VERSION 5.8 ;
BUSBITCHARS "[]" ;
DIVIDERCHAR "/" ;
UNITS
    DATABASE MICRONS 1000 ;
END UNITS

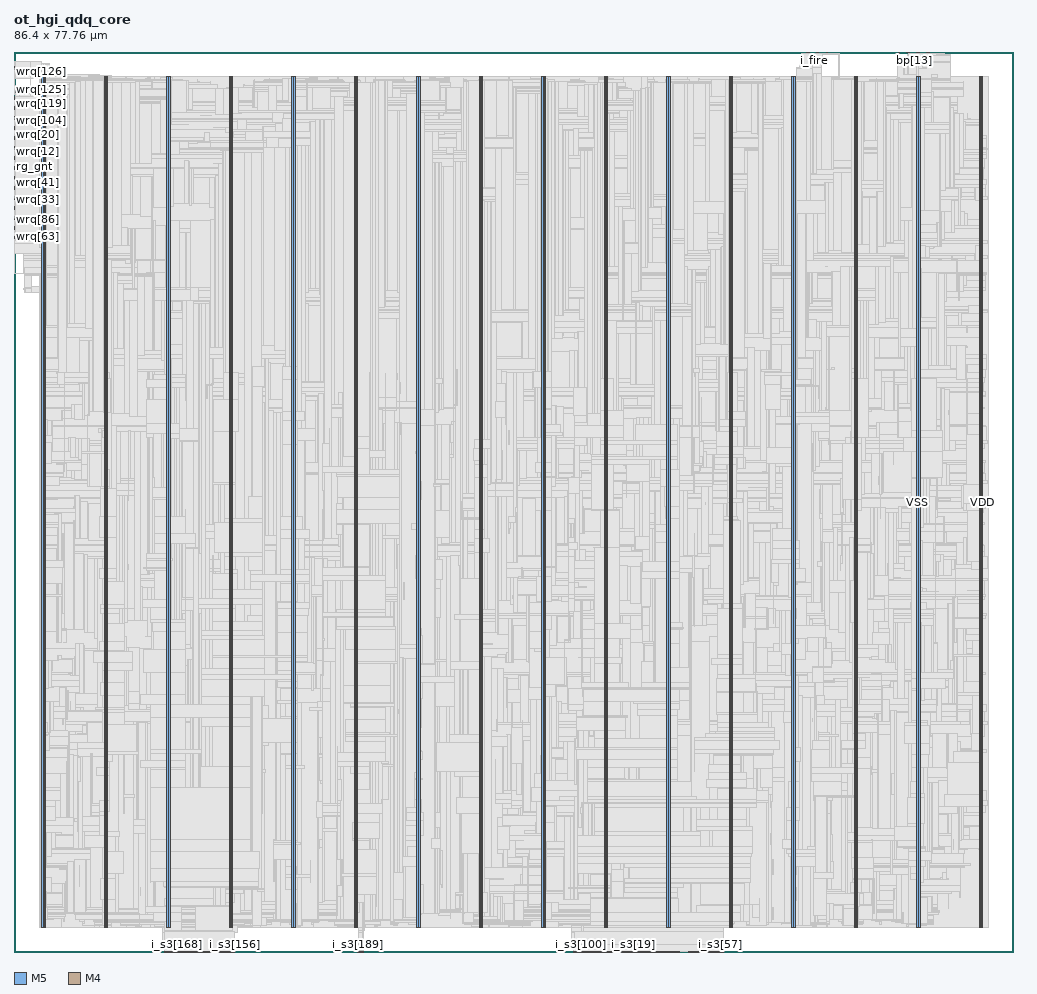
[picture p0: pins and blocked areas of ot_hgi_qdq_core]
MACRO ot_hgi_qdq_core
  FOREIGN ot_hgi_qdq_core 0 0 ;
  CLASS BLOCK ;
  SIZE 86.4 BY 77.76 ;
  PIN asm_rst_n
    DIRECTION OUTPUT ;
    USE SIGNAL ;
    PORT
      LAYER M5 ;
        RECT  76.464 77.676 76.488 77.76 ;
    END
  END asm_rst_n
  PIN bp[0]
    DIRECTION OUTPUT ;
    USE SIGNAL ;
    PORT
      LAYER M5 ;
        RECT  76.56 77.676 76.584 77.76 ;
    END
  END bp[0]
  PIN bp[10]
    DIRECTION OUTPUT ;
    USE SIGNAL ;
    PORT
      LAYER M5 ;
        RECT  77.52 77.676 77.544 77.76 ;
    END
  END bp[10]
  PIN bp[11]
    DIRECTION OUTPUT ;
    USE SIGNAL ;
    PORT
      LAYER M5 ;
        RECT  77.616 77.676 77.64 77.76 ;
    END
  END bp[11]
  PIN bp[12]
    DIRECTION OUTPUT ;
    USE SIGNAL ;
    PORT
      LAYER M5 ;
        RECT  77.712 77.676 77.736 77.76 ;
    END
  END bp[12]
  PIN bp[13]
    DIRECTION OUTPUT ;
    USE SIGNAL ;
    PORT
      LAYER M5 ;
        RECT  77.808 77.676 77.832 77.76 ;
    END
  END bp[13]
  PIN bp[14]
    DIRECTION OUTPUT ;
    USE SIGNAL ;
    PORT
      LAYER M5 ;
        RECT  77.904 77.676 77.928 77.76 ;
    END
  END bp[14]
  PIN bp[15]
    DIRECTION OUTPUT ;
    USE SIGNAL ;
    PORT
      LAYER M5 ;
        RECT  78 77.676 78.024 77.76 ;
    END
  END bp[15]
  PIN bp[16]
    DIRECTION OUTPUT ;
    USE SIGNAL ;
    PORT
      LAYER M5 ;
        RECT  78.096 77.676 78.12 77.76 ;
    END
  END bp[16]
  PIN bp[17]
    DIRECTION OUTPUT ;
    USE SIGNAL ;
    PORT
      LAYER M5 ;
        RECT  78.192 77.676 78.216 77.76 ;
    END
  END bp[17]
  PIN bp[18]
    DIRECTION OUTPUT ;
    USE SIGNAL ;
    PORT
      LAYER M5 ;
        RECT  78.288 77.676 78.312 77.76 ;
    END
  END bp[18]
  PIN bp[19]
    DIRECTION OUTPUT ;
    USE SIGNAL ;
    PORT
      LAYER M5 ;
        RECT  78.384 77.676 78.408 77.76 ;
    END
  END bp[19]
  PIN bp[1]
    DIRECTION OUTPUT ;
    USE SIGNAL ;
    PORT
      LAYER M5 ;
        RECT  76.656 77.676 76.68 77.76 ;
    END
  END bp[1]
  PIN bp[20]
    DIRECTION OUTPUT ;
    USE SIGNAL ;
    PORT
      LAYER M5 ;
        RECT  78.48 77.676 78.504 77.76 ;
    END
  END bp[20]
  PIN bp[21]
    DIRECTION OUTPUT ;
    USE SIGNAL ;
    PORT
      LAYER M5 ;
        RECT  78.576 77.676 78.6 77.76 ;
    END
  END bp[21]
  PIN bp[22]
    DIRECTION OUTPUT ;
    USE SIGNAL ;
    PORT
      LAYER M5 ;
        RECT  78.672 77.676 78.696 77.76 ;
    END
  END bp[22]
  PIN bp[23]
    DIRECTION OUTPUT ;
    USE SIGNAL ;
    PORT
      LAYER M5 ;
        RECT  78.768 77.676 78.792 77.76 ;
    END
  END bp[23]
  PIN bp[24]
    DIRECTION OUTPUT ;
    USE SIGNAL ;
    PORT
      LAYER M5 ;
        RECT  78.864 77.676 78.888 77.76 ;
    END
  END bp[24]
  PIN bp[25]
    DIRECTION OUTPUT ;
    USE SIGNAL ;
    PORT
      LAYER M5 ;
        RECT  78.96 77.676 78.984 77.76 ;
    END
  END bp[25]
  PIN bp[26]
    DIRECTION OUTPUT ;
    USE SIGNAL ;
    PORT
      LAYER M5 ;
        RECT  79.056 77.676 79.08 77.76 ;
    END
  END bp[26]
  PIN bp[27]
    DIRECTION OUTPUT ;
    USE SIGNAL ;
    PORT
      LAYER M5 ;
        RECT  79.152 77.676 79.176 77.76 ;
    END
  END bp[27]
  PIN bp[28]
    DIRECTION OUTPUT ;
    USE SIGNAL ;
    PORT
      LAYER M5 ;
        RECT  79.248 77.676 79.272 77.76 ;
    END
  END bp[28]
  PIN bp[29]
    DIRECTION OUTPUT ;
    USE SIGNAL ;
    PORT
      LAYER M5 ;
        RECT  79.344 77.676 79.368 77.76 ;
    END
  END bp[29]
  PIN bp[2]
    DIRECTION OUTPUT ;
    USE SIGNAL ;
    PORT
      LAYER M5 ;
        RECT  76.752 77.676 76.776 77.76 ;
    END
  END bp[2]
  PIN bp[30]
    DIRECTION OUTPUT ;
    USE SIGNAL ;
    PORT
      LAYER M5 ;
        RECT  79.44 77.676 79.464 77.76 ;
    END
  END bp[30]
  PIN bp[31]
    DIRECTION OUTPUT ;
    USE SIGNAL ;
    PORT
      LAYER M5 ;
        RECT  67.92 77.676 67.944 77.76 ;
    END
  END bp[31]
  PIN bp[32]
    DIRECTION OUTPUT ;
    USE SIGNAL ;
    PORT
      LAYER M5 ;
        RECT  68.016 77.676 68.04 77.76 ;
    END
  END bp[32]
  PIN bp[33]
    DIRECTION OUTPUT ;
    USE SIGNAL ;
    PORT
      LAYER M5 ;
        RECT  68.112 77.676 68.136 77.76 ;
    END
  END bp[33]
  PIN bp[34]
    DIRECTION OUTPUT ;
    USE SIGNAL ;
    PORT
      LAYER M5 ;
        RECT  68.208 77.676 68.232 77.76 ;
    END
  END bp[34]
  PIN bp[35]
    DIRECTION OUTPUT ;
    USE SIGNAL ;
    PORT
      LAYER M5 ;
        RECT  68.304 77.676 68.328 77.76 ;
    END
  END bp[35]
  PIN bp[36]
    DIRECTION OUTPUT ;
    USE SIGNAL ;
    PORT
      LAYER M5 ;
        RECT  68.4 77.676 68.424 77.76 ;
    END
  END bp[36]
  PIN bp[37]
    DIRECTION OUTPUT ;
    USE SIGNAL ;
    PORT
      LAYER M5 ;
        RECT  68.496 77.676 68.52 77.76 ;
    END
  END bp[37]
  PIN bp[38]
    DIRECTION OUTPUT ;
    USE SIGNAL ;
    PORT
      LAYER M5 ;
        RECT  68.592 77.676 68.616 77.76 ;
    END
  END bp[38]
  PIN bp[39]
    DIRECTION OUTPUT ;
    USE SIGNAL ;
    PORT
      LAYER M5 ;
        RECT  68.688 77.676 68.712 77.76 ;
    END
  END bp[39]
  PIN bp[3]
    DIRECTION OUTPUT ;
    USE SIGNAL ;
    PORT
      LAYER M5 ;
        RECT  76.848 77.676 76.872 77.76 ;
    END
  END bp[3]
  PIN bp[4]
    DIRECTION OUTPUT ;
    USE SIGNAL ;
    PORT
      LAYER M5 ;
        RECT  76.944 77.676 76.968 77.76 ;
    END
  END bp[4]
  PIN bp[5]
    DIRECTION OUTPUT ;
    USE SIGNAL ;
    PORT
      LAYER M5 ;
        RECT  77.04 77.676 77.064 77.76 ;
    END
  END bp[5]
  PIN bp[6]
    DIRECTION OUTPUT ;
    USE SIGNAL ;
    PORT
      LAYER M5 ;
        RECT  77.136 77.676 77.16 77.76 ;
    END
  END bp[6]
  PIN bp[7]
    DIRECTION OUTPUT ;
    USE SIGNAL ;
    PORT
      LAYER M5 ;
        RECT  77.232 77.676 77.256 77.76 ;
    END
  END bp[7]
  PIN bp[8]
    DIRECTION OUTPUT ;
    USE SIGNAL ;
    PORT
      LAYER M5 ;
        RECT  77.328 77.676 77.352 77.76 ;
    END
  END bp[8]
  PIN bp[9]
    DIRECTION OUTPUT ;
    USE SIGNAL ;
    PORT
      LAYER M5 ;
        RECT  77.424 77.676 77.448 77.76 ;
    END
  END bp[9]
  PIN bp_v
    DIRECTION OUTPUT ;
    USE SIGNAL ;
    PORT
      LAYER M5 ;
        RECT  68.784 77.676 68.808 77.76 ;
    END
  END bp_v
  PIN clk
    DIRECTION INPUT ;
    USE SIGNAL ;
    PORT
      LAYER M5 ;
        RECT  51.408 0 51.432 0.084 ;
    END
  END clk
  PIN i_abad
    DIRECTION INPUT ;
    USE SIGNAL ;
    PORT
      LAYER M5 ;
        RECT  68.88 77.676 68.904 77.76 ;
    END
  END i_abad
  PIN i_aidle
    DIRECTION INPUT ;
    USE SIGNAL ;
    PORT
      LAYER M5 ;
        RECT  68.976 77.676 69 77.76 ;
    END
  END i_aidle
  PIN i_fin
    DIRECTION INPUT ;
    USE SIGNAL ;
    PORT
      LAYER M5 ;
        RECT  69.072 77.676 69.096 77.76 ;
    END
  END i_fin
  PIN i_fire
    DIRECTION INPUT ;
    USE SIGNAL ;
    PORT
      LAYER M5 ;
        RECT  69.168 77.676 69.192 77.76 ;
    END
  END i_fire
  PIN i_nfault
    DIRECTION INPUT ;
    USE SIGNAL ;
    PORT
      LAYER M5 ;
        RECT  51.504 0 51.528 0.084 ;
    END
  END i_nfault
  PIN i_pop[0]
    DIRECTION INPUT ;
    USE SIGNAL ;
    PORT
      LAYER M5 ;
        RECT  69.264 77.676 69.288 77.76 ;
    END
  END i_pop[0]
  PIN i_pop[1]
    DIRECTION INPUT ;
    USE SIGNAL ;
    PORT
      LAYER M5 ;
        RECT  69.36 77.676 69.384 77.76 ;
    END
  END i_pop[1]
  PIN i_pop[2]
    DIRECTION INPUT ;
    USE SIGNAL ;
    PORT
      LAYER M5 ;
        RECT  69.456 77.676 69.48 77.76 ;
    END
  END i_pop[2]
  PIN i_pop[3]
    DIRECTION INPUT ;
    USE SIGNAL ;
    PORT
      LAYER M5 ;
        RECT  69.552 77.676 69.576 77.76 ;
    END
  END i_pop[3]
  PIN i_pop[4]
    DIRECTION INPUT ;
    USE SIGNAL ;
    PORT
      LAYER M5 ;
        RECT  69.648 77.676 69.672 77.76 ;
    END
  END i_pop[4]
  PIN i_pop[5]
    DIRECTION INPUT ;
    USE SIGNAL ;
    PORT
      LAYER M5 ;
        RECT  69.744 77.676 69.768 77.76 ;
    END
  END i_pop[5]
  PIN i_pop[6]
    DIRECTION INPUT ;
    USE SIGNAL ;
    PORT
      LAYER M5 ;
        RECT  69.84 77.676 69.864 77.76 ;
    END
  END i_pop[6]
  PIN i_pop[7]
    DIRECTION INPUT ;
    USE SIGNAL ;
    PORT
      LAYER M5 ;
        RECT  69.936 77.676 69.96 77.76 ;
    END
  END i_pop[7]
  PIN i_s1_v
    DIRECTION INPUT ;
    USE SIGNAL ;
    PORT
      LAYER M5 ;
        RECT  51.6 0 51.624 0.084 ;
    END
  END i_s1_v
  PIN i_s3[0]
    DIRECTION INPUT ;
    USE SIGNAL ;
    PORT
      LAYER M5 ;
        RECT  51.696 0 51.72 0.084 ;
    END
  END i_s3[0]
  PIN i_s3[100]
    DIRECTION INPUT ;
    USE SIGNAL ;
    PORT
      LAYER M5 ;
        RECT  49.008 0 49.032 0.084 ;
    END
  END i_s3[100]
  PIN i_s3[101]
    DIRECTION INPUT ;
    USE SIGNAL ;
    PORT
      LAYER M5 ;
        RECT  49.104 0 49.128 0.084 ;
    END
  END i_s3[101]
  PIN i_s3[102]
    DIRECTION INPUT ;
    USE SIGNAL ;
    PORT
      LAYER M5 ;
        RECT  49.2 0 49.224 0.084 ;
    END
  END i_s3[102]
  PIN i_s3[103]
    DIRECTION INPUT ;
    USE SIGNAL ;
    PORT
      LAYER M5 ;
        RECT  49.296 0 49.32 0.084 ;
    END
  END i_s3[103]
  PIN i_s3[104]
    DIRECTION INPUT ;
    USE SIGNAL ;
    PORT
      LAYER M5 ;
        RECT  49.392 0 49.416 0.084 ;
    END
  END i_s3[104]
  PIN i_s3[105]
    DIRECTION INPUT ;
    USE SIGNAL ;
    PORT
      LAYER M5 ;
        RECT  49.488 0 49.512 0.084 ;
    END
  END i_s3[105]
  PIN i_s3[106]
    DIRECTION INPUT ;
    USE SIGNAL ;
    PORT
      LAYER M5 ;
        RECT  49.584 0 49.608 0.084 ;
    END
  END i_s3[106]
  PIN i_s3[107]
    DIRECTION INPUT ;
    USE SIGNAL ;
    PORT
      LAYER M5 ;
        RECT  49.68 0 49.704 0.084 ;
    END
  END i_s3[107]
  PIN i_s3[108]
    DIRECTION INPUT ;
    USE SIGNAL ;
    PORT
      LAYER M5 ;
        RECT  49.776 0 49.8 0.084 ;
    END
  END i_s3[108]
  PIN i_s3[109]
    DIRECTION INPUT ;
    USE SIGNAL ;
    PORT
      LAYER M5 ;
        RECT  49.872 0 49.896 0.084 ;
    END
  END i_s3[109]
  PIN i_s3[10]
    DIRECTION INPUT ;
    USE SIGNAL ;
    PORT
      LAYER M5 ;
        RECT  52.656 0 52.68 0.084 ;
    END
  END i_s3[10]
  PIN i_s3[110]
    DIRECTION INPUT ;
    USE SIGNAL ;
    PORT
      LAYER M5 ;
        RECT  49.968 0 49.992 0.084 ;
    END
  END i_s3[110]
  PIN i_s3[111]
    DIRECTION INPUT ;
    USE SIGNAL ;
    PORT
      LAYER M5 ;
        RECT  50.064 0 50.088 0.084 ;
    END
  END i_s3[111]
  PIN i_s3[112]
    DIRECTION INPUT ;
    USE SIGNAL ;
    PORT
      LAYER M5 ;
        RECT  50.16 0 50.184 0.084 ;
    END
  END i_s3[112]
  PIN i_s3[113]
    DIRECTION INPUT ;
    USE SIGNAL ;
    PORT
      LAYER M5 ;
        RECT  50.256 0 50.28 0.084 ;
    END
  END i_s3[113]
  PIN i_s3[114]
    DIRECTION INPUT ;
    USE SIGNAL ;
    PORT
      LAYER M5 ;
        RECT  50.352 0 50.376 0.084 ;
    END
  END i_s3[114]
  PIN i_s3[115]
    DIRECTION INPUT ;
    USE SIGNAL ;
    PORT
      LAYER M5 ;
        RECT  50.448 0 50.472 0.084 ;
    END
  END i_s3[115]
  PIN i_s3[116]
    DIRECTION INPUT ;
    USE SIGNAL ;
    PORT
      LAYER M5 ;
        RECT  50.544 0 50.568 0.084 ;
    END
  END i_s3[116]
  PIN i_s3[117]
    DIRECTION INPUT ;
    USE SIGNAL ;
    PORT
      LAYER M5 ;
        RECT  50.64 0 50.664 0.084 ;
    END
  END i_s3[117]
  PIN i_s3[118]
    DIRECTION INPUT ;
    USE SIGNAL ;
    PORT
      LAYER M5 ;
        RECT  50.736 0 50.76 0.084 ;
    END
  END i_s3[118]
  PIN i_s3[119]
    DIRECTION INPUT ;
    USE SIGNAL ;
    PORT
      LAYER M5 ;
        RECT  50.832 0 50.856 0.084 ;
    END
  END i_s3[119]
  PIN i_s3[11]
    DIRECTION INPUT ;
    USE SIGNAL ;
    PORT
      LAYER M5 ;
        RECT  52.752 0 52.776 0.084 ;
    END
  END i_s3[11]
  PIN i_s3[120]
    DIRECTION INPUT ;
    USE SIGNAL ;
    PORT
      LAYER M5 ;
        RECT  50.928 0 50.952 0.084 ;
    END
  END i_s3[120]
  PIN i_s3[121]
    DIRECTION INPUT ;
    USE SIGNAL ;
    PORT
      LAYER M5 ;
        RECT  51.024 0 51.048 0.084 ;
    END
  END i_s3[121]
  PIN i_s3[122]
    DIRECTION INPUT ;
    USE SIGNAL ;
    PORT
      LAYER M5 ;
        RECT  51.12 0 51.144 0.084 ;
    END
  END i_s3[122]
  PIN i_s3[123]
    DIRECTION INPUT ;
    USE SIGNAL ;
    PORT
      LAYER M5 ;
        RECT  51.216 0 51.24 0.084 ;
    END
  END i_s3[123]
  PIN i_s3[124]
    DIRECTION INPUT ;
    USE SIGNAL ;
    PORT
      LAYER M5 ;
        RECT  51.312 0 51.336 0.084 ;
    END
  END i_s3[124]
  PIN i_s3[125]
    DIRECTION INPUT ;
    USE SIGNAL ;
    PORT
      LAYER M5 ;
        RECT  16.08 0 16.104 0.084 ;
    END
  END i_s3[125]
  PIN i_s3[126]
    DIRECTION INPUT ;
    USE SIGNAL ;
    PORT
      LAYER M5 ;
        RECT  16.176 0 16.2 0.084 ;
    END
  END i_s3[126]
  PIN i_s3[127]
    DIRECTION INPUT ;
    USE SIGNAL ;
    PORT
      LAYER M5 ;
        RECT  16.272 0 16.296 0.084 ;
    END
  END i_s3[127]
  PIN i_s3[128]
    DIRECTION INPUT ;
    USE SIGNAL ;
    PORT
      LAYER M5 ;
        RECT  16.368 0 16.392 0.084 ;
    END
  END i_s3[128]
  PIN i_s3[129]
    DIRECTION INPUT ;
    USE SIGNAL ;
    PORT
      LAYER M5 ;
        RECT  16.464 0 16.488 0.084 ;
    END
  END i_s3[129]
  PIN i_s3[12]
    DIRECTION INPUT ;
    USE SIGNAL ;
    PORT
      LAYER M5 ;
        RECT  52.848 0 52.872 0.084 ;
    END
  END i_s3[12]
  PIN i_s3[130]
    DIRECTION INPUT ;
    USE SIGNAL ;
    PORT
      LAYER M5 ;
        RECT  16.56 0 16.584 0.084 ;
    END
  END i_s3[130]
  PIN i_s3[131]
    DIRECTION INPUT ;
    USE SIGNAL ;
    PORT
      LAYER M5 ;
        RECT  16.656 0 16.68 0.084 ;
    END
  END i_s3[131]
  PIN i_s3[132]
    DIRECTION INPUT ;
    USE SIGNAL ;
    PORT
      LAYER M5 ;
        RECT  16.752 0 16.776 0.084 ;
    END
  END i_s3[132]
  PIN i_s3[133]
    DIRECTION INPUT ;
    USE SIGNAL ;
    PORT
      LAYER M5 ;
        RECT  16.848 0 16.872 0.084 ;
    END
  END i_s3[133]
  PIN i_s3[134]
    DIRECTION INPUT ;
    USE SIGNAL ;
    PORT
      LAYER M5 ;
        RECT  16.944 0 16.968 0.084 ;
    END
  END i_s3[134]
  PIN i_s3[135]
    DIRECTION INPUT ;
    USE SIGNAL ;
    PORT
      LAYER M5 ;
        RECT  17.04 0 17.064 0.084 ;
    END
  END i_s3[135]
  PIN i_s3[136]
    DIRECTION INPUT ;
    USE SIGNAL ;
    PORT
      LAYER M5 ;
        RECT  17.136 0 17.16 0.084 ;
    END
  END i_s3[136]
  PIN i_s3[137]
    DIRECTION INPUT ;
    USE SIGNAL ;
    PORT
      LAYER M5 ;
        RECT  17.232 0 17.256 0.084 ;
    END
  END i_s3[137]
  PIN i_s3[138]
    DIRECTION INPUT ;
    USE SIGNAL ;
    PORT
      LAYER M5 ;
        RECT  17.328 0 17.352 0.084 ;
    END
  END i_s3[138]
  PIN i_s3[139]
    DIRECTION INPUT ;
    USE SIGNAL ;
    PORT
      LAYER M5 ;
        RECT  17.424 0 17.448 0.084 ;
    END
  END i_s3[139]
  PIN i_s3[13]
    DIRECTION INPUT ;
    USE SIGNAL ;
    PORT
      LAYER M5 ;
        RECT  52.944 0 52.968 0.084 ;
    END
  END i_s3[13]
  PIN i_s3[140]
    DIRECTION INPUT ;
    USE SIGNAL ;
    PORT
      LAYER M5 ;
        RECT  17.52 0 17.544 0.084 ;
    END
  END i_s3[140]
  PIN i_s3[141]
    DIRECTION INPUT ;
    USE SIGNAL ;
    PORT
      LAYER M5 ;
        RECT  17.616 0 17.64 0.084 ;
    END
  END i_s3[141]
  PIN i_s3[142]
    DIRECTION INPUT ;
    USE SIGNAL ;
    PORT
      LAYER M5 ;
        RECT  17.712 0 17.736 0.084 ;
    END
  END i_s3[142]
  PIN i_s3[143]
    DIRECTION INPUT ;
    USE SIGNAL ;
    PORT
      LAYER M5 ;
        RECT  17.808 0 17.832 0.084 ;
    END
  END i_s3[143]
  PIN i_s3[144]
    DIRECTION INPUT ;
    USE SIGNAL ;
    PORT
      LAYER M5 ;
        RECT  17.904 0 17.928 0.084 ;
    END
  END i_s3[144]
  PIN i_s3[145]
    DIRECTION INPUT ;
    USE SIGNAL ;
    PORT
      LAYER M5 ;
        RECT  18 0 18.024 0.084 ;
    END
  END i_s3[145]
  PIN i_s3[146]
    DIRECTION INPUT ;
    USE SIGNAL ;
    PORT
      LAYER M5 ;
        RECT  18.096 0 18.12 0.084 ;
    END
  END i_s3[146]
  PIN i_s3[147]
    DIRECTION INPUT ;
    USE SIGNAL ;
    PORT
      LAYER M5 ;
        RECT  18.192 0 18.216 0.084 ;
    END
  END i_s3[147]
  PIN i_s3[148]
    DIRECTION INPUT ;
    USE SIGNAL ;
    PORT
      LAYER M5 ;
        RECT  18.288 0 18.312 0.084 ;
    END
  END i_s3[148]
  PIN i_s3[149]
    DIRECTION INPUT ;
    USE SIGNAL ;
    PORT
      LAYER M5 ;
        RECT  18.384 0 18.408 0.084 ;
    END
  END i_s3[149]
  PIN i_s3[14]
    DIRECTION INPUT ;
    USE SIGNAL ;
    PORT
      LAYER M5 ;
        RECT  53.04 0 53.064 0.084 ;
    END
  END i_s3[14]
  PIN i_s3[150]
    DIRECTION INPUT ;
    USE SIGNAL ;
    PORT
      LAYER M5 ;
        RECT  18.48 0 18.504 0.084 ;
    END
  END i_s3[150]
  PIN i_s3[151]
    DIRECTION INPUT ;
    USE SIGNAL ;
    PORT
      LAYER M5 ;
        RECT  18.576 0 18.6 0.084 ;
    END
  END i_s3[151]
  PIN i_s3[152]
    DIRECTION INPUT ;
    USE SIGNAL ;
    PORT
      LAYER M5 ;
        RECT  18.672 0 18.696 0.084 ;
    END
  END i_s3[152]
  PIN i_s3[153]
    DIRECTION INPUT ;
    USE SIGNAL ;
    PORT
      LAYER M5 ;
        RECT  18.768 0 18.792 0.084 ;
    END
  END i_s3[153]
  PIN i_s3[154]
    DIRECTION INPUT ;
    USE SIGNAL ;
    PORT
      LAYER M5 ;
        RECT  18.864 0 18.888 0.084 ;
    END
  END i_s3[154]
  PIN i_s3[155]
    DIRECTION INPUT ;
    USE SIGNAL ;
    PORT
      LAYER M5 ;
        RECT  18.96 0 18.984 0.084 ;
    END
  END i_s3[155]
  PIN i_s3[156]
    DIRECTION INPUT ;
    USE SIGNAL ;
    PORT
      LAYER M5 ;
        RECT  19.056 0 19.08 0.084 ;
    END
  END i_s3[156]
  PIN i_s3[157]
    DIRECTION INPUT ;
    USE SIGNAL ;
    PORT
      LAYER M5 ;
        RECT  13.008 0 13.032 0.084 ;
    END
  END i_s3[157]
  PIN i_s3[158]
    DIRECTION INPUT ;
    USE SIGNAL ;
    PORT
      LAYER M5 ;
        RECT  13.104 0 13.128 0.084 ;
    END
  END i_s3[158]
  PIN i_s3[159]
    DIRECTION INPUT ;
    USE SIGNAL ;
    PORT
      LAYER M5 ;
        RECT  13.2 0 13.224 0.084 ;
    END
  END i_s3[159]
  PIN i_s3[15]
    DIRECTION INPUT ;
    USE SIGNAL ;
    PORT
      LAYER M5 ;
        RECT  53.136 0 53.16 0.084 ;
    END
  END i_s3[15]
  PIN i_s3[160]
    DIRECTION INPUT ;
    USE SIGNAL ;
    PORT
      LAYER M5 ;
        RECT  13.296 0 13.32 0.084 ;
    END
  END i_s3[160]
  PIN i_s3[161]
    DIRECTION INPUT ;
    USE SIGNAL ;
    PORT
      LAYER M5 ;
        RECT  13.392 0 13.416 0.084 ;
    END
  END i_s3[161]
  PIN i_s3[162]
    DIRECTION INPUT ;
    USE SIGNAL ;
    PORT
      LAYER M5 ;
        RECT  13.488 0 13.512 0.084 ;
    END
  END i_s3[162]
  PIN i_s3[163]
    DIRECTION INPUT ;
    USE SIGNAL ;
    PORT
      LAYER M5 ;
        RECT  13.584 0 13.608 0.084 ;
    END
  END i_s3[163]
  PIN i_s3[164]
    DIRECTION INPUT ;
    USE SIGNAL ;
    PORT
      LAYER M5 ;
        RECT  13.68 0 13.704 0.084 ;
    END
  END i_s3[164]
  PIN i_s3[165]
    DIRECTION INPUT ;
    USE SIGNAL ;
    PORT
      LAYER M5 ;
        RECT  13.776 0 13.8 0.084 ;
    END
  END i_s3[165]
  PIN i_s3[166]
    DIRECTION INPUT ;
    USE SIGNAL ;
    PORT
      LAYER M5 ;
        RECT  13.872 0 13.896 0.084 ;
    END
  END i_s3[166]
  PIN i_s3[167]
    DIRECTION INPUT ;
    USE SIGNAL ;
    PORT
      LAYER M5 ;
        RECT  13.968 0 13.992 0.084 ;
    END
  END i_s3[167]
  PIN i_s3[168]
    DIRECTION INPUT ;
    USE SIGNAL ;
    PORT
      LAYER M5 ;
        RECT  14.064 0 14.088 0.084 ;
    END
  END i_s3[168]
  PIN i_s3[169]
    DIRECTION INPUT ;
    USE SIGNAL ;
    PORT
      LAYER M5 ;
        RECT  14.16 0 14.184 0.084 ;
    END
  END i_s3[169]
  PIN i_s3[16]
    DIRECTION INPUT ;
    USE SIGNAL ;
    PORT
      LAYER M5 ;
        RECT  53.232 0 53.256 0.084 ;
    END
  END i_s3[16]
  PIN i_s3[170]
    DIRECTION INPUT ;
    USE SIGNAL ;
    PORT
      LAYER M5 ;
        RECT  14.256 0 14.28 0.084 ;
    END
  END i_s3[170]
  PIN i_s3[171]
    DIRECTION INPUT ;
    USE SIGNAL ;
    PORT
      LAYER M5 ;
        RECT  14.352 0 14.376 0.084 ;
    END
  END i_s3[171]
  PIN i_s3[172]
    DIRECTION INPUT ;
    USE SIGNAL ;
    PORT
      LAYER M5 ;
        RECT  14.448 0 14.472 0.084 ;
    END
  END i_s3[172]
  PIN i_s3[173]
    DIRECTION INPUT ;
    USE SIGNAL ;
    PORT
      LAYER M5 ;
        RECT  14.544 0 14.568 0.084 ;
    END
  END i_s3[173]
  PIN i_s3[174]
    DIRECTION INPUT ;
    USE SIGNAL ;
    PORT
      LAYER M5 ;
        RECT  14.64 0 14.664 0.084 ;
    END
  END i_s3[174]
  PIN i_s3[175]
    DIRECTION INPUT ;
    USE SIGNAL ;
    PORT
      LAYER M5 ;
        RECT  14.736 0 14.76 0.084 ;
    END
  END i_s3[175]
  PIN i_s3[176]
    DIRECTION INPUT ;
    USE SIGNAL ;
    PORT
      LAYER M5 ;
        RECT  14.832 0 14.856 0.084 ;
    END
  END i_s3[176]
  PIN i_s3[177]
    DIRECTION INPUT ;
    USE SIGNAL ;
    PORT
      LAYER M5 ;
        RECT  14.928 0 14.952 0.084 ;
    END
  END i_s3[177]
  PIN i_s3[178]
    DIRECTION INPUT ;
    USE SIGNAL ;
    PORT
      LAYER M5 ;
        RECT  15.024 0 15.048 0.084 ;
    END
  END i_s3[178]
  PIN i_s3[179]
    DIRECTION INPUT ;
    USE SIGNAL ;
    PORT
      LAYER M5 ;
        RECT  15.12 0 15.144 0.084 ;
    END
  END i_s3[179]
  PIN i_s3[17]
    DIRECTION INPUT ;
    USE SIGNAL ;
    PORT
      LAYER M5 ;
        RECT  53.328 0 53.352 0.084 ;
    END
  END i_s3[17]
  PIN i_s3[180]
    DIRECTION INPUT ;
    USE SIGNAL ;
    PORT
      LAYER M5 ;
        RECT  15.216 0 15.24 0.084 ;
    END
  END i_s3[180]
  PIN i_s3[181]
    DIRECTION INPUT ;
    USE SIGNAL ;
    PORT
      LAYER M5 ;
        RECT  15.312 0 15.336 0.084 ;
    END
  END i_s3[181]
  PIN i_s3[182]
    DIRECTION INPUT ;
    USE SIGNAL ;
    PORT
      LAYER M5 ;
        RECT  15.408 0 15.432 0.084 ;
    END
  END i_s3[182]
  PIN i_s3[183]
    DIRECTION INPUT ;
    USE SIGNAL ;
    PORT
      LAYER M5 ;
        RECT  15.504 0 15.528 0.084 ;
    END
  END i_s3[183]
  PIN i_s3[184]
    DIRECTION INPUT ;
    USE SIGNAL ;
    PORT
      LAYER M5 ;
        RECT  15.6 0 15.624 0.084 ;
    END
  END i_s3[184]
  PIN i_s3[185]
    DIRECTION INPUT ;
    USE SIGNAL ;
    PORT
      LAYER M5 ;
        RECT  15.696 0 15.72 0.084 ;
    END
  END i_s3[185]
  PIN i_s3[186]
    DIRECTION INPUT ;
    USE SIGNAL ;
    PORT
      LAYER M5 ;
        RECT  15.792 0 15.816 0.084 ;
    END
  END i_s3[186]
  PIN i_s3[187]
    DIRECTION INPUT ;
    USE SIGNAL ;
    PORT
      LAYER M5 ;
        RECT  15.888 0 15.912 0.084 ;
    END
  END i_s3[187]
  PIN i_s3[188]
    DIRECTION INPUT ;
    USE SIGNAL ;
    PORT
      LAYER M5 ;
        RECT  15.984 0 16.008 0.084 ;
    END
  END i_s3[188]
  PIN i_s3[189]
    DIRECTION INPUT ;
    USE SIGNAL ;
    PORT
      LAYER M5 ;
        RECT  29.712 0 29.736 0.084 ;
    END
  END i_s3[189]
  PIN i_s3[18]
    DIRECTION INPUT ;
    USE SIGNAL ;
    PORT
      LAYER M5 ;
        RECT  53.424 0 53.448 0.084 ;
    END
  END i_s3[18]
  PIN i_s3[19]
    DIRECTION INPUT ;
    USE SIGNAL ;
    PORT
      LAYER M5 ;
        RECT  53.52 0 53.544 0.084 ;
    END
  END i_s3[19]
  PIN i_s3[1]
    DIRECTION INPUT ;
    USE SIGNAL ;
    PORT
      LAYER M5 ;
        RECT  51.792 0 51.816 0.084 ;
    END
  END i_s3[1]
  PIN i_s3[20]
    DIRECTION INPUT ;
    USE SIGNAL ;
    PORT
      LAYER M5 ;
        RECT  53.616 0 53.64 0.084 ;
    END
  END i_s3[20]
  PIN i_s3[21]
    DIRECTION INPUT ;
    USE SIGNAL ;
    PORT
      LAYER M5 ;
        RECT  53.712 0 53.736 0.084 ;
    END
  END i_s3[21]
  PIN i_s3[22]
    DIRECTION INPUT ;
    USE SIGNAL ;
    PORT
      LAYER M5 ;
        RECT  53.808 0 53.832 0.084 ;
    END
  END i_s3[22]
  PIN i_s3[23]
    DIRECTION INPUT ;
    USE SIGNAL ;
    PORT
      LAYER M5 ;
        RECT  53.904 0 53.928 0.084 ;
    END
  END i_s3[23]
  PIN i_s3[24]
    DIRECTION INPUT ;
    USE SIGNAL ;
    PORT
      LAYER M5 ;
        RECT  54 0 54.024 0.084 ;
    END
  END i_s3[24]
  PIN i_s3[25]
    DIRECTION INPUT ;
    USE SIGNAL ;
    PORT
      LAYER M5 ;
        RECT  54.096 0 54.12 0.084 ;
    END
  END i_s3[25]
  PIN i_s3[26]
    DIRECTION INPUT ;
    USE SIGNAL ;
    PORT
      LAYER M5 ;
        RECT  54.192 0 54.216 0.084 ;
    END
  END i_s3[26]
  PIN i_s3[27]
    DIRECTION INPUT ;
    USE SIGNAL ;
    PORT
      LAYER M5 ;
        RECT  54.288 0 54.312 0.084 ;
    END
  END i_s3[27]
  PIN i_s3[28]
    DIRECTION INPUT ;
    USE SIGNAL ;
    PORT
      LAYER M5 ;
        RECT  54.384 0 54.408 0.084 ;
    END
  END i_s3[28]
  PIN i_s3[29]
    DIRECTION INPUT ;
    USE SIGNAL ;
    PORT
      LAYER M5 ;
        RECT  58.32 0 58.344 0.084 ;
    END
  END i_s3[29]
  PIN i_s3[2]
    DIRECTION INPUT ;
    USE SIGNAL ;
    PORT
      LAYER M5 ;
        RECT  51.888 0 51.912 0.084 ;
    END
  END i_s3[2]
  PIN i_s3[30]
    DIRECTION INPUT ;
    USE SIGNAL ;
    PORT
      LAYER M5 ;
        RECT  58.416 0 58.44 0.084 ;
    END
  END i_s3[30]
  PIN i_s3[31]
    DIRECTION INPUT ;
    USE SIGNAL ;
    PORT
      LAYER M5 ;
        RECT  58.512 0 58.536 0.084 ;
    END
  END i_s3[31]
  PIN i_s3[32]
    DIRECTION INPUT ;
    USE SIGNAL ;
    PORT
      LAYER M5 ;
        RECT  58.608 0 58.632 0.084 ;
    END
  END i_s3[32]
  PIN i_s3[33]
    DIRECTION INPUT ;
    USE SIGNAL ;
    PORT
      LAYER M5 ;
        RECT  58.704 0 58.728 0.084 ;
    END
  END i_s3[33]
  PIN i_s3[34]
    DIRECTION INPUT ;
    USE SIGNAL ;
    PORT
      LAYER M5 ;
        RECT  58.8 0 58.824 0.084 ;
    END
  END i_s3[34]
  PIN i_s3[35]
    DIRECTION INPUT ;
    USE SIGNAL ;
    PORT
      LAYER M5 ;
        RECT  58.896 0 58.92 0.084 ;
    END
  END i_s3[35]
  PIN i_s3[36]
    DIRECTION INPUT ;
    USE SIGNAL ;
    PORT
      LAYER M5 ;
        RECT  58.992 0 59.016 0.084 ;
    END
  END i_s3[36]
  PIN i_s3[37]
    DIRECTION INPUT ;
    USE SIGNAL ;
    PORT
      LAYER M5 ;
        RECT  59.088 0 59.112 0.084 ;
    END
  END i_s3[37]
  PIN i_s3[38]
    DIRECTION INPUT ;
    USE SIGNAL ;
    PORT
      LAYER M5 ;
        RECT  59.184 0 59.208 0.084 ;
    END
  END i_s3[38]
  PIN i_s3[39]
    DIRECTION INPUT ;
    USE SIGNAL ;
    PORT
      LAYER M5 ;
        RECT  59.28 0 59.304 0.084 ;
    END
  END i_s3[39]
  PIN i_s3[3]
    DIRECTION INPUT ;
    USE SIGNAL ;
    PORT
      LAYER M5 ;
        RECT  51.984 0 52.008 0.084 ;
    END
  END i_s3[3]
  PIN i_s3[40]
    DIRECTION INPUT ;
    USE SIGNAL ;
    PORT
      LAYER M5 ;
        RECT  59.376 0 59.4 0.084 ;
    END
  END i_s3[40]
  PIN i_s3[41]
    DIRECTION INPUT ;
    USE SIGNAL ;
    PORT
      LAYER M5 ;
        RECT  59.472 0 59.496 0.084 ;
    END
  END i_s3[41]
  PIN i_s3[42]
    DIRECTION INPUT ;
    USE SIGNAL ;
    PORT
      LAYER M5 ;
        RECT  59.568 0 59.592 0.084 ;
    END
  END i_s3[42]
  PIN i_s3[43]
    DIRECTION INPUT ;
    USE SIGNAL ;
    PORT
      LAYER M5 ;
        RECT  59.664 0 59.688 0.084 ;
    END
  END i_s3[43]
  PIN i_s3[44]
    DIRECTION INPUT ;
    USE SIGNAL ;
    PORT
      LAYER M5 ;
        RECT  59.76 0 59.784 0.084 ;
    END
  END i_s3[44]
  PIN i_s3[45]
    DIRECTION INPUT ;
    USE SIGNAL ;
    PORT
      LAYER M5 ;
        RECT  59.856 0 59.88 0.084 ;
    END
  END i_s3[45]
  PIN i_s3[46]
    DIRECTION INPUT ;
    USE SIGNAL ;
    PORT
      LAYER M5 ;
        RECT  59.952 0 59.976 0.084 ;
    END
  END i_s3[46]
  PIN i_s3[47]
    DIRECTION INPUT ;
    USE SIGNAL ;
    PORT
      LAYER M5 ;
        RECT  60.048 0 60.072 0.084 ;
    END
  END i_s3[47]
  PIN i_s3[48]
    DIRECTION INPUT ;
    USE SIGNAL ;
    PORT
      LAYER M5 ;
        RECT  60.144 0 60.168 0.084 ;
    END
  END i_s3[48]
  PIN i_s3[49]
    DIRECTION INPUT ;
    USE SIGNAL ;
    PORT
      LAYER M5 ;
        RECT  60.24 0 60.264 0.084 ;
    END
  END i_s3[49]
  PIN i_s3[4]
    DIRECTION INPUT ;
    USE SIGNAL ;
    PORT
      LAYER M5 ;
        RECT  52.08 0 52.104 0.084 ;
    END
  END i_s3[4]
  PIN i_s3[50]
    DIRECTION INPUT ;
    USE SIGNAL ;
    PORT
      LAYER M5 ;
        RECT  60.336 0 60.36 0.084 ;
    END
  END i_s3[50]
  PIN i_s3[51]
    DIRECTION INPUT ;
    USE SIGNAL ;
    PORT
      LAYER M5 ;
        RECT  60.432 0 60.456 0.084 ;
    END
  END i_s3[51]
  PIN i_s3[52]
    DIRECTION INPUT ;
    USE SIGNAL ;
    PORT
      LAYER M5 ;
        RECT  60.528 0 60.552 0.084 ;
    END
  END i_s3[52]
  PIN i_s3[53]
    DIRECTION INPUT ;
    USE SIGNAL ;
    PORT
      LAYER M5 ;
        RECT  60.624 0 60.648 0.084 ;
    END
  END i_s3[53]
  PIN i_s3[54]
    DIRECTION INPUT ;
    USE SIGNAL ;
    PORT
      LAYER M5 ;
        RECT  60.72 0 60.744 0.084 ;
    END
  END i_s3[54]
  PIN i_s3[55]
    DIRECTION INPUT ;
    USE SIGNAL ;
    PORT
      LAYER M5 ;
        RECT  60.816 0 60.84 0.084 ;
    END
  END i_s3[55]
  PIN i_s3[56]
    DIRECTION INPUT ;
    USE SIGNAL ;
    PORT
      LAYER M5 ;
        RECT  60.912 0 60.936 0.084 ;
    END
  END i_s3[56]
  PIN i_s3[57]
    DIRECTION INPUT ;
    USE SIGNAL ;
    PORT
      LAYER M5 ;
        RECT  61.008 0 61.032 0.084 ;
    END
  END i_s3[57]
  PIN i_s3[58]
    DIRECTION INPUT ;
    USE SIGNAL ;
    PORT
      LAYER M5 ;
        RECT  61.104 0 61.128 0.084 ;
    END
  END i_s3[58]
  PIN i_s3[59]
    DIRECTION INPUT ;
    USE SIGNAL ;
    PORT
      LAYER M5 ;
        RECT  61.2 0 61.224 0.084 ;
    END
  END i_s3[59]
  PIN i_s3[5]
    DIRECTION INPUT ;
    USE SIGNAL ;
    PORT
      LAYER M5 ;
        RECT  52.176 0 52.2 0.084 ;
    END
  END i_s3[5]
  PIN i_s3[60]
    DIRECTION INPUT ;
    USE SIGNAL ;
    PORT
      LAYER M5 ;
        RECT  61.296 0 61.32 0.084 ;
    END
  END i_s3[60]
  PIN i_s3[61]
    DIRECTION INPUT ;
    USE SIGNAL ;
    PORT
      LAYER M5 ;
        RECT  54.48 0 54.504 0.084 ;
    END
  END i_s3[61]
  PIN i_s3[62]
    DIRECTION INPUT ;
    USE SIGNAL ;
    PORT
      LAYER M5 ;
        RECT  54.576 0 54.6 0.084 ;
    END
  END i_s3[62]
  PIN i_s3[63]
    DIRECTION INPUT ;
    USE SIGNAL ;
    PORT
      LAYER M5 ;
        RECT  54.672 0 54.696 0.084 ;
    END
  END i_s3[63]
  PIN i_s3[64]
    DIRECTION INPUT ;
    USE SIGNAL ;
    PORT
      LAYER M5 ;
        RECT  54.768 0 54.792 0.084 ;
    END
  END i_s3[64]
  PIN i_s3[65]
    DIRECTION INPUT ;
    USE SIGNAL ;
    PORT
      LAYER M5 ;
        RECT  54.864 0 54.888 0.084 ;
    END
  END i_s3[65]
  PIN i_s3[66]
    DIRECTION INPUT ;
    USE SIGNAL ;
    PORT
      LAYER M5 ;
        RECT  54.96 0 54.984 0.084 ;
    END
  END i_s3[66]
  PIN i_s3[67]
    DIRECTION INPUT ;
    USE SIGNAL ;
    PORT
      LAYER M5 ;
        RECT  55.056 0 55.08 0.084 ;
    END
  END i_s3[67]
  PIN i_s3[68]
    DIRECTION INPUT ;
    USE SIGNAL ;
    PORT
      LAYER M5 ;
        RECT  55.152 0 55.176 0.084 ;
    END
  END i_s3[68]
  PIN i_s3[69]
    DIRECTION INPUT ;
    USE SIGNAL ;
    PORT
      LAYER M5 ;
        RECT  55.248 0 55.272 0.084 ;
    END
  END i_s3[69]
  PIN i_s3[6]
    DIRECTION INPUT ;
    USE SIGNAL ;
    PORT
      LAYER M5 ;
        RECT  52.272 0 52.296 0.084 ;
    END
  END i_s3[6]
  PIN i_s3[70]
    DIRECTION INPUT ;
    USE SIGNAL ;
    PORT
      LAYER M5 ;
        RECT  55.344 0 55.368 0.084 ;
    END
  END i_s3[70]
  PIN i_s3[71]
    DIRECTION INPUT ;
    USE SIGNAL ;
    PORT
      LAYER M5 ;
        RECT  55.44 0 55.464 0.084 ;
    END
  END i_s3[71]
  PIN i_s3[72]
    DIRECTION INPUT ;
    USE SIGNAL ;
    PORT
      LAYER M5 ;
        RECT  55.536 0 55.56 0.084 ;
    END
  END i_s3[72]
  PIN i_s3[73]
    DIRECTION INPUT ;
    USE SIGNAL ;
    PORT
      LAYER M5 ;
        RECT  55.632 0 55.656 0.084 ;
    END
  END i_s3[73]
  PIN i_s3[74]
    DIRECTION INPUT ;
    USE SIGNAL ;
    PORT
      LAYER M5 ;
        RECT  55.728 0 55.752 0.084 ;
    END
  END i_s3[74]
  PIN i_s3[75]
    DIRECTION INPUT ;
    USE SIGNAL ;
    PORT
      LAYER M5 ;
        RECT  55.824 0 55.848 0.084 ;
    END
  END i_s3[75]
  PIN i_s3[76]
    DIRECTION INPUT ;
    USE SIGNAL ;
    PORT
      LAYER M5 ;
        RECT  55.92 0 55.944 0.084 ;
    END
  END i_s3[76]
  PIN i_s3[77]
    DIRECTION INPUT ;
    USE SIGNAL ;
    PORT
      LAYER M5 ;
        RECT  56.016 0 56.04 0.084 ;
    END
  END i_s3[77]
  PIN i_s3[78]
    DIRECTION INPUT ;
    USE SIGNAL ;
    PORT
      LAYER M5 ;
        RECT  56.112 0 56.136 0.084 ;
    END
  END i_s3[78]
  PIN i_s3[79]
    DIRECTION INPUT ;
    USE SIGNAL ;
    PORT
      LAYER M5 ;
        RECT  56.208 0 56.232 0.084 ;
    END
  END i_s3[79]
  PIN i_s3[7]
    DIRECTION INPUT ;
    USE SIGNAL ;
    PORT
      LAYER M5 ;
        RECT  52.368 0 52.392 0.084 ;
    END
  END i_s3[7]
  PIN i_s3[80]
    DIRECTION INPUT ;
    USE SIGNAL ;
    PORT
      LAYER M5 ;
        RECT  56.304 0 56.328 0.084 ;
    END
  END i_s3[80]
  PIN i_s3[81]
    DIRECTION INPUT ;
    USE SIGNAL ;
    PORT
      LAYER M5 ;
        RECT  56.4 0 56.424 0.084 ;
    END
  END i_s3[81]
  PIN i_s3[82]
    DIRECTION INPUT ;
    USE SIGNAL ;
    PORT
      LAYER M5 ;
        RECT  56.496 0 56.52 0.084 ;
    END
  END i_s3[82]
  PIN i_s3[83]
    DIRECTION INPUT ;
    USE SIGNAL ;
    PORT
      LAYER M5 ;
        RECT  56.592 0 56.616 0.084 ;
    END
  END i_s3[83]
  PIN i_s3[84]
    DIRECTION INPUT ;
    USE SIGNAL ;
    PORT
      LAYER M5 ;
        RECT  56.688 0 56.712 0.084 ;
    END
  END i_s3[84]
  PIN i_s3[85]
    DIRECTION INPUT ;
    USE SIGNAL ;
    PORT
      LAYER M5 ;
        RECT  56.784 0 56.808 0.084 ;
    END
  END i_s3[85]
  PIN i_s3[86]
    DIRECTION INPUT ;
    USE SIGNAL ;
    PORT
      LAYER M5 ;
        RECT  56.88 0 56.904 0.084 ;
    END
  END i_s3[86]
  PIN i_s3[87]
    DIRECTION INPUT ;
    USE SIGNAL ;
    PORT
      LAYER M5 ;
        RECT  56.976 0 57 0.084 ;
    END
  END i_s3[87]
  PIN i_s3[88]
    DIRECTION INPUT ;
    USE SIGNAL ;
    PORT
      LAYER M5 ;
        RECT  57.072 0 57.096 0.084 ;
    END
  END i_s3[88]
  PIN i_s3[89]
    DIRECTION INPUT ;
    USE SIGNAL ;
    PORT
      LAYER M5 ;
        RECT  57.168 0 57.192 0.084 ;
    END
  END i_s3[89]
  PIN i_s3[8]
    DIRECTION INPUT ;
    USE SIGNAL ;
    PORT
      LAYER M5 ;
        RECT  52.464 0 52.488 0.084 ;
    END
  END i_s3[8]
  PIN i_s3[90]
    DIRECTION INPUT ;
    USE SIGNAL ;
    PORT
      LAYER M5 ;
        RECT  57.264 0 57.288 0.084 ;
    END
  END i_s3[90]
  PIN i_s3[91]
    DIRECTION INPUT ;
    USE SIGNAL ;
    PORT
      LAYER M5 ;
        RECT  57.36 0 57.384 0.084 ;
    END
  END i_s3[91]
  PIN i_s3[92]
    DIRECTION INPUT ;
    USE SIGNAL ;
    PORT
      LAYER M5 ;
        RECT  57.456 0 57.48 0.084 ;
    END
  END i_s3[92]
  PIN i_s3[93]
    DIRECTION INPUT ;
    USE SIGNAL ;
    PORT
      LAYER M5 ;
        RECT  48.336 0 48.36 0.084 ;
    END
  END i_s3[93]
  PIN i_s3[94]
    DIRECTION INPUT ;
    USE SIGNAL ;
    PORT
      LAYER M5 ;
        RECT  48.432 0 48.456 0.084 ;
    END
  END i_s3[94]
  PIN i_s3[95]
    DIRECTION INPUT ;
    USE SIGNAL ;
    PORT
      LAYER M5 ;
        RECT  48.528 0 48.552 0.084 ;
    END
  END i_s3[95]
  PIN i_s3[96]
    DIRECTION INPUT ;
    USE SIGNAL ;
    PORT
      LAYER M5 ;
        RECT  48.624 0 48.648 0.084 ;
    END
  END i_s3[96]
  PIN i_s3[97]
    DIRECTION INPUT ;
    USE SIGNAL ;
    PORT
      LAYER M5 ;
        RECT  48.72 0 48.744 0.084 ;
    END
  END i_s3[97]
  PIN i_s3[98]
    DIRECTION INPUT ;
    USE SIGNAL ;
    PORT
      LAYER M5 ;
        RECT  48.816 0 48.84 0.084 ;
    END
  END i_s3[98]
  PIN i_s3[99]
    DIRECTION INPUT ;
    USE SIGNAL ;
    PORT
      LAYER M5 ;
        RECT  48.912 0 48.936 0.084 ;
    END
  END i_s3[99]
  PIN i_s3[9]
    DIRECTION INPUT ;
    USE SIGNAL ;
    PORT
      LAYER M5 ;
        RECT  52.56 0 52.584 0.084 ;
    END
  END i_s3[9]
  PIN i_s3_v
    DIRECTION INPUT ;
    USE SIGNAL ;
    PORT
      LAYER M5 ;
        RECT  29.808 0 29.832 0.084 ;
    END
  END i_s3_v
  PIN i_wbad
    DIRECTION INPUT ;
    USE SIGNAL ;
    PORT
      LAYER M5 ;
        RECT  70.032 77.676 70.056 77.76 ;
    END
  END i_wbad
  PIN i_widle
    DIRECTION INPUT ;
    USE SIGNAL ;
    PORT
      LAYER M5 ;
        RECT  70.128 77.676 70.152 77.76 ;
    END
  END i_widle
  PIN o_act
    DIRECTION OUTPUT ;
    USE SIGNAL ;
    PORT
      LAYER M5 ;
        RECT  70.224 77.676 70.248 77.76 ;
    END
  END o_act
  PIN ret[0]
    DIRECTION OUTPUT ;
    USE SIGNAL ;
    PORT
      LAYER M5 ;
        RECT  29.904 0 29.928 0.084 ;
    END
  END ret[0]
  PIN ret[1]
    DIRECTION OUTPUT ;
    USE SIGNAL ;
    PORT
      LAYER M5 ;
        RECT  30 0 30.024 0.084 ;
    END
  END ret[1]
  PIN ret[2]
    DIRECTION OUTPUT ;
    USE SIGNAL ;
    PORT
      LAYER M5 ;
        RECT  30.096 0 30.12 0.084 ;
    END
  END ret[2]
  PIN rg_gnt
    DIRECTION INPUT ;
    USE SIGNAL ;
    PORT
      LAYER M4 ;
        RECT  0 67.824 0.084 67.848 ;
    END
  END rg_gnt
  PIN rg_req
    DIRECTION OUTPUT ;
    USE SIGNAL ;
    PORT
      LAYER M4 ;
        RECT  0 67.92 0.084 67.944 ;
    END
  END rg_req
  PIN rst_n
    DIRECTION INPUT ;
    USE SIGNAL ;
    PORT
      LAYER M5 ;
        RECT  30.192 0 30.216 0.084 ;
    END
  END rst_n
  PIN wrq[0]
    DIRECTION OUTPUT ;
    USE SIGNAL ;
    PORT
      LAYER M4 ;
        RECT  0 68.016 0.084 68.04 ;
    END
  END wrq[0]
  PIN wrq[100]
    DIRECTION OUTPUT ;
    USE SIGNAL ;
    PORT
      LAYER M4 ;
        RECT  0 71.472 0.084 71.496 ;
    END
  END wrq[100]
  PIN wrq[101]
    DIRECTION OUTPUT ;
    USE SIGNAL ;
    PORT
      LAYER M4 ;
        RECT  0 71.568 0.084 71.592 ;
    END
  END wrq[101]
  PIN wrq[102]
    DIRECTION OUTPUT ;
    USE SIGNAL ;
    PORT
      LAYER M4 ;
        RECT  0 71.664 0.084 71.688 ;
    END
  END wrq[102]
  PIN wrq[103]
    DIRECTION OUTPUT ;
    USE SIGNAL ;
    PORT
      LAYER M4 ;
        RECT  0 71.76 0.084 71.784 ;
    END
  END wrq[103]
  PIN wrq[104]
    DIRECTION OUTPUT ;
    USE SIGNAL ;
    PORT
      LAYER M4 ;
        RECT  0 71.856 0.084 71.88 ;
    END
  END wrq[104]
  PIN wrq[105]
    DIRECTION OUTPUT ;
    USE SIGNAL ;
    PORT
      LAYER M4 ;
        RECT  0 71.952 0.084 71.976 ;
    END
  END wrq[105]
  PIN wrq[106]
    DIRECTION OUTPUT ;
    USE SIGNAL ;
    PORT
      LAYER M4 ;
        RECT  0 72.048 0.084 72.072 ;
    END
  END wrq[106]
  PIN wrq[107]
    DIRECTION OUTPUT ;
    USE SIGNAL ;
    PORT
      LAYER M4 ;
        RECT  0 72.144 0.084 72.168 ;
    END
  END wrq[107]
  PIN wrq[108]
    DIRECTION OUTPUT ;
    USE SIGNAL ;
    PORT
      LAYER M4 ;
        RECT  0 72.24 0.084 72.264 ;
    END
  END wrq[108]
  PIN wrq[109]
    DIRECTION OUTPUT ;
    USE SIGNAL ;
    PORT
      LAYER M4 ;
        RECT  0 72.336 0.084 72.36 ;
    END
  END wrq[109]
  PIN wrq[10]
    DIRECTION OUTPUT ;
    USE SIGNAL ;
    PORT
      LAYER M4 ;
        RECT  0 68.976 0.084 69 ;
    END
  END wrq[10]
  PIN wrq[110]
    DIRECTION OUTPUT ;
    USE SIGNAL ;
    PORT
      LAYER M4 ;
        RECT  0 72.432 0.084 72.456 ;
    END
  END wrq[110]
  PIN wrq[111]
    DIRECTION OUTPUT ;
    USE SIGNAL ;
    PORT
      LAYER M4 ;
        RECT  0 72.528 0.084 72.552 ;
    END
  END wrq[111]
  PIN wrq[112]
    DIRECTION OUTPUT ;
    USE SIGNAL ;
    PORT
      LAYER M4 ;
        RECT  0 72.624 0.084 72.648 ;
    END
  END wrq[112]
  PIN wrq[113]
    DIRECTION OUTPUT ;
    USE SIGNAL ;
    PORT
      LAYER M4 ;
        RECT  0 72.72 0.084 72.744 ;
    END
  END wrq[113]
  PIN wrq[114]
    DIRECTION OUTPUT ;
    USE SIGNAL ;
    PORT
      LAYER M4 ;
        RECT  0 72.816 0.084 72.84 ;
    END
  END wrq[114]
  PIN wrq[115]
    DIRECTION OUTPUT ;
    USE SIGNAL ;
    PORT
      LAYER M4 ;
        RECT  0 72.912 0.084 72.936 ;
    END
  END wrq[115]
  PIN wrq[116]
    DIRECTION OUTPUT ;
    USE SIGNAL ;
    PORT
      LAYER M4 ;
        RECT  0 73.008 0.084 73.032 ;
    END
  END wrq[116]
  PIN wrq[117]
    DIRECTION OUTPUT ;
    USE SIGNAL ;
    PORT
      LAYER M4 ;
        RECT  0 73.104 0.084 73.128 ;
    END
  END wrq[117]
  PIN wrq[118]
    DIRECTION OUTPUT ;
    USE SIGNAL ;
    PORT
      LAYER M4 ;
        RECT  0 73.2 0.084 73.224 ;
    END
  END wrq[118]
  PIN wrq[119]
    DIRECTION OUTPUT ;
    USE SIGNAL ;
    PORT
      LAYER M4 ;
        RECT  0 73.296 0.084 73.32 ;
    END
  END wrq[119]
  PIN wrq[11]
    DIRECTION OUTPUT ;
    USE SIGNAL ;
    PORT
      LAYER M4 ;
        RECT  0 69.072 0.084 69.096 ;
    END
  END wrq[11]
  PIN wrq[120]
    DIRECTION OUTPUT ;
    USE SIGNAL ;
    PORT
      LAYER M4 ;
        RECT  0 73.392 0.084 73.416 ;
    END
  END wrq[120]
  PIN wrq[121]
    DIRECTION OUTPUT ;
    USE SIGNAL ;
    PORT
      LAYER M4 ;
        RECT  0 73.488 0.084 73.512 ;
    END
  END wrq[121]
  PIN wrq[122]
    DIRECTION OUTPUT ;
    USE SIGNAL ;
    PORT
      LAYER M4 ;
        RECT  0 73.584 0.084 73.608 ;
    END
  END wrq[122]
  PIN wrq[123]
    DIRECTION OUTPUT ;
    USE SIGNAL ;
    PORT
      LAYER M4 ;
        RECT  0 73.68 0.084 73.704 ;
    END
  END wrq[123]
  PIN wrq[124]
    DIRECTION OUTPUT ;
    USE SIGNAL ;
    PORT
      LAYER M4 ;
        RECT  0 73.776 0.084 73.8 ;
    END
  END wrq[124]
  PIN wrq[125]
    DIRECTION OUTPUT ;
    USE SIGNAL ;
    PORT
      LAYER M4 ;
        RECT  0 73.872 0.084 73.896 ;
    END
  END wrq[125]
  PIN wrq[126]
    DIRECTION OUTPUT ;
    USE SIGNAL ;
    PORT
      LAYER M4 ;
        RECT  0 76.08 0.084 76.104 ;
    END
  END wrq[126]
  PIN wrq[127]
    DIRECTION OUTPUT ;
    USE SIGNAL ;
    PORT
      LAYER M4 ;
        RECT  0 76.176 0.084 76.2 ;
    END
  END wrq[127]
  PIN wrq[12]
    DIRECTION OUTPUT ;
    USE SIGNAL ;
    PORT
      LAYER M4 ;
        RECT  0 69.168 0.084 69.192 ;
    END
  END wrq[12]
  PIN wrq[13]
    DIRECTION OUTPUT ;
    USE SIGNAL ;
    PORT
      LAYER M4 ;
        RECT  0 69.264 0.084 69.288 ;
    END
  END wrq[13]
  PIN wrq[14]
    DIRECTION OUTPUT ;
    USE SIGNAL ;
    PORT
      LAYER M4 ;
        RECT  0 69.36 0.084 69.384 ;
    END
  END wrq[14]
  PIN wrq[15]
    DIRECTION OUTPUT ;
    USE SIGNAL ;
    PORT
      LAYER M4 ;
        RECT  0 69.456 0.084 69.48 ;
    END
  END wrq[15]
  PIN wrq[16]
    DIRECTION OUTPUT ;
    USE SIGNAL ;
    PORT
      LAYER M4 ;
        RECT  0 69.552 0.084 69.576 ;
    END
  END wrq[16]
  PIN wrq[17]
    DIRECTION OUTPUT ;
    USE SIGNAL ;
    PORT
      LAYER M4 ;
        RECT  0 69.648 0.084 69.672 ;
    END
  END wrq[17]
  PIN wrq[18]
    DIRECTION OUTPUT ;
    USE SIGNAL ;
    PORT
      LAYER M4 ;
        RECT  0 69.744 0.084 69.768 ;
    END
  END wrq[18]
  PIN wrq[19]
    DIRECTION OUTPUT ;
    USE SIGNAL ;
    PORT
      LAYER M4 ;
        RECT  0 69.84 0.084 69.864 ;
    END
  END wrq[19]
  PIN wrq[1]
    DIRECTION OUTPUT ;
    USE SIGNAL ;
    PORT
      LAYER M4 ;
        RECT  0 68.112 0.084 68.136 ;
    END
  END wrq[1]
  PIN wrq[20]
    DIRECTION OUTPUT ;
    USE SIGNAL ;
    PORT
      LAYER M4 ;
        RECT  0 69.936 0.084 69.96 ;
    END
  END wrq[20]
  PIN wrq[21]
    DIRECTION OUTPUT ;
    USE SIGNAL ;
    PORT
      LAYER M4 ;
        RECT  0 70.032 0.084 70.056 ;
    END
  END wrq[21]
  PIN wrq[22]
    DIRECTION OUTPUT ;
    USE SIGNAL ;
    PORT
      LAYER M4 ;
        RECT  0 70.128 0.084 70.152 ;
    END
  END wrq[22]
  PIN wrq[23]
    DIRECTION OUTPUT ;
    USE SIGNAL ;
    PORT
      LAYER M4 ;
        RECT  0 70.224 0.084 70.248 ;
    END
  END wrq[23]
  PIN wrq[24]
    DIRECTION OUTPUT ;
    USE SIGNAL ;
    PORT
      LAYER M4 ;
        RECT  0 70.32 0.084 70.344 ;
    END
  END wrq[24]
  PIN wrq[25]
    DIRECTION OUTPUT ;
    USE SIGNAL ;
    PORT
      LAYER M4 ;
        RECT  0 70.416 0.084 70.44 ;
    END
  END wrq[25]
  PIN wrq[26]
    DIRECTION OUTPUT ;
    USE SIGNAL ;
    PORT
      LAYER M4 ;
        RECT  0 70.512 0.084 70.536 ;
    END
  END wrq[26]
  PIN wrq[27]
    DIRECTION OUTPUT ;
    USE SIGNAL ;
    PORT
      LAYER M4 ;
        RECT  0 70.608 0.084 70.632 ;
    END
  END wrq[27]
  PIN wrq[28]
    DIRECTION OUTPUT ;
    USE SIGNAL ;
    PORT
      LAYER M4 ;
        RECT  0 70.704 0.084 70.728 ;
    END
  END wrq[28]
  PIN wrq[29]
    DIRECTION OUTPUT ;
    USE SIGNAL ;
    PORT
      LAYER M4 ;
        RECT  0 70.8 0.084 70.824 ;
    END
  END wrq[29]
  PIN wrq[2]
    DIRECTION OUTPUT ;
    USE SIGNAL ;
    PORT
      LAYER M4 ;
        RECT  0 68.208 0.084 68.232 ;
    END
  END wrq[2]
  PIN wrq[30]
    DIRECTION OUTPUT ;
    USE SIGNAL ;
    PORT
      LAYER M4 ;
        RECT  0 64.752 0.084 64.776 ;
    END
  END wrq[30]
  PIN wrq[31]
    DIRECTION OUTPUT ;
    USE SIGNAL ;
    PORT
      LAYER M4 ;
        RECT  0 64.848 0.084 64.872 ;
    END
  END wrq[31]
  PIN wrq[32]
    DIRECTION OUTPUT ;
    USE SIGNAL ;
    PORT
      LAYER M4 ;
        RECT  0 64.944 0.084 64.968 ;
    END
  END wrq[32]
  PIN wrq[33]
    DIRECTION OUTPUT ;
    USE SIGNAL ;
    PORT
      LAYER M4 ;
        RECT  0 65.04 0.084 65.064 ;
    END
  END wrq[33]
  PIN wrq[34]
    DIRECTION OUTPUT ;
    USE SIGNAL ;
    PORT
      LAYER M4 ;
        RECT  0 65.136 0.084 65.16 ;
    END
  END wrq[34]
  PIN wrq[35]
    DIRECTION OUTPUT ;
    USE SIGNAL ;
    PORT
      LAYER M4 ;
        RECT  0 65.232 0.084 65.256 ;
    END
  END wrq[35]
  PIN wrq[36]
    DIRECTION OUTPUT ;
    USE SIGNAL ;
    PORT
      LAYER M4 ;
        RECT  0 65.328 0.084 65.352 ;
    END
  END wrq[36]
  PIN wrq[37]
    DIRECTION OUTPUT ;
    USE SIGNAL ;
    PORT
      LAYER M4 ;
        RECT  0 65.424 0.084 65.448 ;
    END
  END wrq[37]
  PIN wrq[38]
    DIRECTION OUTPUT ;
    USE SIGNAL ;
    PORT
      LAYER M4 ;
        RECT  0 65.52 0.084 65.544 ;
    END
  END wrq[38]
  PIN wrq[39]
    DIRECTION OUTPUT ;
    USE SIGNAL ;
    PORT
      LAYER M4 ;
        RECT  0 65.616 0.084 65.64 ;
    END
  END wrq[39]
  PIN wrq[3]
    DIRECTION OUTPUT ;
    USE SIGNAL ;
    PORT
      LAYER M4 ;
        RECT  0 68.304 0.084 68.328 ;
    END
  END wrq[3]
  PIN wrq[40]
    DIRECTION OUTPUT ;
    USE SIGNAL ;
    PORT
      LAYER M4 ;
        RECT  0 65.712 0.084 65.736 ;
    END
  END wrq[40]
  PIN wrq[41]
    DIRECTION OUTPUT ;
    USE SIGNAL ;
    PORT
      LAYER M4 ;
        RECT  0 65.808 0.084 65.832 ;
    END
  END wrq[41]
  PIN wrq[42]
    DIRECTION OUTPUT ;
    USE SIGNAL ;
    PORT
      LAYER M4 ;
        RECT  0 65.904 0.084 65.928 ;
    END
  END wrq[42]
  PIN wrq[43]
    DIRECTION OUTPUT ;
    USE SIGNAL ;
    PORT
      LAYER M4 ;
        RECT  0 66 0.084 66.024 ;
    END
  END wrq[43]
  PIN wrq[44]
    DIRECTION OUTPUT ;
    USE SIGNAL ;
    PORT
      LAYER M4 ;
        RECT  0 66.096 0.084 66.12 ;
    END
  END wrq[44]
  PIN wrq[45]
    DIRECTION OUTPUT ;
    USE SIGNAL ;
    PORT
      LAYER M4 ;
        RECT  0 66.192 0.084 66.216 ;
    END
  END wrq[45]
  PIN wrq[46]
    DIRECTION OUTPUT ;
    USE SIGNAL ;
    PORT
      LAYER M4 ;
        RECT  0 66.288 0.084 66.312 ;
    END
  END wrq[46]
  PIN wrq[47]
    DIRECTION OUTPUT ;
    USE SIGNAL ;
    PORT
      LAYER M4 ;
        RECT  0 66.384 0.084 66.408 ;
    END
  END wrq[47]
  PIN wrq[48]
    DIRECTION OUTPUT ;
    USE SIGNAL ;
    PORT
      LAYER M4 ;
        RECT  0 66.48 0.084 66.504 ;
    END
  END wrq[48]
  PIN wrq[49]
    DIRECTION OUTPUT ;
    USE SIGNAL ;
    PORT
      LAYER M4 ;
        RECT  0 66.576 0.084 66.6 ;
    END
  END wrq[49]
  PIN wrq[4]
    DIRECTION OUTPUT ;
    USE SIGNAL ;
    PORT
      LAYER M4 ;
        RECT  0 68.4 0.084 68.424 ;
    END
  END wrq[4]
  PIN wrq[50]
    DIRECTION OUTPUT ;
    USE SIGNAL ;
    PORT
      LAYER M4 ;
        RECT  0 66.672 0.084 66.696 ;
    END
  END wrq[50]
  PIN wrq[51]
    DIRECTION OUTPUT ;
    USE SIGNAL ;
    PORT
      LAYER M4 ;
        RECT  0 66.768 0.084 66.792 ;
    END
  END wrq[51]
  PIN wrq[52]
    DIRECTION OUTPUT ;
    USE SIGNAL ;
    PORT
      LAYER M4 ;
        RECT  0 66.864 0.084 66.888 ;
    END
  END wrq[52]
  PIN wrq[53]
    DIRECTION OUTPUT ;
    USE SIGNAL ;
    PORT
      LAYER M4 ;
        RECT  0 66.96 0.084 66.984 ;
    END
  END wrq[53]
  PIN wrq[54]
    DIRECTION OUTPUT ;
    USE SIGNAL ;
    PORT
      LAYER M4 ;
        RECT  0 67.056 0.084 67.08 ;
    END
  END wrq[54]
  PIN wrq[55]
    DIRECTION OUTPUT ;
    USE SIGNAL ;
    PORT
      LAYER M4 ;
        RECT  0 67.152 0.084 67.176 ;
    END
  END wrq[55]
  PIN wrq[56]
    DIRECTION OUTPUT ;
    USE SIGNAL ;
    PORT
      LAYER M4 ;
        RECT  0 67.248 0.084 67.272 ;
    END
  END wrq[56]
  PIN wrq[57]
    DIRECTION OUTPUT ;
    USE SIGNAL ;
    PORT
      LAYER M4 ;
        RECT  0 67.344 0.084 67.368 ;
    END
  END wrq[57]
  PIN wrq[58]
    DIRECTION OUTPUT ;
    USE SIGNAL ;
    PORT
      LAYER M4 ;
        RECT  0 67.44 0.084 67.464 ;
    END
  END wrq[58]
  PIN wrq[59]
    DIRECTION OUTPUT ;
    USE SIGNAL ;
    PORT
      LAYER M4 ;
        RECT  0 67.536 0.084 67.56 ;
    END
  END wrq[59]
  PIN wrq[5]
    DIRECTION OUTPUT ;
    USE SIGNAL ;
    PORT
      LAYER M4 ;
        RECT  0 68.496 0.084 68.52 ;
    END
  END wrq[5]
  PIN wrq[60]
    DIRECTION OUTPUT ;
    USE SIGNAL ;
    PORT
      LAYER M4 ;
        RECT  0 67.632 0.084 67.656 ;
    END
  END wrq[60]
  PIN wrq[61]
    DIRECTION OUTPUT ;
    USE SIGNAL ;
    PORT
      LAYER M4 ;
        RECT  0 67.728 0.084 67.752 ;
    END
  END wrq[61]
  PIN wrq[62]
    DIRECTION OUTPUT ;
    USE SIGNAL ;
    PORT
      LAYER M4 ;
        RECT  0 61.68 0.084 61.704 ;
    END
  END wrq[62]
  PIN wrq[63]
    DIRECTION OUTPUT ;
    USE SIGNAL ;
    PORT
      LAYER M4 ;
        RECT  0 61.776 0.084 61.8 ;
    END
  END wrq[63]
  PIN wrq[64]
    DIRECTION OUTPUT ;
    USE SIGNAL ;
    PORT
      LAYER M4 ;
        RECT  0 61.872 0.084 61.896 ;
    END
  END wrq[64]
  PIN wrq[65]
    DIRECTION OUTPUT ;
    USE SIGNAL ;
    PORT
      LAYER M4 ;
        RECT  0 61.968 0.084 61.992 ;
    END
  END wrq[65]
  PIN wrq[66]
    DIRECTION OUTPUT ;
    USE SIGNAL ;
    PORT
      LAYER M4 ;
        RECT  0 62.064 0.084 62.088 ;
    END
  END wrq[66]
  PIN wrq[67]
    DIRECTION OUTPUT ;
    USE SIGNAL ;
    PORT
      LAYER M4 ;
        RECT  0 62.16 0.084 62.184 ;
    END
  END wrq[67]
  PIN wrq[68]
    DIRECTION OUTPUT ;
    USE SIGNAL ;
    PORT
      LAYER M4 ;
        RECT  0 62.256 0.084 62.28 ;
    END
  END wrq[68]
  PIN wrq[69]
    DIRECTION OUTPUT ;
    USE SIGNAL ;
    PORT
      LAYER M4 ;
        RECT  0 62.352 0.084 62.376 ;
    END
  END wrq[69]
  PIN wrq[6]
    DIRECTION OUTPUT ;
    USE SIGNAL ;
    PORT
      LAYER M4 ;
        RECT  0 68.592 0.084 68.616 ;
    END
  END wrq[6]
  PIN wrq[70]
    DIRECTION OUTPUT ;
    USE SIGNAL ;
    PORT
      LAYER M4 ;
        RECT  0 62.448 0.084 62.472 ;
    END
  END wrq[70]
  PIN wrq[71]
    DIRECTION OUTPUT ;
    USE SIGNAL ;
    PORT
      LAYER M4 ;
        RECT  0 62.544 0.084 62.568 ;
    END
  END wrq[71]
  PIN wrq[72]
    DIRECTION OUTPUT ;
    USE SIGNAL ;
    PORT
      LAYER M4 ;
        RECT  0 62.64 0.084 62.664 ;
    END
  END wrq[72]
  PIN wrq[73]
    DIRECTION OUTPUT ;
    USE SIGNAL ;
    PORT
      LAYER M4 ;
        RECT  0 62.736 0.084 62.76 ;
    END
  END wrq[73]
  PIN wrq[74]
    DIRECTION OUTPUT ;
    USE SIGNAL ;
    PORT
      LAYER M4 ;
        RECT  0 62.832 0.084 62.856 ;
    END
  END wrq[74]
  PIN wrq[75]
    DIRECTION OUTPUT ;
    USE SIGNAL ;
    PORT
      LAYER M4 ;
        RECT  0 62.928 0.084 62.952 ;
    END
  END wrq[75]
  PIN wrq[76]
    DIRECTION OUTPUT ;
    USE SIGNAL ;
    PORT
      LAYER M4 ;
        RECT  0 63.024 0.084 63.048 ;
    END
  END wrq[76]
  PIN wrq[77]
    DIRECTION OUTPUT ;
    USE SIGNAL ;
    PORT
      LAYER M4 ;
        RECT  0 63.12 0.084 63.144 ;
    END
  END wrq[77]
  PIN wrq[78]
    DIRECTION OUTPUT ;
    USE SIGNAL ;
    PORT
      LAYER M4 ;
        RECT  0 63.216 0.084 63.24 ;
    END
  END wrq[78]
  PIN wrq[79]
    DIRECTION OUTPUT ;
    USE SIGNAL ;
    PORT
      LAYER M4 ;
        RECT  0 63.312 0.084 63.336 ;
    END
  END wrq[79]
  PIN wrq[7]
    DIRECTION OUTPUT ;
    USE SIGNAL ;
    PORT
      LAYER M4 ;
        RECT  0 68.688 0.084 68.712 ;
    END
  END wrq[7]
  PIN wrq[80]
    DIRECTION OUTPUT ;
    USE SIGNAL ;
    PORT
      LAYER M4 ;
        RECT  0 63.408 0.084 63.432 ;
    END
  END wrq[80]
  PIN wrq[81]
    DIRECTION OUTPUT ;
    USE SIGNAL ;
    PORT
      LAYER M4 ;
        RECT  0 63.504 0.084 63.528 ;
    END
  END wrq[81]
  PIN wrq[82]
    DIRECTION OUTPUT ;
    USE SIGNAL ;
    PORT
      LAYER M4 ;
        RECT  0 63.6 0.084 63.624 ;
    END
  END wrq[82]
  PIN wrq[83]
    DIRECTION OUTPUT ;
    USE SIGNAL ;
    PORT
      LAYER M4 ;
        RECT  0 63.696 0.084 63.72 ;
    END
  END wrq[83]
  PIN wrq[84]
    DIRECTION OUTPUT ;
    USE SIGNAL ;
    PORT
      LAYER M4 ;
        RECT  0 63.792 0.084 63.816 ;
    END
  END wrq[84]
  PIN wrq[85]
    DIRECTION OUTPUT ;
    USE SIGNAL ;
    PORT
      LAYER M4 ;
        RECT  0 63.888 0.084 63.912 ;
    END
  END wrq[85]
  PIN wrq[86]
    DIRECTION OUTPUT ;
    USE SIGNAL ;
    PORT
      LAYER M4 ;
        RECT  0 63.984 0.084 64.008 ;
    END
  END wrq[86]
  PIN wrq[87]
    DIRECTION OUTPUT ;
    USE SIGNAL ;
    PORT
      LAYER M4 ;
        RECT  0 64.08 0.084 64.104 ;
    END
  END wrq[87]
  PIN wrq[88]
    DIRECTION OUTPUT ;
    USE SIGNAL ;
    PORT
      LAYER M4 ;
        RECT  0 64.176 0.084 64.2 ;
    END
  END wrq[88]
  PIN wrq[89]
    DIRECTION OUTPUT ;
    USE SIGNAL ;
    PORT
      LAYER M4 ;
        RECT  0 64.272 0.084 64.296 ;
    END
  END wrq[89]
  PIN wrq[8]
    DIRECTION OUTPUT ;
    USE SIGNAL ;
    PORT
      LAYER M4 ;
        RECT  0 68.784 0.084 68.808 ;
    END
  END wrq[8]
  PIN wrq[90]
    DIRECTION OUTPUT ;
    USE SIGNAL ;
    PORT
      LAYER M4 ;
        RECT  0 64.368 0.084 64.392 ;
    END
  END wrq[90]
  PIN wrq[91]
    DIRECTION OUTPUT ;
    USE SIGNAL ;
    PORT
      LAYER M4 ;
        RECT  0 64.464 0.084 64.488 ;
    END
  END wrq[91]
  PIN wrq[92]
    DIRECTION OUTPUT ;
    USE SIGNAL ;
    PORT
      LAYER M4 ;
        RECT  0 64.56 0.084 64.584 ;
    END
  END wrq[92]
  PIN wrq[93]
    DIRECTION OUTPUT ;
    USE SIGNAL ;
    PORT
      LAYER M4 ;
        RECT  0 64.656 0.084 64.68 ;
    END
  END wrq[93]
  PIN wrq[94]
    DIRECTION OUTPUT ;
    USE SIGNAL ;
    PORT
      LAYER M4 ;
        RECT  0 70.896 0.084 70.92 ;
    END
  END wrq[94]
  PIN wrq[95]
    DIRECTION OUTPUT ;
    USE SIGNAL ;
    PORT
      LAYER M4 ;
        RECT  0 70.992 0.084 71.016 ;
    END
  END wrq[95]
  PIN wrq[96]
    DIRECTION OUTPUT ;
    USE SIGNAL ;
    PORT
      LAYER M4 ;
        RECT  0 71.088 0.084 71.112 ;
    END
  END wrq[96]
  PIN wrq[97]
    DIRECTION OUTPUT ;
    USE SIGNAL ;
    PORT
      LAYER M4 ;
        RECT  0 71.184 0.084 71.208 ;
    END
  END wrq[97]
  PIN wrq[98]
    DIRECTION OUTPUT ;
    USE SIGNAL ;
    PORT
      LAYER M4 ;
        RECT  0 71.28 0.084 71.304 ;
    END
  END wrq[98]
  PIN wrq[99]
    DIRECTION OUTPUT ;
    USE SIGNAL ;
    PORT
      LAYER M4 ;
        RECT  0 71.376 0.084 71.4 ;
    END
  END wrq[99]
  PIN wrq[9]
    DIRECTION OUTPUT ;
    USE SIGNAL ;
    PORT
      LAYER M4 ;
        RECT  0 68.88 0.084 68.904 ;
    END
  END wrq[9]
  PIN wrq_cr[0]
    DIRECTION INPUT ;
    USE SIGNAL ;
    PORT
      LAYER M4 ;
        RECT  0 76.272 0.084 76.296 ;
    END
  END wrq_cr[0]
  PIN wrq_cr[1]
    DIRECTION INPUT ;
    USE SIGNAL ;
    PORT
      LAYER M4 ;
        RECT  0 76.368 0.084 76.392 ;
    END
  END wrq_cr[1]
  PIN wrq_cr[2]
    DIRECTION INPUT ;
    USE SIGNAL ;
    PORT
      LAYER M4 ;
        RECT  0 76.464 0.084 76.488 ;
    END
  END wrq_cr[2]
  PIN wrq_cr[3]
    DIRECTION INPUT ;
    USE SIGNAL ;
    PORT
      LAYER M4 ;
        RECT  0 76.56 0.084 76.584 ;
    END
  END wrq_cr[3]
  PIN wrq_cr[4]
    DIRECTION INPUT ;
    USE SIGNAL ;
    PORT
      LAYER M4 ;
        RECT  0 76.656 0.084 76.68 ;
    END
  END wrq_cr[4]
  PIN wrq_cr[5]
    DIRECTION INPUT ;
    USE SIGNAL ;
    PORT
      LAYER M4 ;
        RECT  0 76.752 0.084 76.776 ;
    END
  END wrq_cr[5]
  PIN wrq_cr[6]
    DIRECTION INPUT ;
    USE SIGNAL ;
    PORT
      LAYER M4 ;
        RECT  0 76.848 0.084 76.872 ;
    END
  END wrq_cr[6]
  PIN wrq_cr[7]
    DIRECTION INPUT ;
    USE SIGNAL ;
    PORT
      LAYER M4 ;
        RECT  0 76.944 0.084 76.968 ;
    END
  END wrq_cr[7]
  PIN VDD
    DIRECTION INOUT ;
    USE POWER ;
    PORT
      LAYER M5 ;
        RECT  83.592 2.151 83.712 75.609 ;
        RECT  78.192 2.151 78.312 75.609 ;
        RECT  72.792 2.151 72.912 75.609 ;
        RECT  67.392 2.151 67.512 75.609 ;
        RECT  61.992 2.151 62.112 75.609 ;
        RECT  56.592 2.151 56.712 75.609 ;
        RECT  51.192 2.151 51.312 75.609 ;
        RECT  45.792 2.151 45.912 75.609 ;
        RECT  40.392 2.151 40.512 75.609 ;
        RECT  34.992 2.151 35.112 75.609 ;
        RECT  29.592 2.151 29.712 75.609 ;
        RECT  24.192 2.151 24.312 75.609 ;
        RECT  18.792 2.151 18.912 75.609 ;
        RECT  13.392 2.151 13.512 75.609 ;
        RECT  7.992 2.151 8.112 75.609 ;
        RECT  2.592 2.151 2.712 75.609 ;
    END
  END VDD
  PIN VSS
    DIRECTION INOUT ;
    USE GROUND ;
    PORT
      LAYER M5 ;
        RECT  83.4 2.137 83.52 75.623 ;
        RECT  78 2.137 78.12 75.623 ;
        RECT  72.6 2.137 72.72 75.623 ;
        RECT  67.2 2.137 67.32 75.623 ;
        RECT  61.8 2.137 61.92 75.623 ;
        RECT  56.4 2.137 56.52 75.623 ;
        RECT  51 2.137 51.12 75.623 ;
        RECT  45.6 2.137 45.72 75.623 ;
        RECT  40.2 2.137 40.32 75.623 ;
        RECT  34.8 2.137 34.92 75.623 ;
        RECT  29.4 2.137 29.52 75.623 ;
        RECT  24 2.137 24.12 75.623 ;
        RECT  18.6 2.137 18.72 75.623 ;
        RECT  13.2 2.137 13.32 75.623 ;
        RECT  7.8 2.137 7.92 75.623 ;
        RECT  2.4 2.137 2.52 75.623 ;
    END
  END VSS
  # OT_OBS_CLOSED layer=M5 d_um=1.536 added=823
  OBS
    LAYER RVTN ;
     RECT  2.16 2.16 84.24 2.295 ;
     RECT  2.16 2.565 84.24 2.835 ;
     RECT  2.16 3.105 84.24 3.375 ;
     RECT  2.16 3.645 84.24 3.915 ;
     RECT  2.16 4.185 84.24 4.455 ;
     RECT  2.16 4.725 84.24 4.995 ;
     RECT  2.16 5.265 84.24 5.535 ;
     RECT  2.16 5.805 84.24 6.075 ;
     RECT  2.16 6.345 84.24 6.615 ;
     RECT  2.16 6.885 84.24 7.155 ;
     RECT  2.16 7.425 84.24 7.695 ;
     RECT  2.16 7.965 84.24 8.235 ;
     RECT  2.16 8.505 84.24 8.775 ;
     RECT  2.16 9.045 84.24 9.315 ;
     RECT  2.16 9.585 84.24 9.855 ;
     RECT  2.16 10.125 84.24 10.395 ;
     RECT  2.16 10.665 84.24 10.935 ;
     RECT  2.16 11.205 84.24 11.475 ;
     RECT  2.16 11.745 84.24 12.015 ;
     RECT  2.16 12.285 84.24 12.555 ;
     RECT  2.16 12.825 84.24 13.095 ;
     RECT  2.16 13.365 84.24 13.635 ;
     RECT  2.16 13.905 84.24 14.175 ;
     RECT  2.16 14.445 84.24 14.715 ;
     RECT  2.16 14.985 84.24 15.255 ;
     RECT  2.16 15.525 84.24 15.795 ;
     RECT  2.16 16.065 84.24 16.335 ;
     RECT  2.16 16.605 84.24 16.875 ;
     RECT  2.16 17.145 84.24 17.415 ;
     RECT  2.16 17.685 84.24 17.955 ;
     RECT  2.16 18.225 84.24 18.495 ;
     RECT  2.16 18.765 84.24 19.035 ;
     RECT  2.16 19.305 84.24 19.575 ;
     RECT  2.16 19.845 84.24 20.115 ;
     RECT  2.16 20.385 84.24 20.655 ;
     RECT  2.16 20.925 84.24 21.195 ;
     RECT  2.16 21.465 84.24 21.735 ;
     RECT  2.16 22.005 84.24 22.275 ;
     RECT  2.16 22.545 84.24 22.815 ;
     RECT  2.16 23.085 84.24 23.355 ;
     RECT  2.16 23.625 84.24 23.895 ;
     RECT  2.16 24.165 84.24 24.435 ;
     RECT  2.16 24.705 84.24 24.975 ;
     RECT  2.16 25.245 84.24 25.515 ;
     RECT  2.16 25.785 84.24 26.055 ;
     RECT  2.16 26.325 84.24 26.595 ;
     RECT  2.16 26.865 84.24 27.135 ;
     RECT  2.16 27.405 84.24 27.675 ;
     RECT  2.16 27.945 84.24 28.215 ;
     RECT  2.16 28.485 84.24 28.755 ;
     RECT  2.16 29.025 84.24 29.295 ;
     RECT  2.16 29.565 84.24 29.835 ;
     RECT  2.16 30.105 84.24 30.375 ;
     RECT  2.16 30.645 84.24 30.915 ;
     RECT  2.16 31.185 84.24 31.455 ;
     RECT  2.16 31.725 84.24 31.995 ;
     RECT  2.16 32.265 84.24 32.535 ;
     RECT  2.16 32.805 84.24 33.075 ;
     RECT  2.16 33.345 84.24 33.615 ;
     RECT  2.16 33.885 84.24 34.155 ;
     RECT  2.16 34.425 84.24 34.695 ;
     RECT  2.16 34.965 84.24 35.235 ;
     RECT  2.16 35.505 84.24 35.775 ;
     RECT  2.16 36.045 84.24 36.315 ;
     RECT  2.16 36.585 84.24 36.855 ;
     RECT  2.16 37.125 84.24 37.395 ;
     RECT  2.16 37.665 84.24 37.935 ;
     RECT  2.16 38.205 84.24 38.475 ;
     RECT  2.16 38.745 84.24 39.015 ;
     RECT  2.16 39.285 84.24 39.555 ;
     RECT  2.16 39.825 84.24 40.095 ;
     RECT  2.16 40.365 84.24 40.635 ;
     RECT  2.16 40.905 84.24 41.175 ;
     RECT  2.16 41.445 84.24 41.715 ;
     RECT  2.16 41.985 84.24 42.255 ;
     RECT  2.16 42.525 84.24 42.795 ;
     RECT  2.16 43.065 84.24 43.335 ;
     RECT  2.16 43.605 84.24 43.875 ;
     RECT  2.16 44.145 84.24 44.415 ;
     RECT  2.16 44.685 84.24 44.955 ;
     RECT  2.16 45.225 84.24 45.495 ;
     RECT  2.16 45.765 84.24 46.035 ;
     RECT  2.16 46.305 84.24 46.575 ;
     RECT  2.16 46.845 84.24 47.115 ;
     RECT  2.16 47.385 84.24 47.655 ;
     RECT  2.16 47.925 84.24 48.195 ;
     RECT  2.16 48.465 84.24 48.735 ;
     RECT  2.16 49.005 84.24 49.275 ;
     RECT  2.16 49.545 84.24 49.815 ;
     RECT  2.16 50.085 84.24 50.355 ;
     RECT  2.16 50.625 84.24 50.895 ;
     RECT  2.16 51.165 84.24 51.435 ;
     RECT  2.16 51.705 84.24 51.975 ;
     RECT  2.16 52.245 84.24 52.515 ;
     RECT  2.16 52.785 84.24 53.055 ;
     RECT  2.16 53.325 84.24 53.595 ;
     RECT  2.16 53.865 84.24 54.135 ;
     RECT  2.16 54.405 84.24 54.675 ;
     RECT  2.16 54.945 84.24 55.215 ;
     RECT  2.16 55.485 84.24 55.755 ;
     RECT  2.16 56.025 84.24 56.295 ;
     RECT  2.16 56.565 84.24 56.835 ;
     RECT  2.16 57.105 84.24 57.375 ;
     RECT  2.16 57.645 84.24 57.915 ;
     RECT  2.16 58.185 84.24 58.455 ;
     RECT  2.16 58.725 84.24 58.995 ;
     RECT  2.16 59.265 84.24 59.535 ;
     RECT  2.16 59.805 84.24 60.075 ;
     RECT  2.16 60.345 84.24 60.615 ;
     RECT  2.16 60.885 84.24 61.155 ;
     RECT  2.16 61.425 84.24 61.695 ;
     RECT  2.16 61.965 84.24 62.235 ;
     RECT  2.16 62.505 84.24 62.775 ;
     RECT  2.16 63.045 84.24 63.315 ;
     RECT  2.16 63.585 84.24 63.855 ;
     RECT  2.16 64.125 84.24 64.395 ;
     RECT  2.16 64.665 84.24 64.935 ;
     RECT  2.16 65.205 84.24 65.475 ;
     RECT  2.16 65.745 84.24 66.015 ;
     RECT  2.16 66.285 84.24 66.555 ;
     RECT  2.16 66.825 84.24 67.095 ;
     RECT  2.16 67.365 84.24 67.635 ;
     RECT  2.16 67.905 84.24 68.175 ;
     RECT  2.16 68.445 84.24 68.715 ;
     RECT  2.16 68.985 84.24 69.255 ;
     RECT  2.16 69.525 84.24 69.795 ;
     RECT  2.16 70.065 84.24 70.335 ;
     RECT  2.16 70.605 84.24 70.875 ;
     RECT  2.16 71.145 84.24 71.415 ;
     RECT  2.16 71.685 84.24 71.955 ;
     RECT  2.16 72.225 84.24 72.495 ;
     RECT  2.16 72.765 84.24 73.035 ;
     RECT  2.16 73.305 84.24 73.575 ;
     RECT  2.16 73.845 84.24 74.115 ;
     RECT  2.16 74.385 84.24 74.655 ;
     RECT  2.16 74.925 84.24 75.195 ;
     RECT  2.16 75.465 84.24 75.6 ;
    LAYER RVTP ;
     RECT  2.16 2.295 84.24 2.565 ;
     RECT  2.16 2.835 84.24 3.105 ;
     RECT  2.16 3.375 84.24 3.645 ;
     RECT  2.16 3.915 84.24 4.185 ;
     RECT  2.16 4.455 84.24 4.725 ;
     RECT  2.16 4.995 84.24 5.265 ;
     RECT  2.16 5.535 84.24 5.805 ;
     RECT  2.16 6.075 84.24 6.345 ;
     RECT  2.16 6.615 84.24 6.885 ;
     RECT  2.16 7.155 84.24 7.425 ;
     RECT  2.16 7.695 84.24 7.965 ;
     RECT  2.16 8.235 84.24 8.505 ;
     RECT  2.16 8.775 84.24 9.045 ;
     RECT  2.16 9.315 84.24 9.585 ;
     RECT  2.16 9.855 84.24 10.125 ;
     RECT  2.16 10.395 84.24 10.665 ;
     RECT  2.16 10.935 84.24 11.205 ;
     RECT  2.16 11.475 84.24 11.745 ;
     RECT  2.16 12.015 84.24 12.285 ;
     RECT  2.16 12.555 84.24 12.825 ;
     RECT  2.16 13.095 84.24 13.365 ;
     RECT  2.16 13.635 84.24 13.905 ;
     RECT  2.16 14.175 84.24 14.445 ;
     RECT  2.16 14.715 84.24 14.985 ;
     RECT  2.16 15.255 84.24 15.525 ;
     RECT  2.16 15.795 84.24 16.065 ;
     RECT  2.16 16.335 84.24 16.605 ;
     RECT  2.16 16.875 84.24 17.145 ;
     RECT  2.16 17.415 84.24 17.685 ;
     RECT  2.16 17.955 84.24 18.225 ;
     RECT  2.16 18.495 84.24 18.765 ;
     RECT  2.16 19.035 84.24 19.305 ;
     RECT  2.16 19.575 84.24 19.845 ;
     RECT  2.16 20.115 84.24 20.385 ;
     RECT  2.16 20.655 84.24 20.925 ;
     RECT  2.16 21.195 84.24 21.465 ;
     RECT  2.16 21.735 84.24 22.005 ;
     RECT  2.16 22.275 84.24 22.545 ;
     RECT  2.16 22.815 84.24 23.085 ;
     RECT  2.16 23.355 84.24 23.625 ;
     RECT  2.16 23.895 84.24 24.165 ;
     RECT  2.16 24.435 84.24 24.705 ;
     RECT  2.16 24.975 84.24 25.245 ;
     RECT  2.16 25.515 84.24 25.785 ;
     RECT  2.16 26.055 84.24 26.325 ;
     RECT  2.16 26.595 84.24 26.865 ;
     RECT  2.16 27.135 84.24 27.405 ;
     RECT  2.16 27.675 84.24 27.945 ;
     RECT  2.16 28.215 84.24 28.485 ;
     RECT  2.16 28.755 84.24 29.025 ;
     RECT  2.16 29.295 84.24 29.565 ;
     RECT  2.16 29.835 84.24 30.105 ;
     RECT  2.16 30.375 84.24 30.645 ;
     RECT  2.16 30.915 84.24 31.185 ;
     RECT  2.16 31.455 84.24 31.725 ;
     RECT  2.16 31.995 84.24 32.265 ;
     RECT  2.16 32.535 84.24 32.805 ;
     RECT  2.16 33.075 84.24 33.345 ;
     RECT  2.16 33.615 84.24 33.885 ;
     RECT  2.16 34.155 84.24 34.425 ;
     RECT  2.16 34.695 84.24 34.965 ;
     RECT  2.16 35.235 84.24 35.505 ;
     RECT  2.16 35.775 84.24 36.045 ;
     RECT  2.16 36.315 84.24 36.585 ;
     RECT  2.16 36.855 84.24 37.125 ;
     RECT  2.16 37.395 84.24 37.665 ;
     RECT  2.16 37.935 84.24 38.205 ;
     RECT  2.16 38.475 84.24 38.745 ;
     RECT  2.16 39.015 84.24 39.285 ;
     RECT  2.16 39.555 84.24 39.825 ;
     RECT  2.16 40.095 84.24 40.365 ;
     RECT  2.16 40.635 84.24 40.905 ;
     RECT  2.16 41.175 84.24 41.445 ;
     RECT  2.16 41.715 84.24 41.985 ;
     RECT  2.16 42.255 84.24 42.525 ;
     RECT  2.16 42.795 84.24 43.065 ;
     RECT  2.16 43.335 84.24 43.605 ;
     RECT  2.16 43.875 84.24 44.145 ;
     RECT  2.16 44.415 84.24 44.685 ;
     RECT  2.16 44.955 84.24 45.225 ;
     RECT  2.16 45.495 84.24 45.765 ;
     RECT  2.16 46.035 84.24 46.305 ;
     RECT  2.16 46.575 84.24 46.845 ;
     RECT  2.16 47.115 84.24 47.385 ;
     RECT  2.16 47.655 84.24 47.925 ;
     RECT  2.16 48.195 84.24 48.465 ;
     RECT  2.16 48.735 84.24 49.005 ;
     RECT  2.16 49.275 84.24 49.545 ;
     RECT  2.16 49.815 84.24 50.085 ;
     RECT  2.16 50.355 84.24 50.625 ;
     RECT  2.16 50.895 84.24 51.165 ;
     RECT  2.16 51.435 84.24 51.705 ;
     RECT  2.16 51.975 84.24 52.245 ;
     RECT  2.16 52.515 84.24 52.785 ;
     RECT  2.16 53.055 84.24 53.325 ;
     RECT  2.16 53.595 84.24 53.865 ;
     RECT  2.16 54.135 84.24 54.405 ;
     RECT  2.16 54.675 84.24 54.945 ;
     RECT  2.16 55.215 84.24 55.485 ;
     RECT  2.16 55.755 84.24 56.025 ;
     RECT  2.16 56.295 84.24 56.565 ;
     RECT  2.16 56.835 84.24 57.105 ;
     RECT  2.16 57.375 84.24 57.645 ;
     RECT  2.16 57.915 84.24 58.185 ;
     RECT  2.16 58.455 84.24 58.725 ;
     RECT  2.16 58.995 84.24 59.265 ;
     RECT  2.16 59.535 84.24 59.805 ;
     RECT  2.16 60.075 84.24 60.345 ;
     RECT  2.16 60.615 84.24 60.885 ;
     RECT  2.16 61.155 84.24 61.425 ;
     RECT  2.16 61.695 84.24 61.965 ;
     RECT  2.16 62.235 84.24 62.505 ;
     RECT  2.16 62.775 84.24 63.045 ;
     RECT  2.16 63.315 84.24 63.585 ;
     RECT  2.16 63.855 84.24 64.125 ;
     RECT  2.16 64.395 84.24 64.665 ;
     RECT  2.16 64.935 84.24 65.205 ;
     RECT  2.16 65.475 84.24 65.745 ;
     RECT  2.16 66.015 84.24 66.285 ;
     RECT  2.16 66.555 84.24 66.825 ;
     RECT  2.16 67.095 84.24 67.365 ;
     RECT  2.16 67.635 84.24 67.905 ;
     RECT  2.16 68.175 84.24 68.445 ;
     RECT  2.16 68.715 84.24 68.985 ;
     RECT  2.16 69.255 84.24 69.525 ;
     RECT  2.16 69.795 84.24 70.065 ;
     RECT  2.16 70.335 84.24 70.605 ;
     RECT  2.16 70.875 84.24 71.145 ;
     RECT  2.16 71.415 84.24 71.685 ;
     RECT  2.16 71.955 84.24 72.225 ;
     RECT  2.16 72.495 84.24 72.765 ;
     RECT  2.16 73.035 84.24 73.305 ;
     RECT  2.16 73.575 84.24 73.845 ;
     RECT  2.16 74.115 84.24 74.385 ;
     RECT  2.16 74.655 84.24 74.925 ;
     RECT  2.16 75.195 84.24 75.465 ;
    LAYER M1 ;
     RECT  2.16 2.151 84.24 75.609 ;
    LAYER M2 ;
     RECT  0.031 65.988 0.067 66.006 ;
     RECT  0.067 62.514 0.103 62.532 ;
     RECT  0.067 65.682 0.103 66.006 ;
     RECT  0.031 74.124 0.103 74.142 ;
     RECT  0.031 76.176 0.103 76.194 ;
     RECT  0.031 68.994 0.131 69.012 ;
     RECT  0.103 75.78 0.131 76.194 ;
     RECT  0.103 62.514 0.139 63.144 ;
     RECT  0.131 75.78 0.139 75.798 ;
     RECT  0.103 65.682 0.167 66.474 ;
     RECT  0.139 64.674 0.175 64.692 ;
     RECT  0.139 62.136 0.211 63.144 ;
     RECT  0.175 64.251 0.211 64.854 ;
     RECT  0.175 61.236 0.283 61.254 ;
     RECT  0.211 62.136 0.283 65.034 ;
     RECT  0.283 61.236 0.311 65.034 ;
     RECT  0.167 65.916 0.499 66.474 ;
     RECT  0.103 67.221 0.499 67.239 ;
     RECT  0.463 68.076 0.499 68.094 ;
     RECT  0.463 71.856 0.499 71.874 ;
     RECT  0.103 73.512 0.499 74.142 ;
     RECT  0.499 69.156 0.535 69.174 ;
     RECT  0.499 71.586 0.535 71.874 ;
     RECT  0.031 58.626 0.823 58.644 ;
     RECT  0.823 58.626 0.895 59.184 ;
     RECT  0.859 57.276 0.931 57.294 ;
     RECT  0.211 60.354 1.039 60.372 ;
     RECT  0.311 61.236 1.039 64.854 ;
     RECT  1.039 60.354 1.111 64.854 ;
     RECT  0.499 65.916 1.111 68.094 ;
     RECT  0.895 58.536 1.399 59.184 ;
     RECT  1.111 60.354 1.399 68.094 ;
     RECT  0.499 72.774 1.399 74.142 ;
     RECT  1.399 58.536 1.435 68.094 ;
     RECT  0.535 69.156 1.435 69.984 ;
     RECT  0.931 57.006 1.471 57.294 ;
     RECT  1.435 58.536 1.975 69.984 ;
     RECT  1.471 57.006 2.16 57.474 ;
     RECT  1.975 58.464 2.16 69.984 ;
     RECT  0.535 71.046 2.16 71.874 ;
     RECT  1.399 72.774 2.16 74.574 ;
     RECT  0.139 75.51 2.16 75.798 ;
     RECT  2.16 2.151 2.291 75.798 ;
     RECT  2.291 2.151 4.135 75.609 ;
     RECT  4.135 2.151 7.367 75.798 ;
     RECT  7.367 2.151 8.447 75.726 ;
     RECT  8.447 2.151 11.767 75.609 ;
     RECT  11.767 2.151 12.127 75.654 ;
     RECT  12.127 2.106 12.695 75.654 ;
     RECT  12.695 2.106 13.127 75.609 ;
     RECT  13.127 2.151 27.931 75.609 ;
     RECT  27.931 2.106 30.335 75.609 ;
     RECT  30.335 2.151 54.211 75.609 ;
     RECT  54.211 2.106 55.283 75.609 ;
     RECT  55.283 2.151 72.499 75.609 ;
     RECT  72.499 2.106 72.779 75.609 ;
     RECT  72.779 2.151 78.007 75.609 ;
     RECT  78.007 2.151 78.359 75.69 ;
     RECT  78.359 2.151 84.24 75.609 ;
    LAYER M3 ;
     RECT  13.716 0.091 13.734 0.139 ;
     RECT  48.564 0.091 48.582 0.139 ;
     RECT  49.86 0.091 50.202 0.139 ;
     RECT  52.056 0.091 52.074 0.139 ;
     RECT  54.936 0.091 54.954 0.139 ;
     RECT  55.836 0.091 55.854 0.139 ;
     RECT  58.644 0.091 58.662 0.139 ;
     RECT  59.436 0.091 59.454 0.139 ;
     RECT  15.768 0.091 15.966 0.187 ;
     RECT  48.564 0.139 48.834 0.187 ;
     RECT  58.644 0.139 59.454 0.187 ;
     RECT  51.372 0.139 52.074 0.365 ;
     RECT  13.572 0.139 13.734 0.427 ;
     RECT  49.644 0.139 50.346 0.475 ;
     RECT  12.852 0.427 13.734 0.523 ;
     RECT  15.732 0.187 15.966 0.523 ;
     RECT  48.348 0.187 48.834 0.523 ;
     RECT  54.936 0.139 56.214 0.523 ;
     RECT  58.608 0.187 59.454 0.523 ;
     RECT  60.408 0.091 60.426 0.523 ;
     RECT  12.816 0.523 13.734 0.571 ;
     RECT  15.732 0.523 16.038 0.571 ;
     RECT  17.892 0.091 17.91 0.571 ;
     RECT  29.808 0.091 30.078 0.571 ;
     RECT  48.348 0.523 48.87 0.571 ;
     RECT  53.028 0.091 53.334 0.571 ;
     RECT  54.468 0.523 56.214 0.571 ;
     RECT  14.976 0.139 14.994 1.147 ;
     RECT  15.732 0.571 18.306 1.147 ;
     RECT  51.876 0.365 52.074 1.147 ;
     RECT  53.028 0.571 56.214 1.147 ;
     RECT  12.816 0.571 13.77 1.723 ;
     RECT  14.976 1.147 18.306 1.723 ;
     RECT  29.772 0.571 30.078 1.723 ;
     RECT  48.132 0.571 48.87 1.723 ;
     RECT  49.644 0.475 50.598 1.723 ;
     RECT  51.876 1.147 56.214 1.723 ;
     RECT  57.132 0.523 57.15 1.723 ;
     RECT  58.428 0.523 60.426 1.723 ;
     RECT  51.696 1.723 56.25 1.771 ;
     RECT  57.06 1.723 57.438 1.771 ;
     RECT  29.772 1.723 30.15 1.819 ;
     RECT  12.816 1.723 19.278 2.101 ;
     RECT  29.772 1.819 30.186 2.101 ;
     RECT  48.132 1.723 50.85 2.143 ;
     RECT  51.696 1.771 57.438 2.143 ;
     RECT  58.392 1.723 61.218 2.143 ;
     RECT  12.132 2.101 19.278 2.191 ;
     RECT  10.98 2.191 10.998 2.227 ;
     RECT  12.132 2.191 19.53 2.227 ;
     RECT  24.015 2.143 24.105 2.227 ;
     RECT  27.936 2.101 27.954 2.227 ;
     RECT  29.124 2.101 30.33 2.227 ;
     RECT  40.215 2.143 40.305 2.227 ;
     RECT  67.215 2.143 67.305 2.227 ;
     RECT  69.012 2.191 69.03 2.227 ;
     RECT  77.256 2.191 77.274 2.227 ;
     RECT  9.72 2.191 9.738 2.251 ;
     RECT  21.312 2.191 21.33 2.251 ;
     RECT  69.012 2.227 69.318 2.251 ;
     RECT  24.015 2.227 24.786 2.263 ;
     RECT  27.936 2.227 30.33 2.263 ;
     RECT  31.14 2.191 31.374 2.263 ;
     RECT  43.92 2.191 43.938 2.263 ;
     RECT  47.052 2.227 47.07 2.263 ;
     RECT  48.132 2.143 57.438 2.263 ;
     RECT  58.392 2.143 61.905 2.263 ;
     RECT  63.576 2.251 63.594 2.263 ;
     RECT  78.015 2.143 78.105 2.263 ;
     RECT  7.815 2.143 7.905 2.299 ;
     RECT  21.312 2.251 21.366 2.299 ;
     RECT  42.768 2.227 42.786 2.299 ;
     RECT  43.92 2.263 44.586 2.299 ;
     RECT  63.252 2.263 63.594 2.299 ;
     RECT  70.236 2.191 70.254 2.299 ;
     RECT  72.504 2.101 72.774 2.299 ;
     RECT  10.512 2.227 10.998 2.335 ;
     RECT  21.312 2.299 21.762 2.335 ;
     RECT  25.848 2.191 25.866 2.335 ;
     RECT  32.832 2.263 33.138 2.335 ;
     RECT  34.815 2.143 34.905 2.335 ;
     RECT  39.492 2.227 40.305 2.335 ;
     RECT  41.04 2.191 41.058 2.335 ;
     RECT  42.696 2.299 44.586 2.335 ;
     RECT  48.132 2.263 61.974 2.335 ;
     RECT  64.98 2.251 64.998 2.335 ;
     RECT  68.76 2.251 69.318 2.335 ;
     RECT  70.2 2.299 70.29 2.335 ;
     RECT  72.468 2.299 72.774 2.335 ;
     RECT  6.948 2.227 6.966 2.371 ;
     RECT  7.815 2.299 8.406 2.371 ;
     RECT  9.252 2.251 9.738 2.371 ;
     RECT  10.512 2.335 11.322 2.371 ;
     RECT  12.132 2.227 20.574 2.371 ;
     RECT  21.312 2.335 22.266 2.371 ;
     RECT  24.015 2.263 24.93 2.371 ;
     RECT  27.72 2.263 30.33 2.371 ;
     RECT  31.14 2.263 31.626 2.371 ;
     RECT  47.052 2.263 47.394 2.371 ;
     RECT  48.132 2.335 62.19 2.371 ;
     RECT  63.252 2.299 63.702 2.371 ;
     RECT  67.212 2.227 67.305 2.371 ;
     RECT  68.76 2.335 70.434 2.371 ;
     RECT  72.432 2.335 72.774 2.371 ;
     RECT  74.88 2.335 74.898 2.371 ;
     RECT  77.148 2.227 77.274 2.371 ;
     RECT  78.015 2.263 78.822 2.371 ;
     RECT  2.415 2.143 2.505 2.413 ;
     RECT  34.128 2.335 34.905 2.413 ;
     RECT  45.615 2.143 45.705 2.413 ;
     RECT  83.415 2.143 83.505 2.413 ;
     RECT  5.94 2.299 5.958 2.461 ;
     RECT  32.508 2.335 33.138 2.461 ;
     RECT  38.916 2.335 44.586 2.461 ;
     RECT  47.052 2.371 62.19 2.461 ;
     RECT  66.276 2.335 66.294 2.461 ;
     RECT  67.212 2.371 70.434 2.461 ;
     RECT  71.604 2.251 71.622 2.461 ;
     RECT  72.432 2.371 73.314 2.461 ;
     RECT  77.148 2.371 79.434 2.461 ;
     RECT  38.772 2.461 44.586 2.525 ;
     RECT  25.74 2.335 25.866 2.533 ;
     RECT  71.532 2.461 71.622 2.533 ;
     RECT  72.432 2.461 73.386 2.533 ;
     RECT  76.68 2.461 79.434 2.533 ;
     RECT  6.948 2.371 8.406 2.569 ;
     RECT  9.216 2.371 22.266 2.569 ;
     RECT  23.04 2.299 23.058 2.569 ;
     RECT  23.832 2.371 24.93 2.569 ;
     RECT  25.74 2.533 25.974 2.569 ;
     RECT  32.508 2.461 33.21 2.569 ;
     RECT  34.128 2.413 35.097 2.569 ;
     RECT  76.32 2.533 79.434 2.569 ;
     RECT  5.94 2.461 6.102 2.605 ;
     RECT  6.948 2.569 22.266 2.605 ;
     RECT  25.74 2.569 26.334 2.605 ;
     RECT  47.052 2.461 62.262 2.605 ;
     RECT  63.252 2.371 63.774 2.605 ;
     RECT  64.98 2.335 65.214 2.605 ;
     RECT  66.276 2.461 70.434 2.605 ;
     RECT  71.532 2.533 73.386 2.605 ;
     RECT  74.772 2.371 74.97 2.605 ;
     RECT  4.32 2.605 4.338 2.641 ;
     RECT  6.84 2.605 22.266 2.641 ;
     RECT  23.04 2.569 24.93 2.641 ;
     RECT  25.74 2.605 26.37 2.641 ;
     RECT  27.72 2.371 31.626 2.641 ;
     RECT  39.708 2.525 44.586 2.641 ;
     RECT  45.615 2.413 45.897 2.641 ;
     RECT  47.052 2.605 65.214 2.641 ;
     RECT  66.024 2.605 70.434 2.641 ;
     RECT  71.388 2.605 73.386 2.641 ;
     RECT  76.176 2.569 79.434 2.641 ;
     RECT  6.84 2.641 26.37 2.731 ;
     RECT  27.18 2.641 31.626 2.731 ;
     RECT  32.508 2.569 35.097 2.731 ;
     RECT  39.708 2.641 44.766 2.731 ;
     RECT  74.412 2.605 74.97 2.731 ;
     RECT  75.78 2.641 79.434 2.731 ;
     RECT  2.415 2.413 2.697 2.767 ;
     RECT  5.688 2.605 6.102 2.803 ;
     RECT  6.84 2.731 35.097 2.803 ;
     RECT  39.708 2.731 44.874 2.803 ;
     RECT  45.615 2.641 70.47 2.803 ;
     RECT  71.28 2.641 73.386 2.827 ;
     RECT  74.124 2.731 79.434 2.827 ;
     RECT  5.4 2.803 35.097 2.839 ;
     RECT  2.415 2.767 3.402 2.911 ;
     RECT  4.248 2.641 4.338 2.911 ;
     RECT  39.708 2.803 70.47 3.073 ;
     RECT  2.415 2.911 4.338 3.109 ;
     RECT  39.708 3.073 70.542 3.145 ;
     RECT  71.28 2.827 79.434 3.145 ;
     RECT  37.692 2.911 37.71 3.181 ;
     RECT  2.415 3.109 4.41 3.271 ;
     RECT  5.328 2.839 35.097 3.271 ;
     RECT  39.708 3.145 79.434 3.271 ;
     RECT  2.415 3.271 4.446 3.343 ;
     RECT  5.256 3.271 35.226 3.343 ;
     RECT  36.72 3.181 37.71 3.379 ;
     RECT  38.736 3.307 38.898 3.379 ;
     RECT  2.415 3.343 35.226 3.415 ;
     RECT  36.72 3.379 38.97 3.415 ;
     RECT  36.684 3.415 38.97 3.451 ;
     RECT  39.708 3.271 79.866 3.451 ;
     RECT  36.504 3.451 38.97 3.541 ;
     RECT  39.708 3.451 79.974 3.541 ;
     RECT  36.504 3.541 79.974 3.569 ;
     RECT  2.415 3.415 35.55 3.643 ;
     RECT  36.504 3.569 79.83 3.643 ;
     RECT  2.415 3.643 79.83 4.145 ;
     RECT  80.748 3.721 80.766 5.035 ;
     RECT  2.415 4.145 73.386 5.071 ;
     RECT  74.124 4.145 79.83 5.071 ;
     RECT  80.748 5.035 80.982 5.071 ;
     RECT  2.376 5.071 73.386 5.227 ;
     RECT  74.124 5.071 80.982 5.227 ;
     RECT  2.376 5.227 80.982 5.233 ;
     RECT  81.72 4.729 81.738 5.233 ;
     RECT  2.376 5.233 81.774 5.729 ;
     RECT  2.376 5.729 81.738 7.321 ;
     RECT  2.376 7.321 82.098 7.421 ;
     RECT  2.415 7.421 82.098 7.501 ;
     RECT  2.415 7.501 82.674 7.655 ;
     RECT  2.415 7.655 82.026 8.545 ;
     RECT  2.415 8.545 82.134 8.815 ;
     RECT  83.415 2.413 83.697 8.851 ;
     RECT  2.415 8.815 82.386 8.941 ;
     RECT  83.34 8.851 83.697 8.941 ;
     RECT  2.415 8.941 83.697 10.085 ;
     RECT  2.415 10.085 82.674 10.939 ;
     RECT  83.415 10.085 83.697 10.939 ;
     RECT  2.415 10.939 83.697 11.821 ;
     RECT  2.376 11.821 83.697 12.055 ;
     RECT  2.376 12.055 83.934 12.091 ;
     RECT  2.34 12.091 83.934 12.631 ;
     RECT  2.34 12.631 84.114 13.091 ;
     RECT  2.34 13.091 84.006 13.973 ;
     RECT  2.34 13.973 83.697 15.061 ;
     RECT  2.304 15.061 83.697 16.835 ;
     RECT  81.468 16.835 83.697 17.221 ;
     RECT  81.468 17.221 84.006 17.483 ;
     RECT  2.304 16.835 80.694 17.563 ;
     RECT  2.304 17.563 80.73 17.581 ;
     RECT  81.468 17.483 83.697 17.581 ;
     RECT  2.304 17.581 83.697 18.661 ;
     RECT  2.304 18.661 83.826 19.651 ;
     RECT  2.304 19.651 84.114 19.913 ;
     RECT  2.304 19.913 83.826 20.821 ;
     RECT  2.304 20.821 84.042 21.389 ;
     RECT  2.304 21.389 83.898 21.425 ;
     RECT  2.304 21.425 83.697 22.981 ;
     RECT  2.268 22.981 83.697 23.423 ;
     RECT  2.304 23.423 83.697 23.971 ;
     RECT  2.304 23.971 83.934 24.161 ;
     RECT  2.304 24.161 83.697 26.249 ;
     RECT  2.34 26.249 83.697 28.831 ;
     RECT  2.34 28.831 83.898 29.065 ;
     RECT  2.34 29.065 84.006 29.219 ;
     RECT  2.34 29.219 83.898 29.255 ;
     RECT  2.34 29.255 83.697 30.451 ;
     RECT  2.34 30.451 83.826 30.721 ;
     RECT  2.34 30.721 83.934 30.875 ;
     RECT  2.34 30.875 83.826 32.071 ;
     RECT  2.34 32.071 84.114 32.261 ;
     RECT  2.34 32.261 83.697 33.151 ;
     RECT  2.34 33.151 84.114 34.151 ;
     RECT  2.34 34.151 83.862 34.619 ;
     RECT  2.376 34.619 83.862 35.159 ;
     RECT  2.376 35.159 83.754 35.195 ;
     RECT  2.376 35.195 83.697 36.319 ;
     RECT  2.34 36.319 83.697 36.931 ;
     RECT  2.34 36.931 83.862 37.085 ;
     RECT  2.34 37.085 83.697 37.121 ;
     RECT  2.376 37.121 83.697 37.997 ;
     RECT  2.415 37.997 83.697 38.011 ;
     RECT  2.415 38.011 83.754 38.281 ;
     RECT  2.415 38.281 83.97 39.209 ;
     RECT  2.415 39.209 83.862 39.245 ;
     RECT  2.415 39.245 83.697 39.865 ;
     RECT  2.34 39.865 83.697 40.441 ;
     RECT  2.34 40.441 84.114 40.703 ;
     RECT  2.34 40.703 83.97 41.369 ;
     RECT  2.34 41.369 83.862 41.405 ;
     RECT  2.34 41.405 83.826 42.331 ;
     RECT  2.34 42.331 83.934 42.485 ;
     RECT  2.34 42.485 83.697 43.501 ;
     RECT  2.34 43.501 83.862 43.951 ;
     RECT  2.34 43.951 84.114 44.213 ;
     RECT  2.34 44.213 84.042 45.419 ;
     RECT  2.34 45.419 83.898 45.455 ;
     RECT  2.34 45.455 83.697 46.921 ;
     RECT  2.34 46.921 83.862 47.075 ;
     RECT  2.34 47.075 83.697 48.001 ;
     RECT  2.34 48.001 83.898 48.091 ;
     RECT  2.34 48.091 83.97 48.389 ;
     RECT  2.34 48.389 83.898 48.425 ;
     RECT  2.34 48.425 83.754 48.811 ;
     RECT  2.304 48.811 83.754 49.171 ;
     RECT  2.304 49.171 83.826 49.621 ;
     RECT  2.304 49.621 83.934 50.287 ;
     RECT  2.304 50.287 84.006 51.241 ;
     RECT  2.304 51.241 84.042 51.629 ;
     RECT  2.304 51.629 83.898 51.665 ;
     RECT  2.304 51.665 83.697 53.069 ;
     RECT  2.376 53.069 83.697 53.941 ;
     RECT  2.34 53.941 83.697 54.445 ;
     RECT  2.304 54.445 83.697 55.255 ;
     RECT  2.304 55.255 84.15 55.409 ;
     RECT  14.508 55.409 84.15 55.553 ;
     RECT  14.508 55.553 83.697 55.751 ;
     RECT  2.304 55.409 13.662 56.191 ;
     RECT  14.508 55.751 79.506 56.191 ;
     RECT  2.304 56.191 79.506 56.291 ;
     RECT  15.984 56.291 79.506 56.533 ;
     RECT  80.316 55.751 83.697 56.533 ;
     RECT  15.984 56.533 83.697 57.181 ;
     RECT  0.936 57.001 0.954 57.271 ;
     RECT  2.304 56.291 15.21 57.271 ;
     RECT  2.304 57.271 15.246 57.403 ;
     RECT  15.984 57.181 83.97 57.403 ;
     RECT  0.864 57.271 0.954 57.451 ;
     RECT  2.304 57.403 83.97 57.991 ;
     RECT  0.864 57.451 1.494 58.459 ;
     RECT  2.268 57.991 83.97 58.459 ;
     RECT  0.864 58.459 83.97 58.531 ;
     RECT  0.864 58.531 84.042 58.649 ;
     RECT  11.484 58.649 84.042 58.685 ;
     RECT  11.988 58.685 84.042 58.721 ;
     RECT  0.864 58.649 10.674 59.161 ;
     RECT  0.828 59.161 10.674 59.773 ;
     RECT  11.988 58.721 83.697 59.773 ;
     RECT  0.828 59.773 83.697 59.881 ;
     RECT  0.828 59.881 84.114 60.143 ;
     RECT  0.036 58.621 0.054 60.349 ;
     RECT  0.828 60.143 83.697 60.349 ;
     RECT  0.036 60.349 83.697 61.231 ;
     RECT  0.036 61.231 84.114 61.493 ;
     RECT  0.036 61.493 83.697 61.613 ;
     RECT  0.108 61.613 83.697 62.509 ;
     RECT  0.072 62.509 83.697 65.011 ;
     RECT  0.072 65.011 84.114 65.273 ;
     RECT  0.072 65.273 83.97 65.983 ;
     RECT  0.036 65.983 83.97 66.325 ;
     RECT  0.036 66.325 84.042 66.749 ;
     RECT  0.036 66.749 83.898 66.785 ;
     RECT  0.036 66.785 83.754 67.181 ;
     RECT  0.036 67.181 1.458 67.517 ;
     RECT  2.268 67.181 83.754 67.711 ;
     RECT  2.268 67.711 83.826 67.739 ;
     RECT  2.304 67.739 83.826 68.521 ;
     RECT  0.036 67.517 1.422 68.683 ;
     RECT  0.036 68.683 1.458 68.717 ;
     RECT  2.304 68.521 84.042 68.881 ;
     RECT  1.44 68.717 1.458 68.923 ;
     RECT  2.268 68.881 84.042 68.923 ;
     RECT  0.036 68.717 0.558 69.017 ;
     RECT  1.44 68.923 84.042 69.101 ;
     RECT  2.268 69.101 84.042 69.331 ;
     RECT  2.268 69.331 84.114 69.449 ;
     RECT  2.268 69.449 84.042 69.521 ;
     RECT  2.268 69.521 22.086 69.533 ;
     RECT  1.44 69.101 1.458 69.931 ;
     RECT  2.268 69.533 21.798 69.931 ;
     RECT  1.44 69.931 21.798 70.109 ;
     RECT  22.86 69.521 84.042 70.259 ;
     RECT  2.232 70.109 21.798 70.339 ;
     RECT  2.232 70.339 22.05 70.375 ;
     RECT  22.86 70.259 82.638 70.375 ;
     RECT  0.108 69.017 0.558 70.507 ;
     RECT  1.44 70.109 1.458 70.507 ;
     RECT  83.415 70.259 84.042 70.529 ;
     RECT  83.415 70.529 83.898 70.565 ;
     RECT  0.108 70.507 1.458 70.637 ;
     RECT  2.232 70.375 82.638 71.069 ;
     RECT  0.108 70.637 0.558 71.405 ;
     RECT  20.124 71.069 82.638 71.491 ;
     RECT  83.415 70.565 83.697 71.491 ;
     RECT  20.124 71.491 83.697 71.645 ;
     RECT  2.232 71.069 19.35 71.789 ;
     RECT  1.44 70.637 1.458 71.885 ;
     RECT  2.304 71.789 19.35 71.887 ;
     RECT  20.124 71.645 22.374 71.887 ;
     RECT  23.256 71.645 83.697 71.915 ;
     RECT  2.304 71.887 22.374 71.987 ;
     RECT  82.404 71.915 82.638 71.987 ;
     RECT  0.468 71.405 0.558 72.173 ;
     RECT  0.468 72.173 0.522 72.187 ;
     RECT  0.144 72.187 0.522 72.365 ;
     RECT  23.256 71.915 81.63 72.419 ;
     RECT  82.404 71.987 82.422 72.419 ;
     RECT  2.34 71.987 22.374 72.535 ;
     RECT  23.256 72.419 81.558 72.535 ;
     RECT  2.34 72.535 81.558 72.715 ;
     RECT  0.468 72.365 0.522 73.133 ;
     RECT  2.304 72.715 81.558 73.139 ;
     RECT  27.216 73.139 81.558 73.229 ;
     RECT  2.304 73.139 26.442 73.387 ;
     RECT  27.36 73.229 81.558 73.409 ;
     RECT  0.144 73.339 0.234 73.507 ;
     RECT  2.268 73.387 26.442 73.507 ;
     RECT  27.36 73.409 53.442 73.535 ;
     RECT  2.232 73.507 26.442 73.679 ;
     RECT  0.108 73.507 0.234 73.709 ;
     RECT  2.268 73.679 26.442 73.769 ;
     RECT  0.108 73.709 0.126 73.805 ;
     RECT  2.268 73.769 26.262 73.841 ;
     RECT  54.252 73.409 81.558 73.885 ;
     RECT  54.252 73.885 81.738 73.921 ;
     RECT  2.268 73.841 26.226 73.949 ;
     RECT  27.36 73.535 53.298 74.389 ;
     RECT  27.36 74.389 53.37 74.461 ;
     RECT  2.268 73.949 26.19 74.489 ;
     RECT  54.252 73.921 82.062 74.539 ;
     RECT  2.268 74.489 18.897 74.573 ;
     RECT  27.072 74.461 53.37 74.579 ;
     RECT  54.144 74.539 82.062 74.579 ;
     RECT  27.072 74.579 53.19 74.615 ;
     RECT  54.252 74.579 82.062 74.615 ;
     RECT  18.396 74.573 18.897 74.651 ;
     RECT  27.072 74.615 53.01 74.669 ;
     RECT  54.54 74.615 82.062 74.669 ;
     RECT  38.808 74.669 53.01 74.687 ;
     RECT  19.836 74.489 26.19 74.731 ;
     RECT  27.072 74.669 37.71 74.731 ;
     RECT  38.808 74.687 52.866 74.759 ;
     RECT  19.836 74.731 37.71 74.849 ;
     RECT  2.268 74.573 17.586 74.921 ;
     RECT  19.836 74.849 19.926 74.921 ;
     RECT  2.268 74.921 17.154 74.957 ;
     RECT  19.908 74.921 19.926 74.957 ;
     RECT  2.268 74.957 16.974 75.119 ;
     RECT  20.772 74.849 37.71 75.119 ;
     RECT  38.844 74.759 52.866 75.119 ;
     RECT  54.72 74.669 82.062 75.119 ;
     RECT  30.816 75.119 37.602 75.149 ;
     RECT  16.812 75.119 16.974 75.155 ;
     RECT  20.772 75.119 30.078 75.155 ;
     RECT  40.104 75.119 46.818 75.155 ;
     RECT  47.772 75.119 52.866 75.155 ;
     RECT  54.72 75.119 80.874 75.155 ;
     RECT  31.068 75.149 37.602 75.191 ;
     RECT  56.304 75.155 72.897 75.191 ;
     RECT  82.044 75.119 82.062 75.191 ;
     RECT  15.84 75.119 16.002 75.227 ;
     RECT  16.956 75.155 16.974 75.227 ;
     RECT  20.772 75.155 28.566 75.227 ;
     RECT  47.772 75.155 49.41 75.227 ;
     RECT  54.72 75.155 55.566 75.227 ;
     RECT  59.184 75.191 72.897 75.227 ;
     RECT  59.184 75.227 64.962 75.245 ;
     RECT  21.528 75.227 28.494 75.263 ;
     RECT  48.096 75.227 49.302 75.263 ;
     RECT  73.908 75.155 80.874 75.263 ;
     RECT  2.268 75.119 15.066 75.293 ;
     RECT  38.844 75.119 39.258 75.293 ;
     RECT  21.672 75.263 28.35 75.299 ;
     RECT  29.415 75.155 29.97 75.299 ;
     RECT  31.068 75.191 33.822 75.299 ;
     RECT  34.632 75.191 37.602 75.299 ;
     RECT  18.615 74.651 18.897 75.347 ;
     RECT  65.772 75.227 72.897 75.347 ;
     RECT  83.415 71.915 83.697 75.347 ;
     RECT  2.268 75.293 14.562 75.389 ;
     RECT  15.84 75.227 15.858 75.389 ;
     RECT  21.672 75.299 26.262 75.389 ;
     RECT  29.415 75.299 29.826 75.389 ;
     RECT  31.068 75.299 33.75 75.389 ;
     RECT  34.815 75.299 37.602 75.389 ;
     RECT  40.104 75.155 46.71 75.389 ;
     RECT  54.72 75.227 55.35 75.389 ;
     RECT  56.304 75.191 58.338 75.389 ;
     RECT  59.184 75.245 64.926 75.389 ;
     RECT  65.772 75.347 72.774 75.389 ;
     RECT  73.944 75.263 80.874 75.389 ;
     RECT  2.268 75.389 11.79 75.425 ;
     RECT  12.672 75.389 13.914 75.425 ;
     RECT  20.772 75.227 20.79 75.425 ;
     RECT  22.032 75.389 22.23 75.425 ;
     RECT  23.22 75.389 26.262 75.425 ;
     RECT  27.288 75.299 28.35 75.425 ;
     RECT  29.415 75.389 29.754 75.425 ;
     RECT  31.248 75.389 32.706 75.425 ;
     RECT  34.815 75.389 34.974 75.425 ;
     RECT  38.844 75.293 39.078 75.425 ;
     RECT  40.104 75.389 40.305 75.425 ;
     RECT  41.4 75.389 41.418 75.425 ;
     RECT  42.768 75.389 43.038 75.425 ;
     RECT  44.388 75.389 44.838 75.425 ;
     RECT  48.096 75.263 48.834 75.425 ;
     RECT  50.508 75.155 52.686 75.425 ;
     RECT  57.42 75.389 58.23 75.425 ;
     RECT  59.184 75.389 60.318 75.425 ;
     RECT  61.38 75.389 64.926 75.425 ;
     RECT  65.772 75.389 66.366 75.425 ;
     RECT  74.16 75.389 74.538 75.425 ;
     RECT  75.96 75.389 80.874 75.425 ;
     RECT  23.22 75.425 23.238 75.437 ;
     RECT  24.015 75.425 26.262 75.437 ;
     RECT  44.64 75.425 44.838 75.437 ;
     RECT  45.615 75.389 46.062 75.437 ;
     RECT  2.268 75.425 10.278 75.461 ;
     RECT  11.34 75.425 11.79 75.461 ;
     RECT  22.032 75.425 22.05 75.461 ;
     RECT  35.928 75.389 37.602 75.461 ;
     RECT  50.508 75.425 51.786 75.461 ;
     RECT  59.184 75.425 59.202 75.461 ;
     RECT  65.772 75.425 66.15 75.461 ;
     RECT  67.215 75.389 72.705 75.461 ;
     RECT  76.284 75.425 80.874 75.461 ;
     RECT  24.015 75.437 24.174 75.485 ;
     RECT  25.164 75.437 26.262 75.485 ;
     RECT  9.252 75.461 10.278 75.497 ;
     RECT  38.844 75.425 38.862 75.497 ;
     RECT  48.816 75.425 48.834 75.497 ;
     RECT  63.9 75.425 63.918 75.497 ;
     RECT  64.764 75.425 64.926 75.497 ;
     RECT  74.52 75.425 74.538 75.497 ;
     RECT  0.036 74.119 0.054 75.505 ;
     RECT  25.56 75.485 26.262 75.533 ;
     RECT  31.248 75.425 31.266 75.533 ;
     RECT  33.66 75.389 33.678 75.533 ;
     RECT  35.928 75.461 36.378 75.533 ;
     RECT  37.188 75.461 37.602 75.533 ;
     RECT  42.768 75.425 42.786 75.533 ;
     RECT  50.508 75.461 51.39 75.533 ;
     RECT  52.668 75.425 52.686 75.533 ;
     RECT  54.72 75.389 54.738 75.533 ;
     RECT  61.815 75.425 62.73 75.533 ;
     RECT  4.068 75.461 8.442 75.569 ;
     RECT  9.612 75.497 9.738 75.569 ;
     RECT  11.556 75.461 11.79 75.569 ;
     RECT  12.672 75.425 13.698 75.569 ;
     RECT  25.56 75.533 25.578 75.569 ;
     RECT  28.008 75.425 28.026 75.569 ;
     RECT  35.928 75.533 35.946 75.569 ;
     RECT  37.224 75.533 37.242 75.569 ;
     RECT  44.64 75.437 44.658 75.569 ;
     RECT  50.58 75.533 51.105 75.569 ;
     RECT  58.212 75.425 58.23 75.569 ;
     RECT  66.132 75.461 66.15 75.569 ;
     RECT  67.215 75.461 71.334 75.581 ;
     RECT  6.444 75.569 8.442 75.617 ;
     RECT  12.672 75.569 13.305 75.617 ;
     RECT  18.615 75.347 18.705 75.617 ;
     RECT  24.015 75.485 24.105 75.617 ;
     RECT  29.415 75.425 29.505 75.617 ;
     RECT  34.815 75.425 34.905 75.617 ;
     RECT  40.215 75.425 40.305 75.617 ;
     RECT  45.615 75.437 45.705 75.617 ;
     RECT  51.015 75.569 51.105 75.617 ;
     RECT  56.415 75.389 56.505 75.617 ;
     RECT  61.815 75.533 61.905 75.617 ;
     RECT  67.215 75.581 69.75 75.617 ;
     RECT  72.615 75.461 72.705 75.617 ;
     RECT  83.415 75.347 83.505 75.617 ;
     RECT  70.56 75.581 71.334 75.629 ;
     RECT  4.14 75.569 5.706 75.659 ;
     RECT  8.1 75.617 8.442 75.659 ;
     RECT  11.772 75.569 11.79 75.659 ;
     RECT  12.672 75.617 12.69 75.659 ;
     RECT  6.444 75.617 7.362 75.695 ;
     RECT  8.424 75.659 8.442 75.731 ;
     RECT  4.14 75.659 4.554 75.767 ;
     RECT  6.84 75.695 7.362 75.767 ;
     RECT  2.268 75.461 3.078 75.803 ;
     RECT  4.14 75.767 4.158 75.803 ;
     RECT  7.344 75.767 7.362 75.803 ;
     RECT  0.036 75.505 0.162 76.199 ;
     RECT  1.404 74.551 1.422 76.205 ;
     RECT  0.108 76.199 0.162 76.301 ;
     RECT  67.608 75.617 69.75 76.397 ;
     RECT  0.108 76.301 0.126 76.493 ;
     RECT  2.304 75.803 3.078 76.781 ;
     RECT  2.304 76.781 2.394 76.877 ;
     RECT  76.32 75.461 80.874 76.877 ;
     RECT  67.896 76.397 69.75 76.925 ;
     RECT  76.536 76.877 80.874 76.925 ;
     RECT  2.376 76.877 2.394 76.973 ;
     RECT  68.544 76.925 69.75 76.973 ;
     RECT  76.716 76.925 80.874 76.973 ;
     RECT  77.4 76.973 80.874 77.453 ;
     RECT  68.544 76.973 69.246 77.549 ;
     RECT  71.28 75.629 71.334 77.549 ;
     RECT  80.388 77.453 80.874 77.549 ;
     RECT  68.544 77.549 69.21 77.597 ;
     RECT  80.388 77.549 80.406 77.597 ;
     RECT  68.94 77.597 69.21 77.645 ;
     RECT  71.316 77.549 71.334 77.645 ;
     RECT  77.4 77.453 79.326 77.645 ;
    LAYER M4 ;
     RECT  0.025 61.584 0.06 61.608 ;
     RECT  0.06 61.584 0.137 73.896 ;
     RECT  0.06 76.08 0.137 76.968 ;
     RECT  0.137 76.176 1.433 76.968 ;
     RECT  0.137 61.68 2.185 73.896 ;
     RECT  2.365 31.104 2.401 31.128 ;
     RECT  1.433 76.368 2.405 76.968 ;
     RECT  2.365 5.184 2.408 5.208 ;
     RECT  2.365 6.384 2.408 6.408 ;
     RECT  2.365 7.392 2.408 7.416 ;
     RECT  2.293 12.768 2.408 12.792 ;
     RECT  2.293 14.304 2.408 14.328 ;
     RECT  2.365 15.312 2.408 15.336 ;
     RECT  2.365 17.376 2.408 17.4 ;
     RECT  2.365 18.72 2.408 18.744 ;
     RECT  2.285 23.328 2.408 23.352 ;
     RECT  2.293 25.104 2.408 25.128 ;
     RECT  2.401 30.336 2.408 31.128 ;
     RECT  2.365 37.968 2.408 37.992 ;
     RECT  2.365 42.192 2.408 42.744 ;
     RECT  2.401 44.064 2.408 44.088 ;
     RECT  2.365 49.008 2.408 49.032 ;
     RECT  2.293 53.04 2.408 53.064 ;
     RECT  2.365 54.096 2.408 54.36 ;
     RECT  2.365 56.064 2.408 56.088 ;
     RECT  2.185 60.864 2.408 73.896 ;
     RECT  2.405 76.368 2.408 76.776 ;
     RECT  2.408 2.148 2.512 76.776 ;
     RECT  2.512 76.368 2.693 76.776 ;
     RECT  2.512 2.418 2.704 75.342 ;
     RECT  2.704 54.096 2.765 74.088 ;
     RECT  2.704 3.84 2.819 3.96 ;
     RECT  2.704 7.392 2.819 10.296 ;
     RECT  2.704 22.8 2.945 25.224 ;
     RECT  2.693 76.656 2.981 76.776 ;
     RECT  2.704 17.376 3.053 21.672 ;
     RECT  2.981 76.752 3.089 76.776 ;
     RECT  3.053 18.96 3.161 21.672 ;
     RECT  2.704 5.184 3.197 6.408 ;
     RECT  2.819 8.256 3.197 10.296 ;
     RECT  2.704 42.192 3.197 45.96 ;
     RECT  2.945 22.848 3.269 25.224 ;
     RECT  3.197 42.192 3.269 42.216 ;
     RECT  3.269 24.336 3.341 25.224 ;
     RECT  3.197 43.248 3.341 45.96 ;
     RECT  2.704 2.832 3.413 2.856 ;
     RECT  3.161 19.104 3.413 21.672 ;
     RECT  3.269 22.848 3.413 22.872 ;
     RECT  2.704 37.824 3.521 37.992 ;
     RECT  3.197 8.976 3.593 10.296 ;
     RECT  2.704 11.376 3.628 13.08 ;
     RECT  2.704 50.16 3.692 50.184 ;
     RECT  2.704 27.696 3.697 34.872 ;
     RECT  3.697 26.784 3.733 34.872 ;
     RECT  2.704 35.952 3.733 36.648 ;
     RECT  3.341 25.2 3.769 25.224 ;
     RECT  2.704 51.36 3.769 53.064 ;
     RECT  2.765 54.096 3.769 58.296 ;
     RECT  2.765 59.328 3.769 74.088 ;
     RECT  2.704 39.072 3.773 39.096 ;
     RECT  3.692 50.016 3.779 50.184 ;
     RECT  3.779 50.112 3.805 50.184 ;
     RECT  3.769 51.36 3.805 74.088 ;
     RECT  3.769 25.2 3.809 25.656 ;
     RECT  3.733 26.784 3.877 36.648 ;
     RECT  3.521 37.824 3.877 37.848 ;
     RECT  3.413 21.216 3.913 21.672 ;
     RECT  2.704 49.008 3.913 49.032 ;
     RECT  2.704 40.272 3.953 41.064 ;
     RECT  3.628 11.616 4.057 13.08 ;
     RECT  2.704 14.208 4.057 15.432 ;
     RECT  3.593 10.128 4.061 10.296 ;
     RECT  3.809 25.296 4.061 25.656 ;
     RECT  3.877 26.784 4.061 37.848 ;
     RECT  3.341 45.936 4.093 45.96 ;
     RECT  2.819 3.84 4.201 3.912 ;
     RECT  3.197 5.184 4.201 5.88 ;
     RECT  4.093 45.936 4.205 46.776 ;
     RECT  3.953 41.04 4.309 41.064 ;
     RECT  3.697 42.144 4.309 42.168 ;
     RECT  4.201 3.84 4.345 5.88 ;
     RECT  4.061 27.792 4.403 36.984 ;
     RECT  4.345 3.408 4.417 5.88 ;
     RECT  3.413 19.104 4.417 20.184 ;
     RECT  3.913 21.216 4.417 22.824 ;
     RECT  4.417 19.104 4.421 22.824 ;
     RECT  3.805 50.112 4.493 74.088 ;
     RECT  4.417 3.408 4.525 6.12 ;
     RECT  3.949 7.152 4.525 7.176 ;
     RECT  4.057 11.616 4.525 15.432 ;
     RECT  4.237 26.736 4.547 26.76 ;
     RECT  4.525 11.616 4.561 15.912 ;
     RECT  4.421 20.112 4.565 22.824 ;
     RECT  4.309 41.04 4.565 42.168 ;
     RECT  4.493 54.048 4.595 74.088 ;
     RECT  4.561 11.616 4.597 16.44 ;
     RECT  3.053 17.664 4.597 17.88 ;
     RECT  4.565 20.112 4.601 22.584 ;
     RECT  4.525 3.408 4.633 7.176 ;
     RECT  4.421 19.104 4.637 19.128 ;
     RECT  4.601 20.832 4.709 22.584 ;
     RECT  4.597 11.616 4.741 17.88 ;
     RECT  3.341 43.248 4.741 44.376 ;
     RECT  4.741 11.616 4.787 19.08 ;
     RECT  4.595 54.336 4.813 74.088 ;
     RECT  4.417 75.12 4.813 75.144 ;
     RECT  4.669 24 4.885 24.024 ;
     RECT  4.741 43.248 4.921 44.424 ;
     RECT  4.565 41.04 4.993 41.592 ;
     RECT  4.205 46.128 4.993 46.776 ;
     RECT  4.885 23.904 5.029 24.024 ;
     RECT  4.061 25.296 5.029 25.32 ;
     RECT  3.913 48.816 5.125 49.032 ;
     RECT  4.787 11.616 5.132 17.064 ;
     RECT  3.593 8.976 5.137 9 ;
     RECT  4.061 10.128 5.137 10.152 ;
     RECT  4.403 27.888 5.137 36.984 ;
     RECT  5.132 11.472 5.165 17.064 ;
     RECT  5.137 8.976 5.173 10.152 ;
     RECT  5.165 11.328 5.173 17.064 ;
     RECT  4.633 3.408 5.177 7.8 ;
     RECT  5.173 8.976 5.177 17.064 ;
     RECT  5.177 3.456 5.209 7.8 ;
     RECT  5.029 23.904 5.209 25.32 ;
     RECT  5.137 27.888 5.213 37.272 ;
     RECT  4.813 54.336 5.213 75.144 ;
     RECT  5.101 38.448 5.245 38.472 ;
     RECT  4.993 40.944 5.245 41.592 ;
     RECT  4.993 46.128 5.245 47.304 ;
     RECT  5.209 23.904 5.281 25.512 ;
     RECT  5.213 35.76 5.281 37.272 ;
     RECT  5.245 38.448 5.281 39.48 ;
     RECT  4.787 18.768 5.285 19.08 ;
     RECT  4.709 20.832 5.285 22.392 ;
     RECT  4.921 42.72 5.321 44.424 ;
     RECT  5.213 60.144 5.353 75.144 ;
     RECT  5.177 8.976 5.573 17.016 ;
     RECT  5.125 48.432 5.597 49.032 ;
     RECT  5.321 42.72 5.605 44.376 ;
     RECT  5.281 35.76 5.645 39.48 ;
     RECT  4.493 50.112 5.645 53.064 ;
     RECT  5.285 22.368 5.677 22.392 ;
     RECT  5.281 23.904 5.677 26.616 ;
     RECT  5.285 20.832 5.753 21.144 ;
     RECT  5.645 35.76 5.753 39.192 ;
     RECT  5.353 60.144 5.785 75.192 ;
     RECT  5.245 40.848 5.797 41.592 ;
     RECT  5.605 42.576 5.797 44.376 ;
     RECT  5.285 18.816 5.893 19.08 ;
     RECT  5.245 45.984 5.893 47.304 ;
     RECT  5.597 48.432 5.893 49.08 ;
     RECT  5.573 8.976 5.897 16.872 ;
     RECT  5.677 22.368 5.969 26.616 ;
     RECT  5.213 27.888 5.969 34.44 ;
     RECT  5.753 20.832 6.005 21.096 ;
     RECT  5.969 27.888 6.073 34.344 ;
     RECT  5.969 22.368 6.077 26.472 ;
     RECT  5.893 45.984 6.077 49.08 ;
     RECT  5.897 8.976 6.113 10.44 ;
     RECT  6.077 46.08 6.113 49.08 ;
     RECT  5.209 3.456 6.149 7.992 ;
     RECT  5.213 54.336 6.181 59.112 ;
     RECT  5.785 60.144 6.181 75.288 ;
     RECT  6.149 3.6 6.221 7.992 ;
     RECT  5.893 18.816 6.277 19.608 ;
     RECT  5.797 40.848 6.325 44.376 ;
     RECT  6.073 27.648 6.329 34.344 ;
     RECT  5.753 35.76 6.329 38.904 ;
     RECT  6.329 35.76 6.469 38.712 ;
     RECT  6.113 46.368 6.469 49.08 ;
     RECT  5.645 50.112 6.469 52.824 ;
     RECT  6.325 40.224 6.545 44.376 ;
     RECT  6.469 46.368 6.563 52.824 ;
     RECT  6.221 3.84 6.577 7.992 ;
     RECT  6.113 8.976 6.577 9 ;
     RECT  5.897 11.712 6.649 16.872 ;
     RECT  6.649 11.712 6.689 17.112 ;
     RECT  6.689 12.864 6.761 17.112 ;
     RECT  6.563 46.704 6.793 52.824 ;
     RECT  6.181 53.904 6.793 75.288 ;
     RECT  6.793 46.704 6.829 75.288 ;
     RECT  6.329 27.648 6.937 34.008 ;
     RECT  6.005 20.832 7.004 20.856 ;
     RECT  6.077 22.368 7.189 26.04 ;
     RECT  6.937 27.072 7.189 34.008 ;
     RECT  7.004 20.832 7.225 21.096 ;
     RECT  7.189 22.368 7.225 34.008 ;
     RECT  6.113 10.08 7.369 10.44 ;
     RECT  6.689 11.712 7.369 11.832 ;
     RECT  6.545 40.224 7.585 43.752 ;
     RECT  7.297 44.928 7.585 45.192 ;
     RECT  6.577 3.84 7.621 9 ;
     RECT  6.277 18.144 7.669 19.8 ;
     RECT  7.225 20.832 7.669 34.008 ;
     RECT  6.829 46.704 7.765 75.336 ;
     RECT  5.929 2.304 7.808 2.328 ;
     RECT  7.621 3.648 7.808 9 ;
     RECT  7.369 10.08 7.808 11.832 ;
     RECT  6.761 12.864 7.808 16.872 ;
     RECT  7.669 18.144 7.808 34.008 ;
     RECT  6.469 35.568 7.808 38.712 ;
     RECT  7.585 40.224 7.808 45.192 ;
     RECT  7.765 46.608 7.808 75.336 ;
     RECT  7.808 2.148 7.912 75.612 ;
     RECT  7.912 2.304 8.104 75.342 ;
     RECT  8.104 21.168 8.345 27.24 ;
     RECT  8.104 28.704 8.381 59.832 ;
     RECT  8.104 2.304 8.417 2.328 ;
     RECT  8.381 28.704 8.453 58.728 ;
     RECT  8.104 60.912 8.489 75.096 ;
     RECT  8.453 46.512 8.561 58.728 ;
     RECT  8.453 28.704 8.867 45.48 ;
     RECT  8.867 40.464 8.885 45.48 ;
     RECT  8.561 52.176 8.921 58.728 ;
     RECT  8.104 3.408 9.029 20.136 ;
     RECT  8.345 21.264 9.109 27.24 ;
     RECT  8.867 28.704 9.109 39.432 ;
     RECT  8.921 58.704 9.137 58.728 ;
     RECT  8.885 40.464 9.209 45 ;
     RECT  8.489 61.056 9.317 75.096 ;
     RECT  9.109 21.264 9.353 39.432 ;
     RECT  8.921 52.176 9.461 57.72 ;
     RECT  8.561 46.512 9.529 50.664 ;
     RECT  9.461 52.176 9.529 56.328 ;
     RECT  9.353 28.368 9.539 39.432 ;
     RECT  8.381 59.808 9.637 59.832 ;
     RECT  9.353 21.264 9.677 27.24 ;
     RECT  9.539 28.464 9.785 39.432 ;
     RECT  9.317 61.056 9.821 62.616 ;
     RECT  9.677 21.264 9.853 26.28 ;
     RECT  9.209 40.896 9.877 45 ;
     RECT  9.853 20.928 9.893 26.28 ;
     RECT  9.821 61.056 9.925 62.472 ;
     RECT  9.529 46.512 9.997 56.328 ;
     RECT  9.877 40.896 10.037 45.048 ;
     RECT  9.637 59.52 10.069 59.832 ;
     RECT  9.925 61.008 10.069 62.472 ;
     RECT  9.317 63.744 10.073 75.096 ;
     RECT  10.069 59.52 10.141 62.472 ;
     RECT  9.461 57.312 10.213 57.72 ;
     RECT  10.141 58.752 10.213 62.472 ;
     RECT  10.073 63.744 10.217 67.128 ;
     RECT  9.029 3.744 10.325 19.896 ;
     RECT  9.785 28.608 10.429 39.432 ;
     RECT  10.037 40.896 10.429 45 ;
     RECT  10.213 57.312 10.433 62.472 ;
     RECT  10.433 59.568 10.505 62.472 ;
     RECT  10.073 68.16 10.537 75.096 ;
     RECT  10.325 11.424 10.549 19.896 ;
     RECT  10.549 11.424 10.636 19.944 ;
     RECT  9.997 46.272 10.649 56.328 ;
     RECT  10.649 51.552 10.681 56.328 ;
     RECT  10.433 57.312 10.681 58.392 ;
     RECT  10.636 11.424 10.721 19.896 ;
     RECT  10.325 3.744 10.789 10.2 ;
     RECT  9.893 22.512 10.829 26.28 ;
     RECT  9.241 2.256 10.835 2.28 ;
     RECT  9.893 20.928 10.861 21.432 ;
     RECT  10.829 22.512 10.861 26.232 ;
     RECT  10.537 68.16 10.865 75.24 ;
     RECT  10.429 28.608 10.901 45 ;
     RECT  10.217 63.744 10.933 67.032 ;
     RECT  10.901 28.608 11.125 31.56 ;
     RECT  10.681 51.552 11.315 58.392 ;
     RECT  10.789 3.264 11.401 10.2 ;
     RECT  10.721 11.424 11.401 19.8 ;
     RECT  10.861 20.928 11.441 26.232 ;
     RECT  10.901 32.64 11.509 45 ;
     RECT  10.649 46.272 11.509 50.184 ;
     RECT  11.401 27.264 11.545 27.288 ;
     RECT  11.125 28.608 11.545 31.512 ;
     RECT  11.401 3.264 11.549 19.8 ;
     RECT  11.509 32.64 11.657 50.184 ;
     RECT  11.657 32.64 11.729 50.136 ;
     RECT  10.865 68.16 11.837 73.272 ;
     RECT  10.865 74.832 11.869 75.24 ;
     RECT  10.505 59.808 11.893 62.472 ;
     RECT  10.933 63.552 11.893 67.032 ;
     RECT  11.441 22.224 11.905 26.232 ;
     RECT  11.545 27.264 11.905 31.512 ;
     RECT  11.893 59.808 11.939 67.032 ;
     RECT  11.869 74.688 11.941 75.24 ;
     RECT  11.441 20.928 11.945 21.096 ;
     RECT  11.315 51.984 11.969 58.392 ;
     RECT  11.969 51.984 11.977 58.68 ;
     RECT  11.939 59.808 11.977 63.24 ;
     RECT  11.729 32.736 11.981 50.136 ;
     RECT  11.941 74.64 11.981 75.24 ;
     RECT  11.549 3.264 12.037 19.704 ;
     RECT  11.939 64.368 12.037 67.032 ;
     RECT  11.977 51.984 12.061 63.24 ;
     RECT  12.037 2.688 12.125 19.704 ;
     RECT  11.981 49.2 12.161 50.136 ;
     RECT  12.061 51.984 12.161 58.68 ;
     RECT  12.125 3.216 12.197 19.704 ;
     RECT  11.905 22.224 12.197 31.512 ;
     RECT  12.061 59.808 12.22 63.24 ;
     RECT  11.837 68.976 12.661 73.272 ;
     RECT  12.161 51.984 12.764 56.28 ;
     RECT  11.981 32.736 12.769 48.168 ;
     RECT  12.805 0.528 12.841 0.552 ;
     RECT  12.197 18.24 12.841 19.704 ;
     RECT  12.197 22.272 12.949 31.512 ;
     RECT  12.769 32.592 12.949 48.168 ;
     RECT  11.945 20.928 12.997 21 ;
     RECT  12.161 49.248 13.021 50.136 ;
     RECT  12.764 51.12 13.021 56.28 ;
     RECT  12.841 18.24 13.045 19.8 ;
     RECT  12.997 20.928 13.045 21.288 ;
     RECT  12.841 0.432 13.093 0.552 ;
     RECT  12.161 57.408 13.129 58.68 ;
     RECT  12.22 59.808 13.129 62.76 ;
     RECT  13.093 0.432 13.165 0.6 ;
     RECT  12.197 3.216 13.208 17.112 ;
     RECT  13.045 18.24 13.208 21.288 ;
     RECT  12.949 22.272 13.208 48.168 ;
     RECT  13.021 49.248 13.208 56.28 ;
     RECT  13.129 57.408 13.208 62.76 ;
     RECT  12.037 64.368 13.208 67.704 ;
     RECT  12.661 68.976 13.208 73.656 ;
     RECT  11.981 74.64 13.208 75.096 ;
     RECT  13.208 2.148 13.312 75.612 ;
     RECT  13.312 2.148 13.345 75.342 ;
     RECT  13.345 1.728 13.504 75.342 ;
     RECT  13.165 0.432 13.561 0.648 ;
     RECT  13.504 20.976 13.601 51.24 ;
     RECT  13.504 71.472 13.619 75.288 ;
     RECT  13.561 0.144 13.661 0.648 ;
     RECT  13.661 0.096 13.669 0.648 ;
     RECT  13.504 1.728 13.669 1.896 ;
     RECT  13.669 0.096 13.745 1.896 ;
     RECT  13.504 64.416 13.753 67.656 ;
     RECT  13.745 0.144 13.907 1.896 ;
     RECT  13.601 20.976 13.907 48.792 ;
     RECT  13.907 21.024 13.997 48.792 ;
     RECT  13.907 1.104 14.195 1.896 ;
     RECT  13.504 3.168 14.249 19.8 ;
     RECT  14.249 3.408 14.285 19.8 ;
     RECT  13.504 68.928 14.285 70.056 ;
     RECT  14.195 1.104 14.291 1.848 ;
     RECT  13.997 26.016 14.291 48.792 ;
     RECT  13.504 57.408 14.291 63.24 ;
     RECT  14.291 26.592 14.465 44.136 ;
     RECT  14.465 30.672 14.537 44.136 ;
     RECT  13.601 49.872 14.569 51.24 ;
     RECT  13.504 52.464 14.569 54.696 ;
     RECT  13.504 56.256 14.569 56.28 ;
     RECT  13.753 64.656 14.749 67.656 ;
     RECT  14.291 57.408 14.821 62.184 ;
     RECT  13.619 72.528 14.861 75.288 ;
     RECT  14.291 45.264 14.893 48.792 ;
     RECT  14.569 49.872 14.893 56.28 ;
     RECT  14.821 57.36 14.905 62.184 ;
     RECT  13.997 21.024 14.965 24.744 ;
     RECT  14.965 21.024 15.037 25.272 ;
     RECT  14.749 64.656 15.041 68.376 ;
     RECT  14.861 72.816 15.077 75.288 ;
     RECT  14.291 1.152 15.085 1.848 ;
     RECT  14.285 69.456 15.113 70.056 ;
     RECT  13.619 71.472 15.113 71.496 ;
     RECT  15.041 64.656 15.145 68.28 ;
     RECT  15.145 64.464 15.149 68.28 ;
     RECT  15.085 1.152 15.193 1.8 ;
     RECT  14.965 0.144 15.205 0.168 ;
     RECT  14.285 3.888 15.253 19.8 ;
     RECT  15.037 20.928 15.253 25.272 ;
     RECT  14.465 26.592 15.253 29.544 ;
     RECT  14.905 57.408 15.289 62.184 ;
     RECT  14.291 63.216 15.289 63.24 ;
     RECT  15.149 64.464 15.293 67.656 ;
     RECT  15.253 3.888 15.433 25.272 ;
     RECT  15.253 26.352 15.433 29.544 ;
     RECT  15.077 72.816 15.437 74.616 ;
     RECT  15.433 3.888 15.469 29.544 ;
     RECT  14.537 30.672 15.469 44.088 ;
     RECT  14.893 45.264 15.473 56.28 ;
     RECT  15.205 0.096 15.493 0.168 ;
     RECT  15.293 64.656 15.532 67.656 ;
     RECT  15.113 69.84 15.833 70.056 ;
     RECT  15.469 3.888 15.901 44.088 ;
     RECT  15.473 45.264 15.901 56.04 ;
     RECT  15.193 1.728 15.923 1.8 ;
     RECT  15.901 3.888 16.069 56.04 ;
     RECT  16.069 3.408 16.157 56.04 ;
     RECT  15.493 0.096 16.211 0.552 ;
     RECT  15.833 70.032 16.405 70.056 ;
     RECT  16.405 70.032 16.441 70.392 ;
     RECT  16.157 3.84 16.553 56.04 ;
     RECT  15.532 64.656 16.873 66.888 ;
     RECT  16.553 3.84 16.877 35.736 ;
     RECT  16.553 36.912 16.877 56.04 ;
     RECT  16.877 52.224 16.909 56.04 ;
     RECT  16.441 70.032 16.913 70.824 ;
     RECT  16.909 52.224 16.945 56.088 ;
     RECT  15.289 57.408 16.945 63.24 ;
     RECT  16.913 70.032 16.945 70.056 ;
     RECT  16.945 69.504 16.985 70.056 ;
     RECT  15.923 1.728 17.009 1.752 ;
     RECT  16.945 52.224 17.017 63.24 ;
     RECT  16.117 72.24 17.021 72.264 ;
     RECT  16.877 36.912 17.165 51.24 ;
     RECT  17.165 36.912 17.267 47.688 ;
     RECT  17.165 49.056 17.273 51.24 ;
     RECT  16.549 0.576 17.281 0.6 ;
     RECT  16.225 2.832 17.308 2.856 ;
     RECT  17.017 52.224 17.341 63.288 ;
     RECT  16.873 64.368 17.341 66.888 ;
     RECT  16.985 69.504 17.363 69.528 ;
     RECT  16.877 3.84 17.377 32.856 ;
     RECT  17.341 52.224 17.377 66.888 ;
     RECT  15.437 73.488 17.413 74.616 ;
     RECT  17.377 52.224 17.629 67.128 ;
     RECT  17.233 68.112 17.629 68.136 ;
     RECT  16.877 33.936 17.701 35.736 ;
     RECT  17.267 36.912 17.701 47.16 ;
     RECT  17.377 3.312 17.881 32.856 ;
     RECT  17.701 33.936 17.881 47.16 ;
     RECT  17.509 0.096 17.921 0.168 ;
     RECT  17.629 52.224 17.989 68.136 ;
     RECT  17.809 69.264 17.989 69.288 ;
     RECT  17.413 72.384 18.061 74.616 ;
     RECT  17.273 49.536 18.133 51.24 ;
     RECT  17.989 52.224 18.133 69.288 ;
     RECT  18.133 49.536 18.241 69.288 ;
     RECT  17.921 0.144 18.277 0.168 ;
     RECT  18.241 48.144 18.277 48.168 ;
     RECT  18.241 49.44 18.277 69.288 ;
     RECT  17.277 71.232 18.277 71.256 ;
     RECT  18.277 0.144 18.361 0.6 ;
     RECT  17.009 1.728 18.608 1.848 ;
     RECT  17.881 3.312 18.608 47.16 ;
     RECT  18.277 48.144 18.608 69.288 ;
     RECT  18.277 70.848 18.608 71.256 ;
     RECT  18.061 72.336 18.608 74.616 ;
     RECT  18.361 0.144 18.611 0.216 ;
     RECT  18.608 1.728 18.712 75.612 ;
     RECT  18.611 0.192 18.803 0.216 ;
     RECT  18.712 1.728 18.904 75.342 ;
     RECT  18.904 70.368 18.965 70.92 ;
     RECT  18.904 1.728 19.289 2.328 ;
     RECT  18.904 72.48 19.397 74.664 ;
     RECT  18.904 3.312 19.577 24.984 ;
     RECT  19.397 72.48 19.613 72.504 ;
     RECT  19.289 2.304 19.897 2.328 ;
     RECT  19.577 3.552 19.897 24.984 ;
     RECT  18.904 26.016 19.897 49.032 ;
     RECT  18.904 50.016 19.897 69.048 ;
     RECT  18.965 70.656 20.005 70.92 ;
     RECT  19.897 2.304 20.473 2.424 ;
     RECT  19.897 3.552 20.545 69.048 ;
     RECT  20.545 3.504 20.549 69.048 ;
     RECT  20.473 2.256 20.617 2.424 ;
     RECT  20.549 3.504 20.617 47.496 ;
     RECT  19.397 73.536 20.617 74.664 ;
     RECT  20.617 72.96 20.732 74.664 ;
     RECT  20.732 72.96 20.819 75.288 ;
     RECT  20.221 71.904 20.837 71.928 ;
     RECT  20.819 72.96 21.049 74.328 ;
     RECT  20.617 2.256 21.341 47.496 ;
     RECT  21.341 2.256 21.377 2.952 ;
     RECT  20.549 49.152 21.377 69.048 ;
     RECT  20.005 70.128 21.493 70.92 ;
     RECT  21.377 52.416 21.517 69.048 ;
     RECT  21.493 70.128 21.517 71.304 ;
     RECT  21.517 52.416 21.549 71.304 ;
     RECT  21.377 49.152 21.637 51.24 ;
     RECT  21.341 4.368 21.665 47.496 ;
     RECT  21.665 35.952 21.733 47.496 ;
     RECT  21.637 48.912 21.733 51.24 ;
     RECT  21.377 2.304 21.773 2.952 ;
     RECT  21.733 35.952 21.989 51.24 ;
     RECT  21.049 72.672 22.021 74.328 ;
     RECT  21.989 47.76 22.025 51.24 ;
     RECT  22.025 47.76 22.133 50.904 ;
     RECT  21.773 2.784 22.381 2.952 ;
     RECT  21.989 35.952 22.421 46.776 ;
     RECT  21.549 52.416 22.489 69.528 ;
     RECT  22.381 2.784 22.561 3.288 ;
     RECT  21.665 4.368 22.561 34.728 ;
     RECT  21.549 70.896 22.633 71.304 ;
     RECT  22.021 72.672 22.673 74.856 ;
     RECT  22.561 2.784 22.705 34.728 ;
     RECT  22.421 35.952 22.705 46.632 ;
     RECT  22.705 2.784 22.997 46.632 ;
     RECT  22.673 73.536 23.183 74.856 ;
     RECT  22.633 70.896 23.228 71.544 ;
     RECT  22.133 47.76 23.245 50.856 ;
     RECT  23.245 47.664 23.425 50.856 ;
     RECT  22.489 51.936 23.425 69.528 ;
     RECT  23.183 73.536 23.713 75.432 ;
     RECT  22.997 27.072 23.821 46.632 ;
     RECT  23.425 47.664 23.821 69.528 ;
     RECT  22.997 2.784 24.008 25.944 ;
     RECT  23.821 27.072 24.008 69.528 ;
     RECT  23.228 70.896 24.008 72.024 ;
     RECT  23.713 73.392 24.008 75.432 ;
     RECT  24.008 2.148 24.112 75.612 ;
     RECT  24.112 2.256 24.304 75.48 ;
     RECT  24.304 25.008 24.467 69.72 ;
     RECT  24.304 2.256 24.509 23.976 ;
     RECT  24.509 2.256 24.797 21.576 ;
     RECT  24.467 45.216 24.869 69.72 ;
     RECT  24.467 25.008 25.121 44.184 ;
     RECT  25.121 35.52 25.157 44.184 ;
     RECT  24.869 49.296 25.157 69.72 ;
     RECT  24.869 45.216 25.193 48.216 ;
     RECT  24.304 75.264 25.193 75.48 ;
     RECT  24.304 72.72 25.297 73.944 ;
     RECT  25.193 75.264 25.297 75.288 ;
     RECT  25.297 72.72 25.337 75.288 ;
     RECT  25.157 49.296 25.445 55.992 ;
     RECT  25.157 57.024 25.445 69.72 ;
     RECT  24.304 70.896 25.549 71.688 ;
     RECT  25.445 57.36 25.621 69.72 ;
     RECT  25.549 70.896 25.621 71.736 ;
     RECT  25.121 25.008 25.661 34.056 ;
     RECT  24.509 22.752 25.729 23.976 ;
     RECT  25.337 72.72 25.811 74.664 ;
     RECT  25.729 22.56 25.877 23.976 ;
     RECT  25.661 25.008 25.909 30.696 ;
     RECT  25.661 31.68 25.949 34.056 ;
     RECT  25.877 22.8 26.017 23.976 ;
     RECT  25.909 24.96 26.017 30.696 ;
     RECT  25.157 42.288 26.053 44.184 ;
     RECT  25.193 45.216 26.053 47.688 ;
     RECT  25.621 57.36 26.053 71.736 ;
     RECT  26.017 22.8 26.093 30.696 ;
     RECT  24.797 2.832 26.197 21.576 ;
     RECT  26.053 42.288 26.233 47.688 ;
     RECT  26.233 42.288 26.269 47.88 ;
     RECT  25.157 35.52 26.341 41.256 ;
     RECT  26.269 42.288 26.341 48.216 ;
     RECT  26.197 2.832 26.345 21.672 ;
     RECT  26.053 57.36 26.413 71.928 ;
     RECT  25.445 49.296 26.485 55.848 ;
     RECT  26.413 56.832 26.485 71.928 ;
     RECT  26.345 4.272 26.669 11.736 ;
     RECT  26.093 22.8 26.669 25.224 ;
     RECT  26.341 35.52 26.705 48.216 ;
     RECT  26.093 26.208 26.737 30.696 ;
     RECT  25.949 31.68 26.737 33.96 ;
     RECT  26.485 49.296 26.737 71.928 ;
     RECT  26.669 4.368 26.813 11.736 ;
     RECT  26.705 35.712 26.845 48.216 ;
     RECT  26.737 49.248 26.845 71.928 ;
     RECT  26.737 26.208 27.065 33.96 ;
     RECT  26.345 12.816 27.313 21.672 ;
     RECT  26.669 22.8 27.313 25.08 ;
     RECT  25.811 72.912 27.317 74.664 ;
     RECT  26.845 35.712 27.425 71.928 ;
     RECT  27.425 47.184 27.461 71.928 ;
     RECT  27.461 47.328 27.709 71.928 ;
     RECT  27.317 72.912 27.709 73.944 ;
     RECT  27.313 12.816 27.781 25.08 ;
     RECT  27.065 26.208 27.781 33.864 ;
     RECT  26.345 2.832 27.853 3.192 ;
     RECT  26.813 4.416 27.853 11.736 ;
     RECT  27.425 35.712 28.033 46.152 ;
     RECT  27.781 12.816 28.177 33.864 ;
     RECT  28.033 35.04 28.177 46.152 ;
     RECT  27.853 2.832 28.213 11.736 ;
     RECT  28.177 12.816 28.213 46.152 ;
     RECT  28.213 2.832 28.429 46.152 ;
     RECT  27.709 47.328 28.429 73.944 ;
     RECT  28.429 2.832 28.433 73.944 ;
     RECT  28.433 73.824 28.825 73.944 ;
     RECT  28.825 73.824 28.969 74.424 ;
     RECT  28.433 2.832 29.408 72.744 ;
     RECT  28.969 73.824 29.408 75.144 ;
     RECT  29.408 2.148 29.512 75.612 ;
     RECT  29.512 2.148 29.704 75.342 ;
     RECT  29.701 0.096 29.761 0.12 ;
     RECT  29.761 0.096 30.053 0.6 ;
     RECT  29.704 2.148 30.077 8.808 ;
     RECT  30.053 0.096 30.089 0.12 ;
     RECT  30.077 1.728 30.161 8.808 ;
     RECT  30.161 1.824 30.241 8.808 ;
     RECT  30.241 2.736 30.805 8.808 ;
     RECT  29.704 9.84 30.805 75.144 ;
     RECT  30.805 2.736 30.989 75.144 ;
     RECT  30.989 2.832 31.237 75.144 ;
     RECT  31.237 2.832 31.457 75.288 ;
     RECT  31.457 2.832 31.817 46.872 ;
     RECT  31.817 2.832 31.853 46.776 ;
     RECT  31.457 55.68 31.997 75.288 ;
     RECT  31.853 31.44 32.069 46.776 ;
     RECT  31.997 55.776 32.105 75.288 ;
     RECT  32.105 57.12 32.249 75.288 ;
     RECT  31.853 2.832 32.533 30.264 ;
     RECT  32.249 73.872 32.717 75.288 ;
     RECT  32.533 2.64 32.773 30.264 ;
     RECT  32.773 2.304 32.861 30.264 ;
     RECT  32.069 31.488 32.897 46.776 ;
     RECT  32.897 46.752 33.037 46.776 ;
     RECT  31.457 47.952 33.037 54.696 ;
     RECT  33.037 46.752 33.041 54.696 ;
     RECT  32.861 2.784 33.109 30.264 ;
     RECT  32.897 31.488 33.109 45.72 ;
     RECT  32.249 57.12 33.145 72.744 ;
     RECT  32.105 55.776 33.253 55.8 ;
     RECT  33.041 47.568 33.289 54.696 ;
     RECT  33.253 55.776 33.289 55.848 ;
     RECT  33.145 56.976 33.289 72.744 ;
     RECT  33.109 2.784 33.329 45.72 ;
     RECT  32.717 73.872 33.401 74.616 ;
     RECT  33.329 26.544 33.443 45.72 ;
     RECT  33.329 2.784 33.58 25.464 ;
     RECT  33.58 2.976 33.617 25.464 ;
     RECT  33.617 2.976 33.797 25.32 ;
     RECT  33.289 47.568 33.937 72.744 ;
     RECT  33.401 73.872 33.937 74.184 ;
     RECT  33.797 2.976 34.808 9.672 ;
     RECT  33.797 10.896 34.808 25.32 ;
     RECT  33.443 26.544 34.808 45.672 ;
     RECT  33.937 47.568 34.808 74.184 ;
     RECT  34.808 2.148 34.912 75.612 ;
     RECT  34.912 2.418 35.104 75.342 ;
     RECT  35.104 46.848 35.489 72.552 ;
     RECT  35.489 46.848 36.173 70.92 ;
     RECT  36.173 46.848 36.313 68.184 ;
     RECT  35.104 3.36 36.373 45.528 ;
     RECT  36.313 46.8 36.373 68.184 ;
     RECT  36.373 3.36 36.46 68.184 ;
     RECT  36.46 3.36 36.605 45.576 ;
     RECT  36.46 46.608 36.641 68.184 ;
     RECT  36.173 69.264 36.659 70.92 ;
     RECT  35.489 72.288 36.716 72.552 ;
     RECT  36.605 3.36 36.749 34.2 ;
     RECT  36.641 46.8 36.785 68.184 ;
     RECT  35.104 73.536 36.785 75.288 ;
     RECT  36.716 72 36.803 72.552 ;
     RECT  36.785 73.536 36.821 74.856 ;
     RECT  36.785 46.848 36.893 68.184 ;
     RECT  36.605 35.184 36.929 45.576 ;
     RECT  36.893 46.848 37.109 67.848 ;
     RECT  36.803 72.288 37.109 72.552 ;
     RECT  36.659 70.656 37.217 70.92 ;
     RECT  37.109 72.528 37.285 72.552 ;
     RECT  36.821 73.536 37.285 74.664 ;
     RECT  37.285 72.528 37.331 74.664 ;
     RECT  36.659 69.264 37.393 69.528 ;
     RECT  36.749 3.648 37.397 34.2 ;
     RECT  36.929 35.328 37.619 45.576 ;
     RECT  37.397 3.696 37.753 34.2 ;
     RECT  37.619 35.424 37.825 45.576 ;
     RECT  37.109 47.088 37.933 67.848 ;
     RECT  37.393 68.976 37.933 69.528 ;
     RECT  37.933 47.088 37.937 69.528 ;
     RECT  37.825 35.424 38.113 45.816 ;
     RECT  37.937 47.088 38.113 68.28 ;
     RECT  37.937 69.264 38.257 69.528 ;
     RECT  37.217 70.704 38.257 70.92 ;
     RECT  37.753 3.696 38.473 34.248 ;
     RECT  38.473 3.456 38.581 34.248 ;
     RECT  38.113 35.424 38.581 68.28 ;
     RECT  37.331 72.768 38.581 74.664 ;
     RECT  38.581 72.432 38.653 74.664 ;
     RECT  38.257 69.264 38.689 70.92 ;
     RECT  38.653 72.048 38.689 74.664 ;
     RECT  38.581 3.456 38.716 68.28 ;
     RECT  38.716 3.456 38.761 38.184 ;
     RECT  38.761 2.496 38.845 38.184 ;
     RECT  38.689 69.264 38.869 74.664 ;
     RECT  38.716 39.6 39.085 68.28 ;
     RECT  38.869 69.264 39.085 75.192 ;
     RECT  38.845 3.408 39.197 38.184 ;
     RECT  39.085 39.6 39.229 75.192 ;
     RECT  39.197 3.408 40.093 34.392 ;
     RECT  40.093 3.072 40.208 34.392 ;
     RECT  39.197 35.424 40.208 38.184 ;
     RECT  39.229 39.6 40.208 75.288 ;
     RECT  40.208 2.148 40.312 75.612 ;
     RECT  40.312 2.418 40.504 75.342 ;
     RECT  40.504 66.048 40.637 75.288 ;
     RECT  40.504 29.568 40.643 64.968 ;
     RECT  40.504 3.072 40.673 25.512 ;
     RECT  40.643 29.568 40.925 64.872 ;
     RECT  40.673 3.072 41.105 6.312 ;
     RECT  41.105 3.072 41.141 5.064 ;
     RECT  40.925 40.416 41.177 64.872 ;
     RECT  40.673 7.344 41.213 25.512 ;
     RECT  41.177 40.608 41.213 64.872 ;
     RECT  41.213 7.344 41.249 24.504 ;
     RECT  40.504 26.592 41.321 26.616 ;
     RECT  41.141 3.072 41.393 5.016 ;
     RECT  40.504 27.6 41.569 28.536 ;
     RECT  40.925 29.568 41.569 39.336 ;
     RECT  41.213 55.44 41.605 64.872 ;
     RECT  40.637 66.048 41.605 69.384 ;
     RECT  41.213 40.608 41.645 54.408 ;
     RECT  40.637 70.368 41.681 75.288 ;
     RECT  41.393 3.072 41.749 4.776 ;
     RECT  41.569 27.6 41.749 39.336 ;
     RECT  41.213 25.488 41.785 25.512 ;
     RECT  41.249 19.104 41.788 24.504 ;
     RECT  41.749 27.456 41.825 39.336 ;
     RECT  41.749 2.784 42.001 4.776 ;
     RECT  41.605 55.44 42.077 69.384 ;
     RECT  41.825 30.384 42.145 39.336 ;
     RECT  41.645 40.608 42.149 50.328 ;
     RECT  42.001 2.544 42.185 4.776 ;
     RECT  41.249 7.344 42.185 17.784 ;
     RECT  42.185 7.344 42.227 10.872 ;
     RECT  41.105 6.288 42.257 6.312 ;
     RECT  42.185 11.856 42.265 17.784 ;
     RECT  42.227 7.344 42.275 9.72 ;
     RECT  41.788 19.824 42.293 24.504 ;
     RECT  42.185 2.544 42.365 4.2 ;
     RECT  41.785 25.488 42.433 25.704 ;
     RECT  42.149 40.608 42.509 50.136 ;
     RECT  42.433 25.008 42.541 25.704 ;
     RECT  42.145 30.384 42.545 39.384 ;
     RECT  42.265 11.856 42.611 12.984 ;
     RECT  42.293 19.824 42.611 23.736 ;
     RECT  42.275 7.344 42.617 9.672 ;
     RECT  42.265 13.968 42.649 17.784 ;
     RECT  42.577 18.768 42.649 18.792 ;
     RECT  42.611 19.824 42.653 23.64 ;
     RECT  42.541 25.008 42.721 25.896 ;
     RECT  41.825 27.456 42.721 28.824 ;
     RECT  42.227 10.704 42.725 10.872 ;
     RECT  41.681 70.512 42.757 75.288 ;
     RECT  42.545 30.384 42.865 32.328 ;
     RECT  42.725 10.848 42.869 10.872 ;
     RECT  42.865 30.336 42.901 32.328 ;
     RECT  42.649 13.968 42.905 18.792 ;
     RECT  42.653 19.824 42.949 21.528 ;
     RECT  42.721 25.008 43.013 28.824 ;
     RECT  43.013 25.056 43.049 28.824 ;
     RECT  42.757 70.416 43.049 75.288 ;
     RECT  42.949 19.392 43.085 21.528 ;
     RECT  42.077 55.488 43.117 69.384 ;
     RECT  43.049 70.416 43.117 74.712 ;
     RECT  42.365 2.736 43.189 4.2 ;
     RECT  42.793 5.232 43.189 5.256 ;
     RECT  42.901 30.048 43.189 32.328 ;
     RECT  42.545 33.648 43.189 39.384 ;
     RECT  42.509 40.608 43.189 50.04 ;
     RECT  43.049 25.056 43.193 28.2 ;
     RECT  43.189 2.736 43.261 5.256 ;
     RECT  43.261 2.736 43.265 5.832 ;
     RECT  42.617 8.208 43.301 9.672 ;
     RECT  43.117 55.488 43.309 74.712 ;
     RECT  43.189 33.648 43.373 50.04 ;
     RECT  43.309 67.392 43.373 74.712 ;
     RECT  42.905 13.968 43.441 17.976 ;
     RECT  43.373 40.272 43.475 43.464 ;
     RECT  43.189 29.376 43.517 32.328 ;
     RECT  43.373 33.648 43.517 39.24 ;
     RECT  42.611 11.856 43.585 12.408 ;
     RECT  42.653 22.656 43.585 23.64 ;
     RECT  43.517 32.256 43.621 32.328 ;
     RECT  43.475 40.272 43.697 43.32 ;
     RECT  43.085 19.824 43.727 21.528 ;
     RECT  43.585 22.656 43.727 23.88 ;
     RECT  43.265 5.808 43.729 5.832 ;
     RECT  43.585 11.76 43.729 12.408 ;
     RECT  43.621 32.256 43.82 32.472 ;
     RECT  41.645 51.456 43.837 54.408 ;
     RECT  43.441 13.584 43.868 17.976 ;
     RECT  43.82 32.256 43.907 33.24 ;
     RECT  43.729 5.808 43.909 6.696 ;
     RECT  43.301 8.208 43.909 8.232 ;
     RECT  43.517 34.224 43.913 39.24 ;
     RECT  43.729 11.76 43.945 12.504 ;
     RECT  43.868 13.584 43.945 18.216 ;
     RECT  43.837 51.312 43.945 54.408 ;
     RECT  43.945 11.76 43.949 18.216 ;
     RECT  43.949 12.048 43.954 18.216 ;
     RECT  43.265 2.736 43.985 4.44 ;
     RECT  43.301 9.648 43.985 9.672 ;
     RECT  43.373 44.448 44.021 50.04 ;
     RECT  43.954 12.048 44.057 18.264 ;
     RECT  43.907 32.256 44.057 33 ;
     RECT  43.193 25.248 44.269 28.2 ;
     RECT  43.517 29.376 44.269 30.792 ;
     RECT  43.697 40.896 44.309 43.32 ;
     RECT  43.985 3.888 44.377 4.44 ;
     RECT  43.909 5.808 44.377 8.232 ;
     RECT  44.377 3.888 44.417 8.232 ;
     RECT  44.417 5.088 44.449 8.232 ;
     RECT  43.945 51.312 44.449 54.456 ;
     RECT  43.309 55.488 44.449 66.312 ;
     RECT  44.449 5.088 44.461 8.52 ;
     RECT  44.461 5.808 44.483 8.52 ;
     RECT  44.269 25.104 44.485 30.792 ;
     RECT  44.449 51.312 44.485 66.312 ;
     RECT  43.373 67.392 44.485 74.184 ;
     RECT  43.727 19.824 44.489 23.88 ;
     RECT  44.489 22.848 44.521 23.88 ;
     RECT  44.485 25.056 44.521 30.792 ;
     RECT  44.483 7.968 44.557 8.52 ;
     RECT  44.521 22.848 44.579 30.792 ;
     RECT  44.057 12.144 44.629 18.264 ;
     RECT  44.489 19.824 44.629 21.816 ;
     RECT  44.021 48.624 44.828 50.04 ;
     RECT  44.021 44.448 44.989 47.64 ;
     RECT  44.828 48.624 44.989 50.184 ;
     RECT  44.089 10.272 45.061 10.488 ;
     RECT  43.913 34.224 45.061 39.192 ;
     RECT  44.989 44.448 45.061 50.184 ;
     RECT  44.485 51.312 45.061 74.184 ;
     RECT  44.579 30.24 45.109 30.792 ;
     RECT  45.061 10.272 45.169 11.16 ;
     RECT  44.629 12.144 45.169 21.816 ;
     RECT  44.309 41.04 45.253 43.32 ;
     RECT  45.061 44.448 45.253 74.184 ;
     RECT  44.057 32.448 45.313 33 ;
     RECT  44.417 3.888 45.457 3.912 ;
     RECT  45.061 34.224 45.457 39.24 ;
     RECT  45.253 41.04 45.457 74.184 ;
     RECT  44.783 75.408 45.457 75.432 ;
     RECT  43.985 2.736 45.608 2.856 ;
     RECT  45.457 3.888 45.608 4.152 ;
     RECT  44.483 5.808 45.608 6.648 ;
     RECT  44.557 7.968 45.608 8.856 ;
     RECT  45.169 10.272 45.608 21.816 ;
     RECT  44.579 22.848 45.608 29.064 ;
     RECT  45.109 30.24 45.608 31.032 ;
     RECT  45.313 32.208 45.608 33 ;
     RECT  45.457 34.176 45.608 39.24 ;
     RECT  45.457 41.04 45.608 75.432 ;
     RECT  45.608 2.148 45.712 75.612 ;
     RECT  45.712 2.418 45.904 75.432 ;
     RECT  45.904 5.28 46.001 12.6 ;
     RECT  45.904 31.68 46.073 75.432 ;
     RECT  46.073 31.68 46.109 75.192 ;
     RECT  46.109 40.224 46.217 75.192 ;
     RECT  45.904 14.784 46.289 29.064 ;
     RECT  45.904 2.832 46.433 4.248 ;
     RECT  46.289 14.784 46.433 25.416 ;
     RECT  46.217 48.768 46.451 75.192 ;
     RECT  46.217 40.224 46.469 47.64 ;
     RECT  46.451 53.04 46.685 75.192 ;
     RECT  46.109 31.68 46.757 39.24 ;
     RECT  46.469 40.224 46.757 47.208 ;
     RECT  46.433 14.784 46.793 16.68 ;
     RECT  46.685 54.96 46.793 75.192 ;
     RECT  46.757 32.784 46.829 39.24 ;
     RECT  46.757 40.944 46.829 47.208 ;
     RECT  46.433 17.664 46.835 25.416 ;
     RECT  46.001 9.552 46.865 12.6 ;
     RECT  46.289 26.496 46.865 29.064 ;
     RECT  46.829 44.496 46.865 47.208 ;
     RECT  46.865 26.736 46.937 29.064 ;
     RECT  45.904 30.336 47.005 30.408 ;
     RECT  46.829 40.944 47.009 43.512 ;
     RECT  46.433 3.408 47.045 4.248 ;
     RECT  46.835 17.664 47.045 21.672 ;
     RECT  47.009 40.944 47.045 41.064 ;
     RECT  47.045 17.664 47.081 19.416 ;
     RECT  46.793 55.008 47.081 75.192 ;
     RECT  47.005 30.336 47.329 30.696 ;
     RECT  47.045 20.592 47.333 21.672 ;
     RECT  46.685 53.04 47.405 53.544 ;
     RECT  47.081 55.008 47.405 71.496 ;
     RECT  46.001 5.28 47.437 8.232 ;
     RECT  46.865 44.496 47.441 47.16 ;
     RECT  47.405 53.28 47.441 53.544 ;
     RECT  46.793 16.656 47.473 16.68 ;
     RECT  47.081 17.664 47.473 18.168 ;
     RECT  47.405 55.008 47.513 70.968 ;
     RECT  47.437 4.512 47.545 8.232 ;
     RECT  46.865 9.552 47.545 11.688 ;
     RECT  46.829 35.28 47.545 39.24 ;
     RECT  47.513 55.44 47.651 70.968 ;
     RECT  46.835 22.992 47.693 25.416 ;
     RECT  47.045 3.408 47.729 3.432 ;
     RECT  47.081 72.912 47.801 75.192 ;
     RECT  46.793 14.784 47.833 15.384 ;
     RECT  47.473 16.656 47.833 18.168 ;
     RECT  47.545 35.28 47.833 39.336 ;
     RECT  47.045 40.944 47.833 41.016 ;
     RECT  47.693 22.992 47.845 23.832 ;
     RECT  47.329 30.288 47.869 30.696 ;
     RECT  46.757 31.68 47.869 31.704 ;
     RECT  46.829 32.784 47.869 34.2 ;
     RECT  46.937 26.736 47.873 29.016 ;
     RECT  47.651 55.536 47.873 70.968 ;
     RECT  47.333 20.592 47.891 21.48 ;
     RECT  47.869 30.288 47.9 34.2 ;
     RECT  47.833 35.28 47.905 39.864 ;
     RECT  47.833 40.848 47.905 41.016 ;
     RECT  47.873 57.456 47.909 70.968 ;
     RECT  46.451 48.768 47.977 51.912 ;
     RECT  47.873 26.784 48.053 29.016 ;
     RECT  47.909 57.456 48.053 67.704 ;
     RECT  47.545 4.512 48.121 11.688 ;
     RECT  47.9 30.192 48.121 34.2 ;
     RECT  47.905 35.28 48.121 41.016 ;
     RECT  48.121 30.192 48.193 41.016 ;
     RECT  48.121 0.576 48.337 0.6 ;
     RECT  48.193 30.192 48.341 41.064 ;
     RECT  48.337 0.192 48.371 0.6 ;
     RECT  48.121 4.512 48.373 11.736 ;
     RECT  48.053 27.12 48.373 29.016 ;
     RECT  48.341 30.192 48.373 30.36 ;
     RECT  48.341 33.792 48.373 41.064 ;
     RECT  47.009 42.096 48.373 43.512 ;
     RECT  47.909 68.784 48.373 70.968 ;
     RECT  48.373 4.512 48.409 11.976 ;
     RECT  47.113 13.056 48.409 13.416 ;
     RECT  47.833 14.784 48.409 18.168 ;
     RECT  47.441 53.52 48.445 53.544 ;
     RECT  48.409 14.448 48.469 18.168 ;
     RECT  47.441 44.496 48.469 46.536 ;
     RECT  47.977 48.768 48.469 52.008 ;
     RECT  48.371 0.192 48.509 0.552 ;
     RECT  48.373 33.792 48.515 43.512 ;
     RECT  47.081 19.392 48.593 19.416 ;
     RECT  48.515 40.992 48.593 43.512 ;
     RECT  47.891 20.592 48.613 20.904 ;
     RECT  48.469 14.448 48.625 18.408 ;
     RECT  48.409 4.512 48.661 13.416 ;
     RECT  48.625 14.448 48.661 19.176 ;
     RECT  48.593 43.056 48.661 43.512 ;
     RECT  48.469 44.496 48.661 52.008 ;
     RECT  48.445 52.992 48.697 53.544 ;
     RECT  47.801 72.912 48.697 74.856 ;
     RECT  48.229 1.728 48.733 1.752 ;
     RECT  48.661 43.056 48.733 52.008 ;
     RECT  48.697 52.992 48.733 53.592 ;
     RECT  48.661 4.512 48.755 19.176 ;
     RECT  48.341 31.536 48.773 31.944 ;
     RECT  48.373 68.784 48.773 71.16 ;
     RECT  48.515 33.792 48.845 39.912 ;
     RECT  47.873 55.536 48.877 56.472 ;
     RECT  48.877 54.672 48.901 56.472 ;
     RECT  48.053 63.504 48.949 67.704 ;
     RECT  48.773 68.784 48.949 69.288 ;
     RECT  48.373 27.12 48.953 30.36 ;
     RECT  48.593 40.992 49.025 41.64 ;
     RECT  48.733 25.44 49.045 25.464 ;
     RECT  48.733 1.728 49.057 1.8 ;
     RECT  48.953 28.896 49.061 30.36 ;
     RECT  49.025 41.568 49.061 41.64 ;
     RECT  48.613 20.304 49.093 20.904 ;
     RECT  48.845 36.192 49.097 39.912 ;
     RECT  49.045 25.44 49.132 25.992 ;
     RECT  49.061 29.424 49.133 30.36 ;
     RECT  47.845 22.752 49.148 23.832 ;
     RECT  49.097 36.192 49.169 38.52 ;
     RECT  48.755 5.136 49.177 19.176 ;
     RECT  49.148 22.08 49.235 23.832 ;
     RECT  48.901 54.624 49.273 56.472 ;
     RECT  48.053 57.456 49.273 62.424 ;
     RECT  48.733 43.056 49.285 53.592 ;
     RECT  49.273 54.624 49.285 62.424 ;
     RECT  49.285 43.056 49.309 62.424 ;
     RECT  48.949 63.504 49.309 69.288 ;
     RECT  48.697 72.192 49.309 74.856 ;
     RECT  49.169 36.192 49.313 38.232 ;
     RECT  48.845 33.792 49.349 34.776 ;
     RECT  48.773 31.536 49.421 31.56 ;
     RECT  49.057 1.728 49.523 2.28 ;
     RECT  49.309 43.056 49.571 69.288 ;
     RECT  49.177 5.232 49.601 19.176 ;
     RECT  49.061 41.616 49.601 41.64 ;
     RECT  48.773 70.848 49.669 71.16 ;
     RECT  49.309 72.192 49.669 74.952 ;
     RECT  49.601 18.72 49.741 19.176 ;
     RECT  49.093 20.304 49.741 20.952 ;
     RECT  49.235 22.368 49.813 23.832 ;
     RECT  49.132 25.44 49.813 25.464 ;
     RECT  49.133 29.52 49.817 30.36 ;
     RECT  49.571 43.056 49.82 45.48 ;
     RECT  49.601 5.232 49.853 17.688 ;
     RECT  49.82 42.96 49.993 45.48 ;
     RECT  49.571 46.512 49.993 69.288 ;
     RECT  49.853 5.232 49.997 17.544 ;
     RECT  49.669 70.848 50.065 74.952 ;
     RECT  49.741 18.72 50.101 20.952 ;
     RECT  49.817 29.616 50.101 30.36 ;
     RECT  49.097 39.84 50.101 39.912 ;
     RECT  49.349 33.792 50.137 33.816 ;
     RECT  49.993 46.512 50.137 69.48 ;
     RECT  50.065 70.464 50.137 74.952 ;
     RECT  48.509 0.096 50.213 0.552 ;
     RECT  49.997 5.232 50.281 17.496 ;
     RECT  49.813 22.368 50.317 25.464 ;
     RECT  48.953 27.12 50.389 27.864 ;
     RECT  50.101 29.616 50.389 30.408 ;
     RECT  50.137 46.512 50.425 74.952 ;
     RECT  50.101 18.72 50.497 21.144 ;
     RECT  50.317 22.176 50.497 25.464 ;
     RECT  49.921 3.408 50.569 3.432 ;
     RECT  50.281 4.56 50.569 17.496 ;
     RECT  50.213 0.144 50.579 0.552 ;
     RECT  50.569 3.408 50.581 17.496 ;
     RECT  50.389 29.616 50.677 31.368 ;
     RECT  50.137 33.264 50.677 33.816 ;
     RECT  50.101 34.944 50.677 34.968 ;
     RECT  50.101 39.6 50.677 39.912 ;
     RECT  50.677 33.264 50.684 34.968 ;
     RECT  50.684 33.12 50.705 34.968 ;
     RECT  49.993 42.72 50.713 45.48 ;
     RECT  50.425 46.512 50.713 75.144 ;
     RECT  49.523 1.728 50.821 1.752 ;
     RECT  50.677 39.6 50.821 40.584 ;
     RECT  50.713 42.72 50.869 75.144 ;
     RECT  49.313 36.336 50.893 38.232 ;
     RECT  50.581 2.976 51.001 17.496 ;
     RECT  50.497 18.72 51.001 25.464 ;
     RECT  50.821 39.552 51.001 40.632 ;
     RECT  50.821 1.728 51.008 1.848 ;
     RECT  51.001 2.976 51.008 25.464 ;
     RECT  50.389 26.64 51.008 27.864 ;
     RECT  50.677 29.616 51.008 31.8 ;
     RECT  50.705 33.024 51.008 34.968 ;
     RECT  50.893 36.336 51.008 38.424 ;
     RECT  51.001 39.552 51.008 40.68 ;
     RECT  50.869 42 51.008 75.144 ;
     RECT  51.008 1.728 51.112 75.612 ;
     RECT  51.112 1.728 51.304 75.342 ;
     RECT  51.304 42.336 51.401 45.48 ;
     RECT  51.304 59.232 51.437 72.456 ;
     RECT  51.304 2.736 51.587 2.76 ;
     RECT  51.304 3.984 51.635 25.464 ;
     RECT  51.304 39.552 51.689 41.256 ;
     RECT  51.689 39.552 51.725 40.776 ;
     RECT  51.304 73.536 51.725 75.144 ;
     RECT  51.437 71.904 51.797 72.456 ;
     RECT  50.579 0.144 51.865 0.504 ;
     RECT  51.865 0.144 51.901 0.6 ;
     RECT  51.437 59.232 51.905 70.92 ;
     RECT  51.901 0.144 51.973 0.696 ;
     RECT  51.304 29.616 51.977 33.384 ;
     RECT  51.304 46.56 52.049 54.6 ;
     RECT  51.725 73.536 52.049 75.096 ;
     RECT  51.304 35.04 52.085 38.424 ;
     RECT  51.973 0.096 52.115 0.696 ;
     RECT  52.049 73.776 52.121 75.096 ;
     RECT  52.049 46.56 52.193 53.448 ;
     RECT  52.121 73.776 52.193 74.664 ;
     RECT  51.304 55.968 52.268 58.2 ;
     RECT  51.905 59.232 52.268 64.44 ;
     RECT  51.797 72.144 52.297 72.456 ;
     RECT  51.304 26.592 52.405 28.392 ;
     RECT  51.635 7.104 52.409 25.464 ;
     RECT  51.304 1.728 52.441 1.752 ;
     RECT  51.401 42.336 52.441 42.744 ;
     RECT  51.401 43.824 52.441 45.48 ;
     RECT  52.441 42.336 52.445 45.48 ;
     RECT  52.193 46.56 52.481 47.976 ;
     RECT  52.441 1.152 52.525 1.752 ;
     RECT  51.725 39.552 52.553 40.68 ;
     RECT  52.268 55.968 52.553 64.44 ;
     RECT  52.409 18.288 52.585 25.464 ;
     RECT  52.405 26.592 52.585 29.064 ;
     RECT  52.085 36.576 52.585 38.424 ;
     RECT  52.553 39.552 52.585 39.576 ;
     RECT  52.525 1.248 52.595 1.752 ;
     RECT  52.049 54.48 52.604 54.6 ;
     RECT  52.553 55.968 52.604 63.24 ;
     RECT  51.635 3.984 52.621 6.12 ;
     RECT  52.409 7.104 52.621 17.208 ;
     RECT  52.445 43.296 52.645 45.48 ;
     RECT  52.481 46.56 52.645 47.832 ;
     RECT  52.645 43.296 52.691 47.832 ;
     RECT  52.604 54.48 52.691 63.24 ;
     RECT  52.595 1.728 52.729 1.752 ;
     RECT  52.691 55.968 52.733 63.24 ;
     RECT  52.693 42.048 52.873 42.168 ;
     RECT  52.729 1.728 52.979 2.28 ;
     RECT  52.553 40.608 52.981 40.68 ;
     RECT  52.873 41.76 52.981 42.168 ;
     RECT  51.905 68.784 52.981 70.92 ;
     RECT  52.297 72.144 52.981 72.696 ;
     RECT  51.905 65.52 53.017 67.704 ;
     RECT  52.981 68.784 53.017 72.696 ;
     RECT  51.977 30.336 53.021 33.384 ;
     RECT  52.621 3.984 53.084 17.208 ;
     RECT  53.029 2.88 53.221 2.904 ;
     RECT  53.084 3.888 53.221 17.208 ;
     RECT  53.021 30.336 53.233 33.288 ;
     RECT  52.585 18.288 53.267 29.064 ;
     RECT  52.193 49.536 53.305 53.448 ;
     RECT  52.553 64.224 53.305 64.44 ;
     RECT  53.017 65.52 53.305 72.696 ;
     RECT  52.733 55.968 53.309 60.36 ;
     RECT  52.085 35.04 53.377 35.064 ;
     RECT  52.981 40.608 53.485 42.168 ;
     RECT  52.691 43.296 53.485 46.104 ;
     RECT  53.305 64.224 53.521 72.696 ;
     RECT  52.193 73.776 53.521 74.472 ;
     RECT  52.979 1.728 53.593 1.8 ;
     RECT  53.377 34.656 53.653 35.064 ;
     RECT  52.585 36.576 53.653 39.576 ;
     RECT  53.309 55.968 53.665 56.088 ;
     RECT  53.593 1.152 53.677 1.8 ;
     RECT  53.305 49.008 53.701 53.448 ;
     RECT  52.691 54.48 53.701 54.6 ;
     RECT  53.665 55.824 53.701 56.088 ;
     RECT  52.733 61.344 53.737 63.24 ;
     RECT  53.521 64.224 53.737 74.472 ;
     RECT  53.221 2.88 53.741 17.208 ;
     RECT  52.115 0.096 53.773 0.12 ;
     RECT  53.485 40.608 53.809 46.104 ;
     RECT  53.701 49.008 53.813 56.088 ;
     RECT  52.691 47.184 53.845 47.832 ;
     RECT  53.773 0.096 53.857 0.6 ;
     RECT  53.741 2.88 53.921 17.16 ;
     RECT  53.309 57.072 53.921 60.36 ;
     RECT  53.921 57.12 53.989 60.36 ;
     RECT  53.737 61.344 53.989 74.472 ;
     RECT  53.813 54.576 54.029 56.088 ;
     RECT  53.653 34.656 54.061 39.576 ;
     RECT  53.809 40.608 54.061 46.152 ;
     RECT  53.989 57.12 54.133 74.472 ;
     RECT  53.233 30.096 54.169 33.288 ;
     RECT  54.133 57.12 54.209 74.568 ;
     RECT  53.267 27.888 54.229 29.064 ;
     RECT  54.169 30.096 54.229 33.672 ;
     RECT  54.029 54.576 54.317 55.848 ;
     RECT  53.267 18.288 54.349 26.76 ;
     RECT  54.229 27.888 54.349 33.672 ;
     RECT  54.061 34.656 54.353 46.152 ;
     RECT  54.349 18.288 54.389 33.672 ;
     RECT  54.353 34.656 54.389 39.816 ;
     RECT  53.677 1.728 54.433 1.8 ;
     RECT  53.921 3.024 54.467 17.16 ;
     RECT  54.209 59.136 54.529 74.568 ;
     RECT  54.467 3.024 54.641 17.064 ;
     RECT  54.389 18.48 54.709 33.672 ;
     RECT  54.389 34.656 54.709 36.6 ;
     RECT  54.641 3.024 54.749 17.016 ;
     RECT  54.529 59.136 54.749 74.664 ;
     RECT  54.749 59.568 54.785 74.664 ;
     RECT  54.353 40.848 54.821 46.152 ;
     RECT  54.317 54.576 54.997 55.8 ;
     RECT  54.785 64.368 54.997 74.664 ;
     RECT  54.997 64.368 55.069 75.048 ;
     RECT  54.821 41.04 55.105 46.152 ;
     RECT  53.845 47.184 55.105 47.976 ;
     RECT  53.813 49.008 55.177 53.448 ;
     RECT  54.997 54.528 55.177 55.8 ;
     RECT  54.709 18.48 55.187 36.6 ;
     RECT  54.785 59.568 55.189 63.384 ;
     RECT  55.069 64.368 55.283 75.144 ;
     RECT  55.177 49.008 55.325 55.8 ;
     RECT  55.187 19.776 55.357 36.6 ;
     RECT  54.389 37.92 55.357 39.816 ;
     RECT  55.105 41.04 55.357 47.976 ;
     RECT  55.325 49.008 55.357 54.6 ;
     RECT  55.357 19.776 55.397 39.816 ;
     RECT  55.397 19.776 55.433 35.784 ;
     RECT  55.187 18.48 55.753 18.744 ;
     RECT  55.397 36.96 55.861 39.816 ;
     RECT  55.357 41.04 55.861 54.6 ;
     RECT  53.857 0.096 55.865 0.552 ;
     RECT  55.189 62.832 55.933 63.384 ;
     RECT  55.283 64.368 55.933 64.392 ;
     RECT  54.433 1.728 55.969 1.752 ;
     RECT  54.749 3.024 55.969 16.872 ;
     RECT  55.969 3.024 56.077 17.112 ;
     RECT  55.753 18.432 56.077 18.744 ;
     RECT  55.865 0.144 56.225 0.552 ;
     RECT  55.189 59.568 56.293 61.752 ;
     RECT  55.933 62.832 56.293 64.392 ;
     RECT  56.293 59.568 56.329 64.392 ;
     RECT  55.969 1.728 56.408 1.848 ;
     RECT  56.077 3.024 56.408 18.744 ;
     RECT  55.433 19.776 56.408 35.352 ;
     RECT  55.861 36.96 56.408 54.6 ;
     RECT  55.325 55.776 56.408 55.8 ;
     RECT  54.209 57.12 56.408 58.152 ;
     RECT  56.329 59.52 56.408 64.392 ;
     RECT  55.283 65.424 56.408 75.144 ;
     RECT  56.408 1.728 56.512 75.612 ;
     RECT  56.512 1.728 56.704 75.342 ;
     RECT  56.225 0.24 56.819 0.552 ;
     RECT  56.704 56.016 56.909 75.144 ;
     RECT  56.704 41.04 56.981 46.104 ;
     RECT  56.909 62.4 56.981 75.144 ;
     RECT  56.704 1.728 57.017 39.912 ;
     RECT  57.017 2.736 57.169 39.912 ;
     RECT  56.819 0.528 57.203 0.552 ;
     RECT  57.169 3.024 57.233 39.912 ;
     RECT  57.233 3.024 57.305 21.72 ;
     RECT  57.233 22.848 57.341 39.912 ;
     RECT  56.981 41.184 57.521 46.104 ;
     RECT  57.521 45.456 57.733 46.104 ;
     RECT  56.704 47.184 57.733 54.936 ;
     RECT  57.341 34.176 57.809 39.912 ;
     RECT  56.909 56.016 57.913 61.224 ;
     RECT  56.981 62.4 57.913 75 ;
     RECT  57.913 56.016 57.953 75 ;
     RECT  57.809 34.224 58.169 39.912 ;
     RECT  57.953 56.016 58.169 59.256 ;
     RECT  58.169 56.016 58.201 58.968 ;
     RECT  57.953 60.24 58.204 75 ;
     RECT  57.341 22.848 58.309 32.808 ;
     RECT  57.305 20.064 58.345 21.72 ;
     RECT  58.309 22.704 58.345 32.808 ;
     RECT  57.305 3.024 58.489 18.744 ;
     RECT  58.345 20.064 58.489 32.808 ;
     RECT  58.489 3.024 58.493 32.808 ;
     RECT  57.521 41.184 58.525 44.472 ;
     RECT  57.733 45.456 58.525 54.936 ;
     RECT  58.201 55.92 58.525 58.968 ;
     RECT  58.417 0.528 58.589 0.552 ;
     RECT  58.525 41.184 58.637 58.968 ;
     RECT  58.493 28.176 58.669 32.808 ;
     RECT  58.169 39.6 58.693 39.912 ;
     RECT  58.637 41.184 58.693 44.472 ;
     RECT  58.204 60.624 58.709 75 ;
     RECT  58.709 60.624 58.732 69.72 ;
     RECT  58.693 39.6 58.781 44.472 ;
     RECT  58.669 28.176 58.835 33.096 ;
     RECT  58.637 45.456 58.853 58.968 ;
     RECT  58.169 34.224 59.069 38.28 ;
     RECT  58.853 45.456 59.105 51.432 ;
     RECT  59.105 45.456 59.267 48.408 ;
     RECT  58.589 0.096 59.281 0.552 ;
     RECT  58.781 41.568 59.293 44.472 ;
     RECT  58.853 52.512 59.321 57.864 ;
     RECT  59.293 41.856 59.357 44.472 ;
     RECT  59.069 34.416 59.389 38.28 ;
     RECT  58.781 39.6 59.389 40.2 ;
     RECT  58.835 28.224 59.465 33.096 ;
     RECT  59.105 49.44 59.465 51.432 ;
     RECT  59.465 30.048 59.537 33.096 ;
     RECT  59.357 41.856 59.555 44.136 ;
     RECT  59.281 0.096 59.603 0.6 ;
     RECT  59.321 52.56 59.681 57.864 ;
     RECT  58.732 64.848 59.713 69.72 ;
     RECT  58.709 70.752 59.713 75 ;
     RECT  59.465 28.224 59.789 29.064 ;
     RECT  59.555 41.856 59.825 43.272 ;
     RECT  59.681 54.048 59.857 57.864 ;
     RECT  58.853 58.944 59.857 58.968 ;
     RECT  58.732 60.624 59.897 63.816 ;
     RECT  57.017 1.728 59.931 1.752 ;
     RECT  59.537 30.048 59.933 30.408 ;
     RECT  59.931 1.728 59.965 1.8 ;
     RECT  59.537 31.44 59.965 33.096 ;
     RECT  59.897 60.624 59.965 60.696 ;
     RECT  59.857 54.048 59.996 58.968 ;
     RECT  59.389 34.416 60.005 40.2 ;
     RECT  58.493 3.024 60.077 26.856 ;
     RECT  60.077 20.016 60.109 26.856 ;
     RECT  59.713 64.848 60.113 75 ;
     RECT  59.965 31.44 60.14 33.432 ;
     RECT  60.005 34.416 60.14 35.064 ;
     RECT  59.603 0.096 60.179 0.552 ;
     RECT  59.996 54.048 60.181 59.208 ;
     RECT  59.965 60.48 60.181 60.696 ;
     RECT  60.14 31.44 60.185 35.064 ;
     RECT  60.113 73.92 60.289 75 ;
     RECT  60.005 36.096 60.325 40.2 ;
     RECT  60.325 36.096 60.361 40.44 ;
     RECT  59.825 41.856 60.361 42.984 ;
     RECT  60.361 36.096 60.371 42.984 ;
     RECT  60.371 40.416 60.467 42.984 ;
     RECT  60.467 41.712 60.563 42.984 ;
     RECT  59.267 45.744 60.613 48.408 ;
     RECT  59.681 52.56 60.649 53.064 ;
     RECT  60.181 54.048 60.649 60.696 ;
     RECT  60.613 45.024 60.661 48.408 ;
     RECT  59.465 49.44 60.721 50.088 ;
     RECT  59.465 51.072 60.721 51.432 ;
     RECT  59.965 1.728 60.797 1.848 ;
     RECT  59.789 28.272 60.805 29.064 ;
     RECT  59.933 30.048 60.805 30.072 ;
     RECT  60.179 0.096 60.851 0.12 ;
     RECT  59.897 62.16 60.865 63.816 ;
     RECT  60.661 44.976 60.901 48.408 ;
     RECT  60.721 49.44 60.901 51.432 ;
     RECT  60.901 44.976 60.937 51.432 ;
     RECT  60.649 52.56 61.009 60.696 ;
     RECT  61.009 52.464 61.045 60.696 ;
     RECT  60.109 20.016 61.153 27.24 ;
     RECT  60.805 28.272 61.153 30.072 ;
     RECT  61.045 52.464 61.153 60.888 ;
     RECT  60.077 3.024 61.237 19.032 ;
     RECT  61.153 20.016 61.237 30.072 ;
     RECT  61.153 52.464 61.261 60.936 ;
     RECT  60.865 61.968 61.261 63.816 ;
     RECT  60.185 31.44 61.297 35.016 ;
     RECT  60.371 36.096 61.297 38.76 ;
     RECT  60.797 1.728 61.331 1.8 ;
     RECT  61.261 52.464 61.405 63.816 ;
     RECT  60.113 64.848 61.405 72.744 ;
     RECT  61.237 3.024 61.441 30.072 ;
     RECT  60.937 44.88 61.477 51.432 ;
     RECT  61.405 52.464 61.477 72.744 ;
     RECT  60.289 73.92 61.477 75.384 ;
     RECT  61.441 2.832 61.513 30.072 ;
     RECT  61.513 2.832 61.585 30.12 ;
     RECT  61.297 31.44 61.585 38.76 ;
     RECT  60.563 41.712 61.585 42.168 ;
     RECT  61.477 44.16 61.585 51.432 ;
     RECT  61.585 43.776 61.729 51.432 ;
     RECT  61.477 52.464 61.729 75.384 ;
     RECT  61.585 2.832 61.808 38.76 ;
     RECT  60.467 40.416 61.808 40.632 ;
     RECT  61.585 41.712 61.808 42.264 ;
     RECT  61.729 43.776 61.808 75.384 ;
     RECT  61.808 2.148 61.912 75.612 ;
     RECT  61.912 2.418 62.104 75.342 ;
     RECT  62.104 2.64 62.237 30.696 ;
     RECT  62.104 31.776 62.381 39.912 ;
     RECT  62.104 70.8 62.381 75 ;
     RECT  62.104 41.712 62.489 47.64 ;
     RECT  62.237 14.64 62.597 30.696 ;
     RECT  62.597 15.024 62.849 30.696 ;
     RECT  62.849 15.024 62.993 26.808 ;
     RECT  62.849 28.032 62.993 30.696 ;
     RECT  62.237 2.64 63.029 13.608 ;
     RECT  62.381 31.776 63.029 39.816 ;
     RECT  62.489 41.76 63.037 47.64 ;
     RECT  63.037 43.68 63.097 47.64 ;
     RECT  62.104 48.768 63.097 50.28 ;
     RECT  62.993 28.08 63.133 30.696 ;
     RECT  62.104 51.408 63.137 65.736 ;
     RECT  62.104 67.296 63.137 69.48 ;
     RECT  63.133 28.08 63.173 30.936 ;
     RECT  63.037 41.76 63.173 42.696 ;
     RECT  63.137 53.472 63.205 65.736 ;
     RECT  63.173 42.48 63.209 42.696 ;
     RECT  63.097 43.68 63.313 50.28 ;
     RECT  63.205 53.472 63.349 65.928 ;
     RECT  63.137 67.296 63.349 69.288 ;
     RECT  63.313 43.68 63.385 50.424 ;
     RECT  63.137 51.408 63.385 52.2 ;
     RECT  63.029 32.016 63.389 39.816 ;
     RECT  63.389 32.016 63.461 36.984 ;
     RECT  63.029 2.64 63.565 12.888 ;
     RECT  62.381 70.896 63.745 75 ;
     RECT  62.993 15.024 63.853 26.76 ;
     RECT  63.853 13.92 63.893 26.76 ;
     RECT  63.461 32.4 63.893 36.984 ;
     RECT  63.385 43.68 64.001 52.2 ;
     RECT  63.893 24.192 64.033 26.76 ;
     RECT  64.021 27.888 64.033 27.912 ;
     RECT  63.173 28.992 64.037 30.936 ;
     RECT  64.033 24.192 64.115 27.912 ;
     RECT  64.115 27.552 64.117 27.912 ;
     RECT  63.893 13.92 64.181 23.16 ;
     RECT  63.745 70.704 64.249 75 ;
     RECT  64.181 13.92 64.259 22.488 ;
     RECT  63.349 53.472 64.285 69.288 ;
     RECT  64.249 70.608 64.285 75 ;
     RECT  64.037 30.816 64.429 30.936 ;
     RECT  63.893 32.4 64.429 35.352 ;
     RECT  63.389 38.304 64.429 38.904 ;
     RECT  63.209 42.48 64.537 42.504 ;
     RECT  64.001 43.68 64.537 52.008 ;
     RECT  64.259 13.92 64.649 22.344 ;
     RECT  64.285 53.472 64.649 75 ;
     RECT  64.649 60.672 64.721 75 ;
     RECT  64.681 41.472 64.753 41.496 ;
     RECT  64.649 53.472 64.789 59.592 ;
     RECT  64.789 53.04 64.793 59.592 ;
     RECT  64.429 30.816 64.897 35.352 ;
     RECT  64.721 72.24 64.933 75 ;
     RECT  64.753 41.424 64.981 41.496 ;
     RECT  64.537 42.48 64.981 52.008 ;
     RECT  64.117 27.888 65.005 27.912 ;
     RECT  64.037 28.992 65.005 29.736 ;
     RECT  64.429 38.16 65.005 38.904 ;
     RECT  63.421 40.128 65.005 40.152 ;
     RECT  63.565 2.256 65.009 12.888 ;
     RECT  64.115 24.192 65.081 26.28 ;
     RECT  65.005 27.888 65.117 29.736 ;
     RECT  65.005 38.16 65.149 40.152 ;
     RECT  64.981 41.424 65.149 52.008 ;
     RECT  65.117 27.888 65.153 29.688 ;
     RECT  65.009 2.592 65.173 12.888 ;
     RECT  64.649 13.92 65.173 20.76 ;
     RECT  65.149 38.16 65.297 52.008 ;
     RECT  65.297 38.16 65.315 48.216 ;
     RECT  65.297 49.488 65.365 52.008 ;
     RECT  64.793 53.04 65.365 59.496 ;
     RECT  64.897 30.816 65.401 35.4 ;
     RECT  63.893 36.432 65.401 36.984 ;
     RECT  65.173 2.592 65.405 20.76 ;
     RECT  65.365 49.488 65.405 59.496 ;
     RECT  65.405 49.488 65.441 54.744 ;
     RECT  65.405 55.728 65.441 59.496 ;
     RECT  65.081 25.968 65.653 26.28 ;
     RECT  65.315 38.16 65.657 38.52 ;
     RECT  64.649 21.792 65.725 22.344 ;
     RECT  65.315 39.6 65.765 48.216 ;
     RECT  65.153 28.032 65.801 29.688 ;
     RECT  65.441 59.28 65.843 59.496 ;
     RECT  65.401 30.816 65.873 36.984 ;
     RECT  65.873 35.328 65.977 36.984 ;
     RECT  65.843 59.328 66.013 59.496 ;
     RECT  64.721 60.672 66.013 71.112 ;
     RECT  65.653 25.968 66.157 26.664 ;
     RECT  65.801 28.032 66.157 29.544 ;
     RECT  65.765 41.472 66.161 48.216 ;
     RECT  65.441 53.472 66.161 54.744 ;
     RECT  65.441 49.488 66.301 52.488 ;
     RECT  66.157 25.968 66.325 29.544 ;
     RECT  65.081 24.192 66.337 24.744 ;
     RECT  66.325 25.728 66.337 29.544 ;
     RECT  66.013 59.328 66.337 71.112 ;
     RECT  64.933 72.24 66.337 75.24 ;
     RECT  66.337 59.328 66.481 71.208 ;
     RECT  66.337 72.24 66.481 75.384 ;
     RECT  66.161 53.616 66.517 54.744 ;
     RECT  65.441 55.728 66.517 58.152 ;
     RECT  65.405 2.592 66.553 14.76 ;
     RECT  65.405 15.936 66.553 20.76 ;
     RECT  65.725 21.792 66.553 22.824 ;
     RECT  66.337 24.192 66.625 29.544 ;
     RECT  65.657 38.16 66.661 38.184 ;
     RECT  65.765 39.6 66.805 40.152 ;
     RECT  66.161 41.472 66.805 47.736 ;
     RECT  65.873 30.816 66.877 34.152 ;
     RECT  66.805 39.6 67.021 47.736 ;
     RECT  66.625 23.904 67.057 29.544 ;
     RECT  67.057 23.856 67.165 29.544 ;
     RECT  66.877 30.672 67.165 34.152 ;
     RECT  65.977 35.328 67.165 37.128 ;
     RECT  66.661 38.16 67.165 38.28 ;
     RECT  66.553 2.592 67.201 22.824 ;
     RECT  67.201 2.256 67.208 22.824 ;
     RECT  67.165 23.856 67.208 34.152 ;
     RECT  67.165 35.328 67.208 38.28 ;
     RECT  67.021 39.312 67.208 47.736 ;
     RECT  66.301 48.72 67.208 52.488 ;
     RECT  66.517 53.616 67.208 58.152 ;
     RECT  66.481 59.328 67.208 75.384 ;
     RECT  67.208 2.148 67.312 75.612 ;
     RECT  67.312 2.256 67.504 75.342 ;
     RECT  67.504 31.776 67.601 75.24 ;
     RECT  67.601 31.776 67.667 63.816 ;
     RECT  67.667 31.776 67.673 50.424 ;
     RECT  67.504 2.256 67.781 23.928 ;
     RECT  67.597 76.368 67.885 76.392 ;
     RECT  67.885 76.368 68.005 76.92 ;
     RECT  67.781 2.256 68.105 22.2 ;
     RECT  67.504 25.248 68.357 27.096 ;
     RECT  67.667 51.408 68.393 63.816 ;
     RECT  67.601 64.896 68.429 75.24 ;
     RECT  67.504 28.224 68.465 30.696 ;
     RECT  68.393 53.088 68.483 63.816 ;
     RECT  67.781 23.28 68.569 23.928 ;
     RECT  68.357 25.968 68.569 27.096 ;
     RECT  68.483 53.088 68.573 58.728 ;
     RECT  68.573 53.136 68.675 58.728 ;
     RECT  68.675 55.824 68.716 58.728 ;
     RECT  68.465 28.224 68.717 29.064 ;
     RECT  68.716 56.016 68.717 58.728 ;
     RECT  68.105 2.256 68.789 22.008 ;
     RECT  68.429 64.944 68.789 75.24 ;
     RECT  68.717 56.016 68.867 58.68 ;
     RECT  68.465 30.192 68.929 30.696 ;
     RECT  67.673 31.968 68.929 50.424 ;
     RECT  68.569 23.28 68.965 24.12 ;
     RECT  68.789 67.248 68.965 75.24 ;
     RECT  68.005 76.368 68.965 77.64 ;
     RECT  68.717 28.224 68.969 28.728 ;
     RECT  68.867 56.064 69.005 58.68 ;
     RECT  68.965 23.28 69.011 24.648 ;
     RECT  68.965 67.248 69.011 77.64 ;
     RECT  68.929 30.192 69.037 50.424 ;
     RECT  68.393 51.408 69.037 52.008 ;
     RECT  69.037 30.192 69.041 52.008 ;
     RECT  68.483 59.76 69.041 63.816 ;
     RECT  69.011 67.248 69.041 75.912 ;
     RECT  68.789 2.592 69.145 22.008 ;
     RECT  69.011 23.28 69.145 23.4 ;
     RECT  69.145 2.592 69.149 23.4 ;
     RECT  69.041 41.568 69.221 52.008 ;
     RECT  69.149 2.592 69.251 14.184 ;
     RECT  69.149 15.312 69.299 23.4 ;
     RECT  68.675 53.136 69.329 54.648 ;
     RECT  69.041 67.296 69.329 75.912 ;
     RECT  69.299 15.312 69.34 22.2 ;
     RECT  69.005 56.448 69.395 58.68 ;
     RECT  69.041 60.336 69.401 63.816 ;
     RECT  69.011 24.624 69.505 24.648 ;
     RECT  68.569 25.968 69.505 27.192 ;
     RECT  69.329 53.136 69.577 54.456 ;
     RECT  69.299 23.328 69.581 23.4 ;
     RECT  69.221 41.952 69.581 52.008 ;
     RECT  69.041 30.192 69.683 40.392 ;
     RECT  69.329 67.632 69.779 75.912 ;
     RECT  69.683 30.192 69.781 35.352 ;
     RECT  69.581 42.48 69.793 52.008 ;
     RECT  69.577 53.04 69.793 54.456 ;
     RECT  69.793 42.48 69.797 54.456 ;
     RECT  69.683 36.384 69.833 40.392 ;
     RECT  69.011 76.944 69.875 77.64 ;
     RECT  69.34 21.36 69.985 22.2 ;
     RECT  68.789 64.944 70.009 66.216 ;
     RECT  68.969 28.224 70.069 28.392 ;
     RECT  69.781 29.472 70.069 35.352 ;
     RECT  69.401 60.48 70.076 63.816 ;
     RECT  70.009 64.944 70.076 66.504 ;
     RECT  69.251 2.592 70.157 14.136 ;
     RECT  69.505 24.624 70.157 27.192 ;
     RECT  70.157 2.64 70.211 14.136 ;
     RECT  69.797 45.6 70.229 54.456 ;
     RECT  70.081 59.232 70.307 59.256 ;
     RECT  70.211 5.424 70.309 14.136 ;
     RECT  69.34 15.312 70.309 20.376 ;
     RECT  70.076 60.48 70.348 66.504 ;
     RECT  70.229 45.6 70.409 53.16 ;
     RECT  70.069 28.224 70.441 35.352 ;
     RECT  70.211 2.64 70.445 4.2 ;
     RECT  70.441 27.84 70.481 35.352 ;
     RECT  70.409 45.792 70.481 53.16 ;
     RECT  69.797 42.48 70.499 44.472 ;
     RECT  70.499 42.48 70.517 44.232 ;
     RECT  69.779 67.632 70.589 75.624 ;
     RECT  70.309 5.424 70.625 20.376 ;
     RECT  70.157 24.624 70.625 26.76 ;
     RECT  70.625 24.624 70.643 26.232 ;
     RECT  69.395 56.448 70.657 58.152 ;
     RECT  70.229 54.144 70.693 54.456 ;
     RECT  70.657 55.776 70.693 58.776 ;
     RECT  69.833 36.528 70.697 40.392 ;
     RECT  70.643 24.912 70.733 25.992 ;
     RECT  70.445 2.832 70.769 4.2 ;
     RECT  70.589 67.632 70.805 75.384 ;
     RECT  69.581 23.328 70.837 23.352 ;
     RECT  70.481 32.064 70.837 35.352 ;
     RECT  70.697 36.528 70.837 36.696 ;
     RECT  70.348 60.576 70.837 66.504 ;
     RECT  70.837 23.328 70.877 23.592 ;
     RECT  70.625 14.688 71.017 20.376 ;
     RECT  69.985 21.36 71.017 21.816 ;
     RECT  70.837 32.064 71.129 36.696 ;
     RECT  70.481 27.84 71.197 31.032 ;
     RECT  69.875 77.52 71.309 77.64 ;
     RECT  71.309 77.616 71.345 77.64 ;
     RECT  70.697 37.824 71.377 40.392 ;
     RECT  70.693 54.144 71.377 58.776 ;
     RECT  71.017 14.688 71.417 21.816 ;
     RECT  71.377 37.824 71.449 40.488 ;
     RECT  70.625 5.424 71.521 13.512 ;
     RECT  70.837 60.576 71.521 67.32 ;
     RECT  70.517 42.48 71.557 43.896 ;
     RECT  71.129 36.528 71.561 36.696 ;
     RECT  70.769 2.832 71.593 4.008 ;
     RECT  71.593 2.256 71.633 4.008 ;
     RECT  71.449 37.824 71.665 40.872 ;
     RECT  71.557 42.48 71.665 43.944 ;
     RECT  70.733 25.152 71.809 25.992 ;
     RECT  71.197 27.6 71.809 31.032 ;
     RECT  71.129 32.064 71.809 35.16 ;
     RECT  71.665 37.824 71.845 43.944 ;
     RECT  71.521 5.232 71.881 13.512 ;
     RECT  71.881 5.04 71.989 13.512 ;
     RECT  71.417 14.688 71.989 19.704 ;
     RECT  71.417 21.168 71.989 21.816 ;
     RECT  71.989 21.168 72.025 22.056 ;
     RECT  70.877 23.376 72.025 23.592 ;
     RECT  71.809 25.152 72.169 35.16 ;
     RECT  70.481 46.752 72.205 53.16 ;
     RECT  71.377 54.144 72.205 59.256 ;
     RECT  71.845 37.104 72.277 44.472 ;
     RECT  71.521 60.432 72.325 67.32 ;
     RECT  70.805 68.352 72.325 75.384 ;
     RECT  72.277 37.104 72.373 45 ;
     RECT  72.373 37.104 72.385 45.288 ;
     RECT  72.205 46.752 72.385 59.256 ;
     RECT  71.989 5.04 72.421 19.704 ;
     RECT  72.025 21.168 72.421 23.592 ;
     RECT  72.169 25.056 72.565 35.784 ;
     RECT  72.565 24.96 72.601 35.784 ;
     RECT  71.633 2.256 72.608 3.72 ;
     RECT  72.421 5.04 72.608 23.592 ;
     RECT  72.601 24.96 72.608 35.832 ;
     RECT  72.385 37.104 72.608 59.256 ;
     RECT  72.325 60.432 72.608 75.384 ;
     RECT  72.608 2.148 72.712 75.612 ;
     RECT  72.712 2.418 72.904 75.342 ;
     RECT  72.904 2.592 72.929 4.056 ;
     RECT  72.904 21.408 73.037 23.736 ;
     RECT  72.904 39.504 73.109 56.328 ;
     RECT  73.109 39.504 73.145 45.24 ;
     RECT  72.904 5.136 73.181 9.624 ;
     RECT  73.037 21.792 73.217 23.736 ;
     RECT  72.904 61.104 73.253 75.192 ;
     RECT  73.253 61.104 73.283 65.688 ;
     RECT  73.109 46.656 73.372 56.328 ;
     RECT  73.253 66.672 73.433 75.192 ;
     RECT  73.145 39.504 73.469 41.4 ;
     RECT  73.433 70.032 73.469 75.192 ;
     RECT  73.145 42.48 73.541 45.24 ;
     RECT  73.541 42.48 73.577 43.368 ;
     RECT  73.372 46.704 73.613 56.328 ;
     RECT  72.904 26.592 73.721 34.488 ;
     RECT  73.613 47.856 73.793 56.328 ;
     RECT  73.541 44.448 73.829 45.24 ;
     RECT  72.904 25.44 73.897 25.464 ;
     RECT  73.283 61.104 73.933 65.16 ;
     RECT  73.181 5.184 73.937 9.624 ;
     RECT  73.217 23.712 73.937 23.736 ;
     RECT  72.904 10.8 73.969 15.864 ;
     RECT  72.904 16.848 73.969 18.984 ;
     RECT  73.721 30.576 74.005 34.488 ;
     RECT  72.904 35.712 74.005 38.424 ;
     RECT  73.613 46.704 74.045 46.872 ;
     RECT  73.937 8.16 74.077 9.624 ;
     RECT  73.897 25.296 74.113 25.464 ;
     RECT  73.469 39.6 74.113 41.4 ;
     RECT  73.577 42.48 74.113 43.032 ;
     RECT  72.929 2.832 74.149 4.056 ;
     RECT  73.937 5.184 74.149 6.936 ;
     RECT  72.904 20.304 74.149 20.328 ;
     RECT  73.969 10.8 74.185 18.984 ;
     RECT  74.077 8.16 74.195 9.72 ;
     RECT  73.721 26.592 74.261 29.592 ;
     RECT  74.005 30.576 74.261 38.424 ;
     RECT  74.149 20.208 74.365 20.328 ;
     RECT  73.793 47.856 74.369 53.112 ;
     RECT  74.261 30.816 74.387 38.424 ;
     RECT  73.793 54.24 74.437 56.328 ;
     RECT  72.904 57.36 74.437 59.256 ;
     RECT  73.469 70.128 74.437 75.192 ;
     RECT  73.933 60.336 74.485 65.16 ;
     RECT  74.365 20.208 74.509 20.568 ;
     RECT  73.829 44.496 74.509 45.24 ;
     RECT  74.149 2.832 74.549 6.936 ;
     RECT  73.433 66.672 74.617 69 ;
     RECT  74.437 70.128 74.617 75.24 ;
     RECT  74.387 31.344 74.621 38.424 ;
     RECT  74.485 60.336 74.621 65.688 ;
     RECT  74.185 10.704 74.629 18.984 ;
     RECT  74.509 20.064 74.629 20.568 ;
     RECT  74.113 25.296 74.653 25.56 ;
     RECT  74.261 26.592 74.653 27.432 ;
     RECT  74.629 10.704 74.693 20.568 ;
     RECT  74.437 54.24 74.693 59.256 ;
     RECT  74.549 4.416 74.765 6.936 ;
     RECT  74.369 51.408 74.801 53.112 ;
     RECT  74.509 44.496 74.819 45.768 ;
     RECT  74.113 39.6 74.821 43.032 ;
     RECT  74.821 39.504 74.909 43.032 ;
     RECT  74.693 19.92 74.917 20.568 ;
     RECT  73.217 21.792 74.917 22.68 ;
     RECT  74.045 46.848 74.941 46.872 ;
     RECT  74.369 47.856 74.941 50.28 ;
     RECT  74.113 24.096 74.963 24.12 ;
     RECT  74.941 46.848 74.981 50.28 ;
     RECT  74.917 19.92 75.017 23.016 ;
     RECT  74.909 39.6 75.053 43.032 ;
     RECT  75.053 39.744 75.085 43.032 ;
     RECT  74.621 60.96 75.085 65.688 ;
     RECT  74.617 66.672 75.085 75.24 ;
     RECT  74.981 46.848 75.193 49.272 ;
     RECT  74.621 31.728 75.269 38.424 ;
     RECT  74.693 54.384 75.269 59.256 ;
     RECT  75.085 60.96 75.299 75.24 ;
     RECT  75.299 61.344 75.305 75.24 ;
     RECT  74.653 25.296 75.337 27.432 ;
     RECT  74.261 28.56 75.337 29.592 ;
     RECT  75.305 61.344 75.377 72.936 ;
     RECT  75.337 25.056 75.493 27.432 ;
     RECT  75.337 28.464 75.493 29.592 ;
     RECT  75.269 31.728 75.521 37.992 ;
     RECT  75.493 25.056 75.541 29.592 ;
     RECT  75.017 22.848 75.625 23.016 ;
     RECT  75.017 19.92 75.665 21.816 ;
     RECT  74.693 10.704 75.697 18.792 ;
     RECT  75.665 19.92 75.697 20.904 ;
     RECT  75.377 61.344 75.701 72.456 ;
     RECT  74.765 6.672 75.733 6.936 ;
     RECT  74.195 8.16 75.733 9.672 ;
     RECT  75.625 22.848 75.733 23.112 ;
     RECT  75.269 54.768 75.769 59.256 ;
     RECT  75.733 6.672 75.881 9.672 ;
     RECT  75.521 32.16 75.953 37.992 ;
     RECT  75.701 61.344 75.953 71.928 ;
     RECT  74.549 2.832 75.973 3.432 ;
     RECT  74.765 4.416 75.973 5.304 ;
     RECT  75.193 46.752 75.98 49.272 ;
     RECT  74.981 50.256 75.98 50.28 ;
     RECT  75.733 22.848 75.985 23.352 ;
     RECT  75.973 2.832 76.021 5.304 ;
     RECT  75.541 25.056 76.025 29.64 ;
     RECT  75.769 54.768 76.025 60.072 ;
     RECT  75.98 46.752 76.067 50.28 ;
     RECT  75.881 7.968 76.069 9.672 ;
     RECT  75.697 10.704 76.069 20.904 ;
     RECT  76.025 25.056 76.129 28.488 ;
     RECT  76.069 7.968 76.205 20.904 ;
     RECT  75.953 33.552 76.205 37.992 ;
     RECT  76.021 2.832 76.237 5.496 ;
     RECT  75.881 6.672 76.237 6.696 ;
     RECT  75.985 21.936 76.309 23.352 ;
     RECT  76.129 24.384 76.309 28.488 ;
     RECT  74.819 44.736 76.309 45.768 ;
     RECT  76.067 46.752 76.309 49.032 ;
     RECT  75.305 74.016 76.313 75.24 ;
     RECT  74.801 51.408 76.381 53.016 ;
     RECT  76.025 54.768 76.381 58.68 ;
     RECT  76.313 74.016 76.381 74.136 ;
     RECT  76.313 75.216 76.381 75.24 ;
     RECT  76.381 73.776 76.405 74.136 ;
     RECT  76.205 36.576 76.417 37.992 ;
     RECT  76.205 33.552 76.421 35.544 ;
     RECT  76.309 44.448 76.421 49.032 ;
     RECT  75.953 61.44 76.421 71.928 ;
     RECT  76.381 75.216 76.451 75.576 ;
     RECT  76.405 72.912 76.493 74.136 ;
     RECT  76.451 75.552 76.499 75.576 ;
     RECT  76.309 76.848 76.525 76.872 ;
     RECT  75.953 32.304 76.565 32.328 ;
     RECT  76.421 61.44 76.565 71.688 ;
     RECT  76.381 51.408 76.601 58.68 ;
     RECT  76.525 76.848 76.633 76.92 ;
     RECT  76.237 2.832 76.669 6.696 ;
     RECT  76.633 76.8 76.7 76.92 ;
     RECT  76.417 36.576 76.709 38.472 ;
     RECT  76.7 76.8 76.813 76.968 ;
     RECT  76.493 73.008 76.853 74.136 ;
     RECT  76.421 33.552 76.921 34.2 ;
     RECT  76.025 60.048 76.921 60.072 ;
     RECT  76.565 61.44 76.921 63.24 ;
     RECT  76.309 21.936 76.925 28.488 ;
     RECT  76.813 75.792 76.925 76.968 ;
     RECT  76.921 33.312 76.957 34.2 ;
     RECT  76.067 50.256 76.957 50.28 ;
     RECT  76.601 51.408 76.957 52.296 ;
     RECT  76.421 47.424 77.173 49.032 ;
     RECT  76.957 50.256 77.173 52.296 ;
     RECT  76.925 75.84 77.221 76.968 ;
     RECT  76.669 2.496 77.317 6.696 ;
     RECT  76.205 7.968 77.317 20.712 ;
     RECT  76.925 21.936 77.317 23.4 ;
     RECT  77.221 75.84 77.317 77.544 ;
     RECT  76.601 53.856 77.324 58.68 ;
     RECT  76.921 60.048 77.324 63.24 ;
     RECT  76.421 35.328 77.389 35.544 ;
     RECT  76.709 36.576 77.389 37.08 ;
     RECT  76.025 29.568 77.425 29.64 ;
     RECT  77.173 47.424 77.497 52.296 ;
     RECT  76.565 64.32 77.533 71.688 ;
     RECT  76.853 73.008 77.533 73.128 ;
     RECT  77.324 53.856 77.641 63.24 ;
     RECT  77.533 64.32 77.641 73.128 ;
     RECT  76.709 38.448 77.749 38.472 ;
     RECT  76.421 44.448 77.821 45.816 ;
     RECT  77.497 46.8 77.821 52.296 ;
     RECT  77.749 38.448 77.929 38.76 ;
     RECT  77.317 75.84 77.957 77.64 ;
     RECT  77.317 2.496 78.008 23.4 ;
     RECT  76.925 24.384 78.008 28.488 ;
     RECT  77.425 29.568 78.008 30.168 ;
     RECT  76.957 32.976 78.008 34.2 ;
     RECT  77.389 35.328 78.008 37.08 ;
     RECT  77.929 38.16 78.008 38.76 ;
     RECT  75.085 39.744 78.008 43.272 ;
     RECT  77.821 44.448 78.008 52.296 ;
     RECT  77.641 53.856 78.008 73.128 ;
     RECT  76.853 74.112 78.008 74.136 ;
     RECT  77.957 75.792 78.008 77.64 ;
     RECT  78.008 2.148 78.112 77.64 ;
     RECT  78.112 2.418 78.304 75.342 ;
     RECT  78.304 54.864 78.365 59.064 ;
     RECT  78.304 21.696 78.437 28.488 ;
     RECT  78.304 46.512 78.437 49.32 ;
     RECT  78.304 31.152 78.473 31.464 ;
     RECT  78.304 32.544 78.473 35.544 ;
     RECT  78.112 76.368 78.473 77.64 ;
     RECT  78.437 46.512 78.545 49.08 ;
     RECT  78.304 6.048 78.581 17.64 ;
     RECT  78.304 36.72 78.581 42.792 ;
     RECT  78.304 64.08 78.659 72.984 ;
     RECT  78.437 21.696 78.689 28.2 ;
     RECT  78.304 60.048 78.761 61.032 ;
     RECT  78.304 29.568 78.797 30.168 ;
     RECT  78.473 31.152 78.797 31.368 ;
     RECT  78.581 37.056 78.797 42.792 ;
     RECT  78.473 76.368 78.841 76.392 ;
     RECT  78.304 2.496 78.899 4.776 ;
     RECT  78.581 6.288 78.905 17.64 ;
     RECT  78.545 46.512 78.905 48.936 ;
     RECT  78.899 3.024 78.941 4.776 ;
     RECT  78.304 43.824 78.947 45.24 ;
     RECT  78.304 50.304 78.988 53.832 ;
     RECT  78.905 6.288 79.121 14.664 ;
     RECT  78.797 37.056 79.121 42.552 ;
     RECT  78.761 60.048 79.121 60.984 ;
     RECT  78.304 18.672 79.149 20.712 ;
     RECT  79.121 40.32 79.193 42.552 ;
     RECT  78.941 3.408 79.229 4.776 ;
     RECT  78.304 74.304 79.229 75.342 ;
     RECT  79.121 7.728 79.265 14.664 ;
     RECT  78.988 50.64 79.265 53.832 ;
     RECT  79.265 7.92 79.283 14.664 ;
     RECT  78.689 21.84 79.283 28.2 ;
     RECT  78.659 71.664 79.297 72.984 ;
     RECT  79.229 74.304 79.297 74.328 ;
     RECT  79.229 3.792 79.337 4.776 ;
     RECT  79.283 8.592 79.337 14.664 ;
     RECT  78.473 77.424 79.337 77.64 ;
     RECT  78.905 15.984 79.369 17.64 ;
     RECT  79.149 18.672 79.369 18.84 ;
     RECT  79.337 3.792 79.373 3.912 ;
     RECT  79.283 24.096 79.436 28.2 ;
     RECT  78.473 32.544 79.475 35.352 ;
     RECT  79.436 24.096 79.477 28.44 ;
     RECT  78.797 29.568 79.477 29.688 ;
     RECT  79.121 60.816 79.481 60.984 ;
     RECT  79.297 71.664 79.481 74.328 ;
     RECT  79.481 60.912 79.517 60.984 ;
     RECT  79.121 37.056 79.633 39.336 ;
     RECT  79.265 50.688 79.669 53.832 ;
     RECT  78.365 54.864 79.669 58.68 ;
     RECT  79.373 3.792 79.697 3.816 ;
     RECT  79.633 38.736 79.697 39.336 ;
     RECT  79.149 19.92 79.724 20.712 ;
     RECT  79.283 21.84 79.724 22.872 ;
     RECT  79.475 32.544 79.729 34.344 ;
     RECT  78.905 46.512 79.729 48.792 ;
     RECT  78.304 62.16 79.729 62.856 ;
     RECT  79.337 77.424 79.733 77.592 ;
     RECT  79.237 75.552 79.769 75.816 ;
     RECT  79.517 60.96 79.801 60.984 ;
     RECT  79.729 62.16 79.801 63.048 ;
     RECT  79.697 38.928 79.805 39.336 ;
     RECT  79.769 75.792 79.805 75.816 ;
     RECT  79.337 9.072 79.841 14.664 ;
     RECT  79.805 38.928 79.841 39.24 ;
     RECT  79.841 10.224 79.873 14.664 ;
     RECT  79.669 50.688 79.877 58.68 ;
     RECT  78.797 31.152 79.913 31.176 ;
     RECT  79.729 32.448 79.913 34.344 ;
     RECT  78.947 43.824 79.945 44.712 ;
     RECT  79.841 9.072 79.985 9.24 ;
     RECT  79.801 60.96 80.005 63.048 ;
     RECT  78.659 64.08 80.005 70.68 ;
     RECT  80.005 60.96 80.051 70.68 ;
     RECT  79.945 43.344 80.053 45 ;
     RECT  79.729 46.032 80.053 48.792 ;
     RECT  79.121 6.288 80.089 6.36 ;
     RECT  80.053 43.344 80.093 48.792 ;
     RECT  79.724 19.92 80.129 22.872 ;
     RECT  79.837 59.808 80.147 59.832 ;
     RECT  79.193 40.32 80.161 42.168 ;
     RECT  80.051 60.96 80.165 64.008 ;
     RECT  80.089 6.288 80.233 6.408 ;
     RECT  79.475 35.328 80.305 35.352 ;
     RECT  79.633 37.056 80.305 37.656 ;
     RECT  79.913 32.496 80.309 34.344 ;
     RECT  79.985 9.072 80.377 9.096 ;
     RECT  79.877 50.688 80.387 58.632 ;
     RECT  80.305 35.328 80.417 37.656 ;
     RECT  80.093 43.344 80.417 48.696 ;
     RECT  80.165 61.536 80.417 64.008 ;
     RECT  79.733 77.52 80.417 77.592 ;
     RECT  80.051 65.808 80.489 70.68 ;
     RECT  80.417 35.328 80.525 36.264 ;
     RECT  80.387 50.688 80.525 54.984 ;
     RECT  80.387 56.208 80.525 58.632 ;
     RECT  80.233 6.288 80.557 6.84 ;
     RECT  80.161 40.32 80.561 42.216 ;
     RECT  79.369 15.984 80.588 18.84 ;
     RECT  80.557 6.288 80.597 7.368 ;
     RECT  80.525 53.424 80.597 54.984 ;
     RECT  79.873 10.224 80.629 14.808 ;
     RECT  80.588 15.84 80.629 18.84 ;
     RECT  79.477 24.096 80.629 29.688 ;
     RECT  80.597 6.288 80.741 6.312 ;
     RECT  80.129 21.504 80.773 22.872 ;
     RECT  80.629 24.096 80.773 30.072 ;
     RECT  80.629 10.224 80.777 18.84 ;
     RECT  80.417 43.344 80.813 48.6 ;
     RECT  80.561 40.32 80.845 42.12 ;
     RECT  80.845 40.272 80.849 42.12 ;
     RECT  80.813 45.552 80.849 48.6 ;
     RECT  80.489 66.048 80.869 70.68 ;
     RECT  79.481 71.664 80.869 73.848 ;
     RECT  80.417 77.52 80.885 77.544 ;
     RECT  80.869 66.048 80.915 73.848 ;
     RECT  79.841 38.928 80.917 39 ;
     RECT  80.525 50.688 80.917 52.392 ;
     RECT  80.849 40.272 80.921 40.44 ;
     RECT  80.377 8.496 80.989 9.096 ;
     RECT  80.777 10.224 80.989 15.336 ;
     RECT  80.989 8.496 80.993 15.336 ;
     RECT  80.309 32.496 80.993 33.912 ;
     RECT  80.417 62.208 81.013 64.008 ;
     RECT  80.773 21.504 81.097 30.072 ;
     RECT  81.013 59.856 81.1 60.216 ;
     RECT  80.915 66.048 81.209 72.984 ;
     RECT  81.097 21.504 81.245 30.744 ;
     RECT  81.209 66.048 81.251 72.408 ;
     RECT  81.013 62.208 81.281 64.968 ;
     RECT  80.993 33.024 81.299 33.912 ;
     RECT  80.813 43.344 81.317 44.232 ;
     RECT  80.917 50.4 81.397 52.392 ;
     RECT  80.129 19.92 81.421 20.328 ;
     RECT  81.245 21.504 81.421 27.912 ;
     RECT  81.299 33.504 81.421 33.912 ;
     RECT  80.525 35.328 81.421 35.352 ;
     RECT  81.397 50.064 81.421 52.392 ;
     RECT  80.525 57.072 81.445 58.632 ;
     RECT  81.1 59.856 81.445 59.88 ;
     RECT  81.445 57.072 81.532 59.88 ;
     RECT  80.777 16.368 81.533 18.84 ;
     RECT  81.421 19.92 81.533 27.912 ;
     RECT  81.245 28.944 81.533 30.744 ;
     RECT  81.533 20.928 81.539 27.912 ;
     RECT  80.597 54.144 81.637 54.984 ;
     RECT  81.532 57.072 81.637 58.488 ;
     RECT  81.281 62.784 81.637 64.968 ;
     RECT  81.251 66.048 81.637 66.072 ;
     RECT  80.993 8.544 81.641 15.336 ;
     RECT  81.251 67.248 81.677 72.408 ;
     RECT  81.641 8.88 81.713 15.336 ;
     RECT  81.637 56.304 81.724 58.488 ;
     RECT  81.533 19.92 81.745 19.944 ;
     RECT  81.533 16.368 81.749 18.216 ;
     RECT  81.637 62.784 81.785 66.072 ;
     RECT  81.713 9.6 81.821 15.336 ;
     RECT  81.785 65.232 81.821 66.072 ;
     RECT  80.917 38.928 81.853 39.24 ;
     RECT  80.921 40.272 81.853 40.344 ;
     RECT  81.637 54.144 81.857 55.224 ;
     RECT  81.853 38.784 81.889 40.344 ;
     RECT  81.889 38.4 81.997 40.344 ;
     RECT  81.821 9.696 82.001 15.336 ;
     RECT  81.724 57.072 82.001 58.488 ;
     RECT  81.997 38.16 82.021 40.344 ;
     RECT  82.001 9.696 82.037 10.824 ;
     RECT  81.539 22.176 82.067 27.912 ;
     RECT  82.021 38.16 82.067 40.392 ;
     RECT  81.677 67.776 82.067 72.408 ;
     RECT  81.421 33.504 82.069 35.352 ;
     RECT  82.067 67.776 82.073 71.784 ;
     RECT  80.597 7.344 82.109 7.368 ;
     RECT  81.785 62.784 82.145 64.008 ;
     RECT  81.749 16.368 82.163 17.4 ;
     RECT  82.073 69.36 82.181 71.784 ;
     RECT  81.532 59.712 82.213 59.88 ;
     RECT  81.421 49.44 82.217 52.392 ;
     RECT  82.067 23.376 82.253 27.912 ;
     RECT  82.217 52.272 82.253 52.392 ;
     RECT  82.001 12.096 82.259 15.336 ;
     RECT  82.163 16.368 82.259 17.016 ;
     RECT  82.253 26.928 82.259 27.912 ;
     RECT  80.849 45.552 82.268 48.312 ;
     RECT  82.217 49.44 82.268 50.76 ;
     RECT  80.849 41.472 82.285 42.12 ;
     RECT  82.069 33.504 82.289 35.832 ;
     RECT  81.857 54.144 82.316 54.168 ;
     RECT  82.001 57.552 82.325 58.488 ;
     RECT  81.317 43.824 82.349 44.232 ;
     RECT  82.268 45.552 82.349 50.76 ;
     RECT  82.349 43.824 82.355 50.76 ;
     RECT  82.253 52.272 82.361 52.296 ;
     RECT  82.145 62.784 82.397 63.816 ;
     RECT  82.355 43.872 82.403 48.312 ;
     RECT  82.316 53.568 82.403 54.168 ;
     RECT  82.259 15.072 82.429 15.336 ;
     RECT  82.285 41.472 82.433 42.312 ;
     RECT  81.997 61.44 82.433 61.464 ;
     RECT  81.857 55.2 82.46 55.224 ;
     RECT  82.067 40.272 82.465 40.392 ;
     RECT  82.433 41.472 82.465 42.12 ;
     RECT  81.745 19.68 82.573 19.944 ;
     RECT  81.539 20.928 82.573 20.952 ;
     RECT  82.573 19.68 82.645 20.952 ;
     RECT  82.364 37.056 82.645 37.08 ;
     RECT  82.645 37.008 82.681 37.08 ;
     RECT  82.067 38.16 82.681 39.096 ;
     RECT  82.289 33.504 82.717 33.96 ;
     RECT  82.645 18.816 82.796 20.952 ;
     RECT  82.213 59.712 83.029 60.216 ;
     RECT  81.821 65.616 83.029 66.072 ;
     RECT  83.029 65.136 83.084 66.072 ;
     RECT  83.029 59.712 83.113 60.312 ;
     RECT  82.037 9.696 83.408 9.72 ;
     RECT  82.037 10.8 83.408 10.824 ;
     RECT  82.259 12.096 83.408 13.944 ;
     RECT  82.429 15.072 83.408 15.912 ;
     RECT  82.259 16.896 83.408 17.016 ;
     RECT  82.796 18.816 83.408 21 ;
     RECT  82.067 22.176 83.408 22.392 ;
     RECT  82.253 23.376 83.408 25.8 ;
     RECT  82.259 27.36 83.408 27.912 ;
     RECT  81.533 28.944 83.408 30.072 ;
     RECT  82.357 31.2 83.408 31.224 ;
     RECT  82.717 33.072 83.408 33.96 ;
     RECT  82.289 35.328 83.408 35.832 ;
     RECT  82.681 37.008 83.408 39.096 ;
     RECT  82.465 40.272 83.408 42.12 ;
     RECT  82.403 43.872 83.408 45.576 ;
     RECT  82.403 46.56 83.408 48.312 ;
     RECT  82.355 49.536 83.408 50.76 ;
     RECT  82.403 54.144 83.408 54.168 ;
     RECT  82.46 55.2 83.408 55.896 ;
     RECT  82.501 58.512 83.408 58.536 ;
     RECT  83.113 59.712 83.408 61.032 ;
     RECT  82.397 62.784 83.408 63.288 ;
     RECT  83.084 64.944 83.408 66.072 ;
     RECT  82.073 67.776 83.408 68.376 ;
     RECT  82.181 69.36 83.408 71.4 ;
     RECT  83.408 2.148 83.512 75.612 ;
     RECT  83.512 2.418 83.704 75.342 ;
    LAYER M5 ;
     RECT  29.712 0.016 30.216 0.131 ;
     RECT  29.808 0.131 30.216 0.611 ;
     RECT  48.336 0.016 61.32 0.611 ;
     RECT  48.432 0.611 61.32 1.763 ;
     RECT  13.008 0.016 19.08 1.811 ;
     RECT  48.912 1.763 61.32 1.811 ;
     RECT  13.008 1.811 18.912 1.859 ;
     RECT  30.096 0.611 30.216 1.859 ;
     RECT  49.2 1.811 61.32 2.137 ;
     RECT  2.4 2.137 2.52 2.151 ;
     RECT  7.8 2.137 7.92 2.151 ;
     RECT  24 2.137 24.12 2.151 ;
     RECT  34.8 2.137 34.92 2.151 ;
     RECT  40.2 2.137 40.32 2.151 ;
     RECT  45.6 2.137 45.72 2.151 ;
     RECT  49.2 2.137 61.92 2.151 ;
     RECT  67.2 2.137 67.32 2.151 ;
     RECT  72.6 2.137 72.72 2.151 ;
     RECT  78 2.137 78.12 2.151 ;
     RECT  83.4 2.137 83.52 2.151 ;
     RECT  24 2.151 24.312 2.245 ;
     RECT  49.2 2.151 62.112 2.291 ;
     RECT  7.8 2.151 8.112 2.293 ;
     RECT  78 2.151 78.312 2.485 ;
     RECT  67.2 2.151 67.512 2.581 ;
     RECT  49.776 2.291 62.112 2.629 ;
     RECT  13.008 1.859 14.472 2.677 ;
     RECT  32.784 2.293 32.808 2.773 ;
     RECT  69.456 2.677 69.48 2.773 ;
     RECT  2.4 2.151 2.712 2.821 ;
     RECT  64.416 2.629 64.44 3.013 ;
     RECT  69.456 2.773 70.2 3.157 ;
     RECT  10.8 2.245 10.824 3.299 ;
     RECT  34.8 2.151 35.112 3.349 ;
     RECT  7.68 2.293 8.112 3.397 ;
     RECT  12.048 2.677 14.472 3.397 ;
     RECT  29.4 2.137 29.712 3.397 ;
     RECT  40.2 2.151 40.512 3.397 ;
     RECT  49.776 2.629 62.808 3.443 ;
     RECT  76.8 2.485 76.824 3.443 ;
     RECT  38.784 2.485 38.808 3.685 ;
     RECT  38.16 3.685 38.808 3.731 ;
     RECT  2.4 2.821 2.904 3.875 ;
     RECT  65.568 2.821 65.592 3.875 ;
     RECT  11.376 3.397 14.472 3.925 ;
     RECT  15.696 1.859 18.912 3.925 ;
     RECT  11.376 3.925 18.912 3.971 ;
     RECT  72.6 2.151 72.912 3.973 ;
     RECT  13.008 3.971 18.912 4.019 ;
     RECT  58.992 3.443 62.808 4.019 ;
     RECT  59.328 4.019 62.808 4.069 ;
     RECT  63.84 3.013 64.44 4.069 ;
     RECT  59.328 4.069 64.44 4.115 ;
     RECT  24 2.245 24.408 4.213 ;
     RECT  18.24 4.019 18.912 4.261 ;
     RECT  29.4 3.397 29.88 4.261 ;
     RECT  67.104 2.581 67.512 4.453 ;
     RECT  32.784 2.773 33.528 4.501 ;
     RECT  75.984 3.877 76.008 4.501 ;
     RECT  7.68 3.397 8.808 4.549 ;
     RECT  13.008 4.019 17.256 4.595 ;
     RECT  49.776 3.443 57.384 4.595 ;
     RECT  64.416 4.115 64.44 4.643 ;
     RECT  49.776 4.595 57.336 4.691 ;
     RECT  78 2.485 78.888 4.691 ;
     RECT  49.776 4.691 51.624 4.739 ;
     RECT  27.936 3.157 27.96 4.837 ;
     RECT  38.16 3.731 38.184 4.885 ;
     RECT  29.4 4.261 30.264 4.933 ;
     RECT  31.296 3.925 31.32 4.933 ;
     RECT  38.16 4.885 38.664 4.981 ;
     RECT  18.24 4.261 19.032 5.077 ;
     RECT  38.16 4.981 38.808 5.123 ;
     RECT  48.72 4.501 48.744 5.125 ;
     RECT  49.776 4.739 51.576 5.125 ;
     RECT  38.16 5.123 38.664 5.171 ;
     RECT  40.2 3.397 40.872 5.171 ;
     RECT  52.656 4.691 57.336 5.171 ;
     RECT  72.6 3.973 73.08 5.171 ;
     RECT  75.984 4.501 76.056 5.171 ;
     RECT  72.6 5.171 72.912 5.173 ;
     RECT  2.4 3.875 2.808 5.219 ;
     RECT  21.648 5.077 21.672 5.221 ;
     RECT  18.24 5.077 19.8 5.365 ;
     RECT  21.072 5.221 21.672 5.365 ;
     RECT  24 4.213 24.456 5.413 ;
     RECT  48.72 5.125 51.576 5.461 ;
     RECT  18.24 5.365 21.672 5.507 ;
     RECT  76.032 5.171 76.056 5.507 ;
     RECT  10.896 4.885 10.92 5.603 ;
     RECT  47.904 5.461 51.576 5.603 ;
     RECT  67.104 4.453 67.608 5.603 ;
     RECT  13.2 4.595 17.256 5.605 ;
     RECT  18.24 5.507 21.144 5.605 ;
     RECT  52.752 5.171 57.336 5.605 ;
     RECT  13.008 5.605 21.144 5.653 ;
     RECT  36.96 5.557 36.984 5.701 ;
     RECT  27.936 4.837 28.344 5.747 ;
     RECT  48.72 5.603 51.576 5.747 ;
     RECT  34.8 3.349 35.352 5.795 ;
     RECT  36.96 5.701 37.032 5.797 ;
     RECT  36.864 5.797 37.032 5.843 ;
     RECT  44.4 5.077 44.424 5.891 ;
     RECT  52.752 5.605 57.864 5.893 ;
     RECT  59.328 4.115 63.096 5.893 ;
     RECT  72.24 5.173 72.912 5.987 ;
     RECT  52.752 5.893 63.096 6.037 ;
     RECT  11.76 5.989 11.784 6.085 ;
     RECT  12.912 5.653 21.144 6.085 ;
     RECT  72.48 5.987 72.912 6.229 ;
     RECT  74.304 3.301 74.328 6.229 ;
     RECT  78 4.691 78.312 6.229 ;
     RECT  38.64 5.171 38.664 6.277 ;
     RECT  7.44 4.549 8.808 6.323 ;
     RECT  72.48 6.229 74.328 6.323 ;
     RECT  52.752 6.037 63.624 6.371 ;
     RECT  69.072 3.157 70.2 6.373 ;
     RECT  23.472 5.413 24.456 6.421 ;
     RECT  25.632 5.989 25.656 6.421 ;
     RECT  28.32 5.747 28.344 6.565 ;
     RECT  29.4 4.933 31.32 6.565 ;
     RECT  23.472 6.421 25.656 6.659 ;
     RECT  49.776 5.747 51.576 6.661 ;
     RECT  67.104 5.603 67.512 6.709 ;
     RECT  77.472 6.229 78.312 6.757 ;
     RECT  28.32 6.565 31.32 6.803 ;
     RECT  7.8 6.323 8.808 6.805 ;
     RECT  48.72 5.747 48.744 6.805 ;
     RECT  49.776 6.661 51.624 6.805 ;
     RECT  69.072 6.373 70.824 6.851 ;
     RECT  32.784 4.501 33.624 6.899 ;
     RECT  69.072 6.851 70.776 6.899 ;
     RECT  11.76 6.085 21.144 7.189 ;
     RECT  72.48 6.323 74.28 7.237 ;
     RECT  43.92 6.661 43.944 7.333 ;
     RECT  53.184 6.371 63.624 7.333 ;
     RECT  23.472 6.659 24.408 7.379 ;
     RECT  43.92 7.333 44.472 7.379 ;
     RECT  2.4 5.219 2.712 7.381 ;
     RECT  33.6 6.899 33.624 7.381 ;
     RECT  34.8 5.795 35.112 7.381 ;
     RECT  67.104 6.709 67.608 7.381 ;
     RECT  69.072 6.899 69.24 7.381 ;
     RECT  77.424 6.757 78.312 7.381 ;
     RECT  5.664 5.653 5.688 7.475 ;
     RECT  48.72 6.805 51.624 7.669 ;
     RECT  52.752 7.333 63.624 7.669 ;
     RECT  70.56 6.899 70.776 7.811 ;
     RECT  25.632 6.659 25.656 7.907 ;
     RECT  77.328 7.381 78.744 7.909 ;
     RECT  22.464 6.133 22.488 7.957 ;
     RECT  23.472 7.379 24.312 7.957 ;
     RECT  28.32 6.803 28.344 7.957 ;
     RECT  27.936 7.957 28.344 8.003 ;
     RECT  44.448 7.379 44.472 8.003 ;
     RECT  65.568 6.661 65.592 8.003 ;
     RECT  72.384 7.237 74.28 8.195 ;
     RECT  48.72 7.669 63.624 8.245 ;
     RECT  67.104 7.381 69.24 8.245 ;
     RECT  33.6 7.381 35.112 8.291 ;
     RECT  38.64 6.277 38.76 8.485 ;
     RECT  40.2 5.171 40.512 8.485 ;
     RECT  48.72 8.245 63.72 8.485 ;
     RECT  42.24 8.437 42.264 8.533 ;
     RECT  66.912 8.245 69.24 8.533 ;
     RECT  2.4 7.381 2.808 8.579 ;
     RECT  11.76 7.189 21.24 8.675 ;
     RECT  7.8 6.805 9.432 8.723 ;
     RECT  77.328 7.909 79.272 8.723 ;
     RECT  36.864 5.843 36.984 8.771 ;
     RECT  41.808 8.533 42.264 8.821 ;
     RECT  29.4 6.803 31.32 8.867 ;
     RECT  66.72 8.533 69.24 8.867 ;
     RECT  66.72 8.867 67.512 8.917 ;
     RECT  36.864 8.771 36.888 8.965 ;
     RECT  77.328 8.723 78.744 8.965 ;
     RECT  6.576 7.957 6.6 9.011 ;
     RECT  26.4 8.965 26.424 9.061 ;
     RECT  76.896 8.965 78.744 9.061 ;
     RECT  48.72 8.485 63.768 9.107 ;
     RECT  68.544 8.867 69.24 9.107 ;
     RECT  76.368 9.061 78.744 9.107 ;
     RECT  34.032 8.291 35.112 9.155 ;
     RECT  22.464 7.957 24.312 9.253 ;
     RECT  22.464 9.253 24.792 9.443 ;
     RECT  72.384 8.195 74.184 9.493 ;
     RECT  45.6 2.151 45.912 9.541 ;
     RECT  22.464 9.443 24.504 9.635 ;
     RECT  72 9.493 74.184 9.635 ;
     RECT  29.4 8.867 30.744 9.637 ;
     RECT  76.368 9.107 78.312 9.637 ;
     RECT  26.4 9.061 26.664 9.683 ;
     RECT  83.4 2.151 83.712 9.685 ;
     RECT  11.76 8.675 20.472 9.731 ;
     RECT  22.464 9.635 22.488 9.731 ;
     RECT  66.432 8.917 67.512 9.731 ;
     RECT  74.16 9.635 74.184 9.731 ;
     RECT  81.168 8.821 81.192 9.731 ;
     RECT  36.096 8.965 36.888 9.779 ;
     RECT  69.168 9.107 69.24 9.779 ;
     RECT  29.28 9.637 30.744 9.829 ;
     RECT  7.8 8.723 8.808 10.021 ;
     RECT  48.72 9.107 59.352 10.067 ;
     RECT  34.8 9.155 35.112 10.069 ;
     RECT  70.56 7.811 70.728 10.163 ;
     RECT  65.376 9.301 65.4 10.259 ;
     RECT  72 9.635 72.912 10.307 ;
     RECT  26.64 9.683 26.664 10.405 ;
     RECT  27.936 8.003 27.96 10.405 ;
     RECT  7.8 10.021 9.096 10.451 ;
     RECT  50.112 10.067 59.352 10.451 ;
     RECT  58.944 10.451 59.352 10.501 ;
     RECT  60.336 9.107 63.768 10.501 ;
     RECT  26.64 10.405 27.96 10.643 ;
     RECT  48.72 10.067 49.08 10.787 ;
     RECT  36.864 9.779 36.888 10.789 ;
     RECT  82.56 9.685 83.712 10.835 ;
     RECT  41.808 8.821 42.792 10.883 ;
     RECT  58.944 10.501 63.768 10.883 ;
     RECT  76.08 9.637 78.312 10.883 ;
     RECT  77.232 10.883 78.312 11.125 ;
     RECT  29.28 9.829 31.608 11.171 ;
     RECT  45.6 9.541 46.728 11.171 ;
     RECT  5.472 10.405 5.496 11.317 ;
     RECT  2.4 8.579 2.712 11.365 ;
     RECT  34.8 10.069 35.352 11.365 ;
     RECT  66.72 9.731 67.512 11.365 ;
     RECT  58.944 10.883 63.288 11.459 ;
     RECT  5.184 11.317 5.496 11.507 ;
     RECT  64.992 10.789 65.016 11.507 ;
     RECT  41.808 10.883 42.216 11.603 ;
     RECT  26.64 10.643 26.664 11.653 ;
     RECT  7.8 10.451 8.112 11.797 ;
     RECT  42.192 11.603 42.216 11.845 ;
     RECT  80.64 11.317 80.664 11.845 ;
     RECT  38.64 8.485 40.512 11.941 ;
     RECT  49.056 10.787 49.08 11.941 ;
     RECT  69.168 9.779 69.192 11.941 ;
     RECT  70.56 10.163 70.584 11.941 ;
     RECT  79.92 11.845 80.664 11.941 ;
     RECT  29.4 11.171 31.608 11.989 ;
     RECT  36.432 10.789 36.888 12.035 ;
     RECT  33.936 11.365 35.352 12.083 ;
     RECT  7.392 11.797 8.112 12.181 ;
     RECT  69.12 11.941 69.192 12.227 ;
     RECT  42.192 11.845 42.6 12.373 ;
     RECT  33.936 12.083 35.208 12.515 ;
     RECT  48.96 11.941 49.08 12.515 ;
     RECT  66.72 11.365 67.848 12.515 ;
     RECT  50.112 10.451 57.864 12.517 ;
     RECT  58.944 11.459 59.352 12.517 ;
     RECT  60.768 11.459 63.288 12.517 ;
     RECT  2.4 11.365 3.576 12.563 ;
     RECT  79.92 11.941 81.528 12.563 ;
     RECT  45.6 11.171 46.68 12.611 ;
     RECT  80.4 12.563 81.528 12.613 ;
     RECT  83.4 10.835 83.712 12.613 ;
     RECT  2.4 12.563 2.712 12.757 ;
     RECT  29.4 11.989 31.848 12.803 ;
     RECT  49.056 12.515 49.08 12.805 ;
     RECT  50.112 12.517 64.152 12.805 ;
     RECT  42.192 12.373 42.984 12.853 ;
     RECT  49.056 12.805 64.152 12.947 ;
     RECT  26.112 11.653 26.664 12.995 ;
     RECT  45.6 12.611 45.912 13.045 ;
     RECT  65.328 12.517 65.352 13.045 ;
     RECT  7.392 12.181 8.28 13.091 ;
     RECT  27.936 10.643 27.96 13.093 ;
     RECT  69.12 12.227 69.144 13.093 ;
     RECT  70.32 11.941 70.584 13.093 ;
     RECT  34.56 12.515 35.208 13.139 ;
     RECT  41.568 12.853 42.984 13.139 ;
     RECT  49.584 12.947 64.152 13.139 ;
     RECT  31.776 12.803 31.848 13.141 ;
     RECT  31.776 13.141 32.376 13.187 ;
     RECT  77.232 11.125 78.696 13.331 ;
     RECT  9.504 11.941 9.528 13.333 ;
     RECT  38.256 11.941 40.512 13.379 ;
     RECT  70.32 13.093 70.728 13.381 ;
     RECT  72.336 10.307 72.912 13.381 ;
     RECT  49.584 13.139 58.968 13.427 ;
     RECT  69.072 13.093 69.144 13.477 ;
     RECT  70.32 13.381 72.912 13.477 ;
     RECT  69.072 13.477 72.912 13.523 ;
     RECT  9.504 13.333 10.392 13.571 ;
     RECT  80.4 12.613 83.712 13.619 ;
     RECT  65.328 13.045 65.544 13.621 ;
     RECT  76.08 10.883 76.104 13.621 ;
     RECT  77.472 13.331 78.696 13.667 ;
     RECT  41.616 13.139 42.984 13.715 ;
     RECT  29.4 12.803 30.792 14.051 ;
     RECT  60.768 13.139 64.152 14.099 ;
     RECT  65.184 13.621 65.544 14.197 ;
     RECT  11.76 9.731 20.424 14.243 ;
     RECT  44.736 13.045 45.912 14.243 ;
     RECT  60.768 14.099 63.288 14.245 ;
     RECT  2.304 12.757 2.712 14.339 ;
     RECT  26.64 12.995 26.664 14.533 ;
     RECT  77.472 13.667 78.312 14.723 ;
     RECT  69.072 13.523 71.496 14.725 ;
     RECT  49.584 13.427 58.536 14.771 ;
     RECT  66.96 12.515 67.848 14.771 ;
     RECT  5.472 11.507 5.496 14.773 ;
     RECT  26.496 14.533 26.664 14.821 ;
     RECT  27.936 13.093 28.296 14.867 ;
     RECT  49.584 14.771 57.336 14.867 ;
     RECT  59.808 14.245 63.288 14.867 ;
     RECT  34.56 13.139 35.112 14.869 ;
     RECT  49.584 14.867 52.824 14.963 ;
     RECT  34.56 14.869 35.304 15.011 ;
     RECT  38.736 13.379 40.512 15.205 ;
     RECT  58.464 14.771 58.536 15.251 ;
     RECT  7.8 13.091 8.28 15.253 ;
     RECT  44.976 14.243 45.912 15.443 ;
     RECT  75.792 13.621 76.104 15.443 ;
     RECT  29.4 14.051 30.744 15.445 ;
     RECT  68.928 14.725 71.496 15.445 ;
     RECT  72.48 13.523 72.912 15.445 ;
     RECT  34.56 15.011 35.112 15.491 ;
     RECT  60.048 14.867 63.288 15.491 ;
     RECT  21.456 11.941 21.48 15.541 ;
     RECT  74.064 15.349 74.088 15.541 ;
     RECT  36.864 12.035 36.888 15.589 ;
     RECT  38.064 15.205 40.512 15.589 ;
     RECT  36.864 15.589 40.512 15.637 ;
     RECT  11.76 14.243 14.856 15.731 ;
     RECT  21.456 15.541 21.72 15.731 ;
     RECT  74.064 15.541 74.616 15.779 ;
     RECT  23.472 9.635 24.312 15.829 ;
     RECT  64.512 14.197 65.544 15.829 ;
     RECT  7.152 15.253 8.28 15.923 ;
     RECT  49.584 14.963 52.776 15.925 ;
     RECT  54.048 14.867 57.336 15.925 ;
     RECT  68.928 15.445 72.912 15.971 ;
     RECT  11.76 15.731 14.808 15.973 ;
     RECT  77.568 14.723 78.312 15.973 ;
     RECT  16.08 14.243 20.424 16.019 ;
     RECT  74.064 15.779 74.088 16.019 ;
     RECT  29.088 15.445 30.744 16.021 ;
     RECT  31.824 13.187 32.376 16.021 ;
     RECT  27.936 14.867 27.96 16.069 ;
     RECT  29.04 16.021 30.744 16.069 ;
     RECT  23.472 15.829 25.08 16.115 ;
     RECT  31.824 16.021 32.76 16.163 ;
     RECT  60.048 15.491 62.808 16.163 ;
     RECT  71.472 15.971 72.912 16.259 ;
     RECT  42.96 13.715 42.984 16.261 ;
     RECT  31.824 16.163 32.328 16.309 ;
     RECT  80.64 13.619 83.712 16.403 ;
     RECT  31.728 16.309 32.328 16.451 ;
     RECT  7.8 15.923 8.28 16.453 ;
     RECT  27.936 16.069 30.744 16.501 ;
     RECT  31.728 16.451 32.088 16.501 ;
     RECT  67.2 14.771 67.848 16.501 ;
     RECT  10.944 15.973 14.808 16.547 ;
     RECT  41.616 13.715 41.64 16.595 ;
     RECT  34.8 15.491 35.112 16.597 ;
     RECT  49.584 15.925 57.336 16.645 ;
     RECT  26.4 14.821 26.664 16.789 ;
     RECT  5.472 14.773 5.736 16.835 ;
     RECT  45.504 15.443 45.912 16.979 ;
     RECT  60.432 16.163 62.808 16.981 ;
     RECT  63.888 15.829 65.544 16.981 ;
     RECT  26.352 16.789 26.664 17.027 ;
     RECT  23.472 16.115 24.312 17.029 ;
     RECT  60.432 16.981 65.544 17.029 ;
     RECT  7.8 16.453 8.472 17.077 ;
     RECT  9.504 13.571 9.528 17.077 ;
     RECT  77.568 15.973 79.032 17.077 ;
     RECT  58.8 15.589 58.824 17.125 ;
     RECT  60.432 17.029 65.592 17.125 ;
     RECT  26.4 17.027 26.664 17.171 ;
     RECT  11.76 16.547 14.808 17.173 ;
     RECT  16.08 16.019 16.2 17.173 ;
     RECT  23.04 17.029 24.312 17.173 ;
     RECT  27.936 16.501 32.088 17.219 ;
     RECT  34.8 16.597 35.256 17.315 ;
     RECT  81.168 16.403 83.712 17.315 ;
     RECT  7.8 17.077 10.728 17.363 ;
     RECT  34.8 17.315 35.208 17.411 ;
     RECT  82.128 17.315 83.712 17.411 ;
     RECT  11.76 17.173 16.2 17.459 ;
     RECT  68.928 15.971 70.44 17.459 ;
     RECT  48.624 16.645 57.336 17.461 ;
     RECT  71.472 16.259 71.496 17.461 ;
     RECT  72.48 16.259 72.912 17.461 ;
     RECT  5.472 16.835 5.496 17.509 ;
     RECT  58.8 17.125 65.592 17.509 ;
     RECT  71.472 17.461 72.912 17.605 ;
     RECT  48.48 17.461 57.336 17.699 ;
     RECT  67.2 16.501 67.944 17.699 ;
     RECT  27.936 17.219 27.96 17.795 ;
     RECT  21.456 15.731 21.48 17.845 ;
     RECT  76.08 15.443 76.104 17.891 ;
     RECT  77.568 17.077 79.128 17.989 ;
     RECT  36.48 15.637 40.512 18.131 ;
     RECT  4.752 17.509 5.496 18.133 ;
     RECT  21.456 17.845 22.008 18.133 ;
     RECT  23.04 17.173 24.456 18.133 ;
     RECT  29.4 17.219 32.088 18.181 ;
     RECT  58.8 17.509 66.12 18.275 ;
     RECT  68.976 17.459 70.44 18.275 ;
     RECT  71.472 17.605 73.56 18.275 ;
     RECT  48.48 17.699 48.648 18.419 ;
     RECT  50.112 17.699 57.336 18.419 ;
     RECT  58.8 18.275 65.736 18.515 ;
     RECT  26.448 17.171 26.664 18.565 ;
     RECT  28.656 18.181 32.088 18.613 ;
     RECT  69.504 18.275 70.44 18.613 ;
     RECT  28.656 18.613 32.424 18.661 ;
     RECT  2.4 14.339 2.712 18.709 ;
     RECT  4.752 18.133 6.312 18.803 ;
     RECT  28.656 18.661 33.096 18.803 ;
     RECT  37.584 18.131 40.512 18.803 ;
     RECT  69.504 18.613 71.256 18.803 ;
     RECT  2.4 18.709 2.856 18.805 ;
     RECT  5.472 18.803 6.312 18.851 ;
     RECT  59.76 18.515 65.736 18.851 ;
     RECT  72.48 18.275 73.56 18.851 ;
     RECT  82.704 17.411 83.712 18.851 ;
     RECT  2.4 18.805 3 18.947 ;
     RECT  28.656 18.803 32.424 18.995 ;
     RECT  69.504 18.803 70.44 18.995 ;
     RECT  60.576 18.851 65.736 19.043 ;
     RECT  69.504 18.995 69.528 19.043 ;
     RECT  48.624 18.419 48.648 19.141 ;
     RECT  50.112 18.419 52.824 19.141 ;
     RECT  34.8 17.411 35.112 19.381 ;
     RECT  42.96 16.261 43.944 19.427 ;
     RECT  60.768 19.043 65.736 19.427 ;
     RECT  16.176 17.459 16.2 19.525 ;
     RECT  17.184 16.019 20.424 19.525 ;
     RECT  76.944 17.989 79.128 19.571 ;
     RECT  7.8 17.363 10.584 19.667 ;
     RECT  2.4 18.947 2.856 19.811 ;
     RECT  6.288 18.851 6.312 19.811 ;
     RECT  60.768 19.427 65.16 19.811 ;
     RECT  76.944 19.571 78.936 19.811 ;
     RECT  67.2 17.699 67.512 19.861 ;
     RECT  10.56 19.667 10.584 19.955 ;
     RECT  43.92 19.427 43.944 20.003 ;
     RECT  77.52 19.811 78.936 20.003 ;
     RECT  28.656 18.995 32.088 20.099 ;
     RECT  41.712 19.093 41.736 20.099 ;
     RECT  4.224 19.669 4.248 20.195 ;
     RECT  21.456 18.133 24.456 20.195 ;
     RECT  68.976 19.909 69 20.195 ;
     RECT  11.76 17.459 14.808 20.245 ;
     RECT  16.176 19.525 20.424 20.245 ;
     RECT  48.624 19.141 52.824 20.293 ;
     RECT  23.04 20.195 24.456 20.339 ;
     RECT  48.624 20.293 53.016 20.339 ;
     RECT  23.472 20.339 24.456 20.341 ;
     RECT  49.2 20.339 53.016 20.435 ;
     RECT  54.048 18.419 57.336 20.437 ;
     RECT  60.768 19.811 64.248 20.485 ;
     RECT  74.64 19.909 74.664 20.579 ;
     RECT  60.672 20.485 64.248 20.723 ;
     RECT  7.8 19.667 9.528 20.725 ;
     RECT  66.48 19.861 67.512 20.771 ;
     RECT  26.352 18.565 26.664 20.869 ;
     RECT  33.168 20.581 33.192 20.963 ;
     RECT  7.68 20.725 9.528 20.965 ;
     RECT  53.856 20.437 57.336 20.965 ;
     RECT  7.056 20.965 9.528 21.107 ;
     RECT  25.536 20.869 26.664 21.107 ;
     RECT  29.4 20.099 32.088 21.109 ;
     RECT  29.04 21.109 32.088 21.205 ;
     RECT  36.384 18.565 36.408 21.205 ;
     RECT  37.584 18.803 38.088 21.205 ;
     RECT  21.456 20.195 22.008 21.299 ;
     RECT  11.76 20.245 20.424 21.395 ;
     RECT  11.76 21.395 14.808 21.397 ;
     RECT  23.472 20.341 24.504 21.443 ;
     RECT  29.04 21.205 32.904 21.445 ;
     RECT  53.856 20.965 57.48 21.445 ;
     RECT  23.472 21.443 24.456 21.493 ;
     RECT  28.464 21.445 32.904 21.539 ;
     RECT  49.2 20.435 52.44 21.637 ;
     RECT  53.52 21.445 57.48 21.637 ;
     RECT  4.896 20.821 4.92 21.683 ;
     RECT  26.208 21.107 26.664 21.683 ;
     RECT  22.8 21.493 24.456 21.731 ;
     RECT  43.776 20.773 43.8 21.827 ;
     RECT  34.8 19.381 35.208 21.925 ;
     RECT  16.176 21.395 20.424 22.069 ;
     RECT  21.456 21.299 21.624 22.069 ;
     RECT  45.6 16.979 45.912 22.069 ;
     RECT  7.68 21.107 9.528 22.165 ;
     RECT  69.264 20.965 69.288 22.165 ;
     RECT  81.504 21.493 81.528 22.165 ;
     RECT  82.848 18.851 83.712 22.165 ;
     RECT  10.944 21.397 14.808 22.259 ;
     RECT  81.504 22.165 83.712 22.451 ;
     RECT  60.672 20.723 63.048 22.453 ;
     RECT  64.224 20.723 64.248 22.453 ;
     RECT  60.672 22.453 64.248 22.499 ;
     RECT  77.52 20.003 78.312 22.595 ;
     RECT  49.2 21.637 57.48 22.693 ;
     RECT  23.04 21.731 24.456 22.741 ;
     RECT  49.2 22.693 58.344 22.741 ;
     RECT  77.568 22.595 78.312 22.741 ;
     RECT  79.776 21.301 79.8 22.741 ;
     RECT  47.856 20.965 47.88 22.787 ;
     RECT  49.056 22.741 58.344 22.835 ;
     RECT  23.04 22.741 24.504 22.837 ;
     RECT  28.464 21.539 32.52 23.027 ;
     RECT  45.6 22.069 46.824 23.125 ;
     RECT  49.056 22.835 53.064 23.267 ;
     RECT  69.264 22.165 69.96 23.269 ;
     RECT  7.488 22.165 9.528 23.315 ;
     RECT  49.056 23.267 52.344 23.315 ;
     RECT  54.192 22.835 58.344 23.315 ;
     RECT  2.4 19.811 2.712 23.317 ;
     RECT  34.8 21.925 35.256 23.317 ;
     RECT  36.384 21.205 38.088 23.317 ;
     RECT  22.752 22.837 24.504 23.363 ;
     RECT  82.032 22.451 83.712 23.411 ;
     RECT  16.176 22.069 21.624 23.557 ;
     RECT  22.752 23.363 24.312 23.557 ;
     RECT  60.672 22.499 64.056 23.603 ;
     RECT  77.568 22.741 80.52 23.605 ;
     RECT  42.576 21.109 42.6 23.747 ;
     RECT  34.8 23.317 38.088 23.795 ;
     RECT  26.448 21.683 26.664 23.893 ;
     RECT  16.176 23.557 24.312 23.939 ;
     RECT  26.448 23.893 26.76 23.939 ;
     RECT  60.816 23.603 64.056 23.987 ;
     RECT  74.928 21.301 74.952 24.131 ;
     RECT  77.568 23.605 81.192 24.131 ;
     RECT  11.76 22.259 14.808 24.133 ;
     RECT  22.752 23.939 24.312 24.323 ;
     RECT  33.6 22.741 33.624 24.323 ;
     RECT  7.68 23.315 9.528 24.325 ;
     RECT  79.776 24.131 81.192 24.371 ;
     RECT  37.68 23.795 38.088 24.421 ;
     RECT  39.264 18.803 40.512 24.421 ;
     RECT  16.176 23.939 21.624 24.467 ;
     RECT  56.4 23.315 58.344 24.611 ;
     RECT  68.976 23.269 69.96 24.613 ;
     RECT  27.744 23.365 27.768 24.659 ;
     RECT  68.976 24.613 70.632 24.659 ;
     RECT  64.032 23.987 64.056 24.707 ;
     RECT  60.816 23.987 62.952 24.805 ;
     RECT  34.8 23.795 36.408 24.853 ;
     RECT  34.8 24.853 36.456 24.899 ;
     RECT  29.4 23.027 32.52 24.901 ;
     RECT  50.112 23.315 52.344 24.949 ;
     RECT  7.68 24.325 10.248 25.045 ;
     RECT  29.4 24.901 33.096 25.091 ;
     RECT  37.68 24.421 40.512 25.091 ;
     RECT  54.192 23.315 55.272 25.091 ;
     RECT  2.304 23.317 2.712 25.139 ;
     RECT  5.04 23.893 5.064 25.139 ;
     RECT  22.8 24.323 24.312 25.141 ;
     RECT  25.344 24.997 25.368 25.141 ;
     RECT  36.384 24.899 36.456 25.141 ;
     RECT  80.928 24.371 81.192 25.187 ;
     RECT  36.384 25.141 37.368 25.283 ;
     RECT  60.24 24.805 62.952 25.331 ;
     RECT  36.384 25.283 36.456 25.427 ;
     RECT  45.6 23.125 47.592 25.427 ;
     RECT  50.112 24.949 52.488 25.427 ;
     RECT  17.184 24.467 21.624 25.477 ;
     RECT  22.8 25.141 25.368 25.477 ;
     RECT  81.168 25.187 81.192 25.573 ;
     RECT  82.32 23.411 83.712 25.573 ;
     RECT  17.184 25.477 25.368 25.619 ;
     RECT  60.816 25.331 62.952 25.715 ;
     RECT  81.168 25.573 83.712 25.715 ;
     RECT  67.2 20.771 67.512 25.717 ;
     RECT  6.864 25.045 10.248 26.003 ;
     RECT  45.6 25.427 45.912 26.005 ;
     RECT  6.864 26.003 9.528 26.051 ;
     RECT  11.232 24.133 14.808 26.099 ;
     RECT  29.4 25.091 32.952 26.149 ;
     RECT  44.976 26.005 45.912 26.197 ;
     RECT  69.936 24.659 70.632 26.243 ;
     RECT  54.432 25.091 55.272 26.483 ;
     RECT  74.688 26.149 74.712 26.533 ;
     RECT  75.792 25.045 75.816 26.533 ;
     RECT  74.688 26.533 75.816 26.579 ;
     RECT  74.688 26.579 75.624 26.581 ;
     RECT  56.4 24.611 57.48 26.629 ;
     RECT  66.336 25.717 67.512 26.629 ;
     RECT  66.336 26.629 67.8 26.675 ;
     RECT  54.432 26.483 55.224 26.677 ;
     RECT  79.776 24.371 79.8 26.677 ;
     RECT  81.168 25.715 81.48 26.723 ;
     RECT  79.488 26.677 79.8 26.771 ;
     RECT  7.392 26.051 9.528 26.819 ;
     RECT  54.336 26.677 55.224 26.819 ;
     RECT  26.64 23.939 26.76 26.917 ;
     RECT  47.568 25.427 47.592 26.917 ;
     RECT  82.848 25.715 83.712 26.917 ;
     RECT  47.568 26.917 47.976 26.963 ;
     RECT  16.176 24.467 16.2 27.013 ;
     RECT  17.184 25.619 21.624 27.013 ;
     RECT  67.2 26.675 67.8 27.059 ;
     RECT  50.112 25.427 52.344 27.061 ;
     RECT  26.64 26.917 26.856 27.107 ;
     RECT  69.936 26.243 70.152 27.107 ;
     RECT  16.176 27.013 21.624 27.347 ;
     RECT  34.8 24.899 35.256 27.347 ;
     RECT  82.224 26.917 83.712 27.395 ;
     RECT  64.08 26.725 64.104 27.587 ;
     RECT  74.208 26.581 75.624 27.587 ;
     RECT  22.8 25.619 25.368 27.589 ;
     RECT  44.544 26.197 45.912 27.731 ;
     RECT  12.048 26.099 14.808 27.733 ;
     RECT  16.176 27.347 21.48 27.779 ;
     RECT  4.512 26.725 4.536 27.781 ;
     RECT  4.368 27.781 4.536 27.877 ;
     RECT  28.656 26.149 32.952 27.877 ;
     RECT  45.6 27.731 45.912 27.877 ;
     RECT  56.4 26.629 57.528 27.877 ;
     RECT  4.128 27.877 4.536 27.923 ;
     RECT  34.8 27.347 35.208 27.923 ;
     RECT  74.688 27.587 75.624 27.923 ;
     RECT  82.224 27.395 82.248 27.923 ;
     RECT  56.4 27.877 57.768 27.925 ;
     RECT  56.4 27.925 57.864 28.067 ;
     RECT  27.888 27.877 32.952 28.115 ;
     RECT  54.336 26.819 54.936 28.211 ;
     RECT  7.8 26.819 9.528 28.403 ;
     RECT  50.112 27.061 53.256 28.403 ;
     RECT  70.08 27.107 70.152 28.403 ;
     RECT  56.4 28.067 57.768 28.451 ;
     RECT  12 27.733 14.808 28.453 ;
     RECT  72.48 18.851 72.912 28.453 ;
     RECT  17.184 27.779 21.48 28.547 ;
     RECT  74.688 27.923 75.576 28.595 ;
     RECT  11.808 28.453 14.808 28.739 ;
     RECT  70.08 28.403 70.104 28.739 ;
     RECT  38.592 25.091 40.512 28.741 ;
     RECT  67.2 27.059 67.512 28.789 ;
     RECT  26.64 27.107 26.664 28.933 ;
     RECT  27.888 28.115 32.808 28.933 ;
     RECT  36.384 25.427 36.408 28.933 ;
     RECT  26.64 28.933 32.808 28.979 ;
     RECT  20.208 28.547 21.48 29.075 ;
     RECT  45.6 27.877 46.44 29.075 ;
     RECT  22.752 27.589 25.368 29.077 ;
     RECT  38.064 28.741 40.512 29.123 ;
     RECT  79.488 26.771 79.608 29.123 ;
     RECT  4.128 27.923 4.392 29.219 ;
     RECT  64.032 27.877 64.056 29.219 ;
     RECT  7.8 28.403 9.144 29.221 ;
     RECT  16.176 27.779 16.2 29.221 ;
     RECT  14.544 28.739 14.808 29.267 ;
     RECT  26.64 28.979 32.088 29.363 ;
     RECT  44.544 27.731 44.568 29.411 ;
     RECT  47.952 26.963 47.976 29.413 ;
     RECT  49.056 23.315 49.08 29.413 ;
     RECT  47.952 29.413 49.08 29.459 ;
     RECT  27.888 29.363 32.088 29.555 ;
     RECT  60.816 25.715 62.904 29.651 ;
     RECT  75.216 28.595 75.576 29.651 ;
     RECT  7.44 29.221 9.144 29.653 ;
     RECT  10.368 29.365 10.392 29.653 ;
     RECT  15.936 29.221 16.2 29.653 ;
     RECT  17.184 28.547 19.176 29.653 ;
     RECT  7.44 29.653 10.392 29.699 ;
     RECT  61.152 29.651 62.904 29.699 ;
     RECT  67.2 28.789 67.608 29.699 ;
     RECT  22.752 29.077 25.464 29.701 ;
     RECT  11.808 28.739 13.512 29.749 ;
     RECT  54.336 28.211 54.888 29.797 ;
     RECT  54.24 29.797 54.888 29.893 ;
     RECT  7.44 29.699 9.528 30.035 ;
     RECT  15.936 29.653 19.176 30.037 ;
     RECT  20.4 29.075 21.48 30.037 ;
     RECT  61.296 29.699 62.904 30.083 ;
     RECT  22.752 29.701 25.56 30.227 ;
     RECT  45.6 29.075 45.912 30.229 ;
     RECT  22.752 30.227 24.504 30.275 ;
     RECT  45.12 30.229 45.912 30.325 ;
     RECT  11.088 29.749 13.512 30.419 ;
     RECT  15.936 30.037 21.48 30.563 ;
     RECT  47.952 29.459 48.408 30.565 ;
     RECT  81.168 26.723 81.192 30.661 ;
     RECT  81.168 30.661 81.384 30.707 ;
     RECT  2.4 25.139 2.712 30.709 ;
     RECT  4.128 29.219 4.152 30.709 ;
     RECT  43.056 30.517 43.08 30.803 ;
     RECT  75.216 29.651 75.528 30.805 ;
     RECT  47.904 30.565 48.408 30.851 ;
     RECT  2.4 30.709 4.152 30.899 ;
     RECT  17.184 30.563 21.48 31.283 ;
     RECT  36.384 28.933 36.84 31.381 ;
     RECT  11.088 30.419 11.112 31.571 ;
     RECT  65.616 28.357 65.64 31.669 ;
     RECT  2.4 30.899 2.712 31.861 ;
     RECT  4.128 30.899 4.152 31.861 ;
     RECT  23.04 30.275 24.504 31.861 ;
     RECT  25.536 30.227 25.56 31.861 ;
     RECT  47.952 30.851 48.408 31.909 ;
     RECT  33.696 30.469 33.72 31.955 ;
     RECT  65.616 31.669 66.024 31.957 ;
     RECT  7.8 30.035 9.528 32.051 ;
     RECT  20.4 31.283 21.48 32.053 ;
     RECT  23.04 31.861 25.56 32.053 ;
     RECT  67.2 29.699 67.512 32.053 ;
     RECT  72.24 28.453 72.912 32.099 ;
     RECT  26.64 29.363 26.664 32.101 ;
     RECT  28.368 29.555 32.088 32.101 ;
     RECT  36.384 31.381 36.888 32.197 ;
     RECT  38.592 29.123 40.512 32.291 ;
     RECT  7.8 32.051 8.856 32.293 ;
     RECT  34.8 27.923 35.112 32.293 ;
     RECT  54.24 29.893 54.984 32.293 ;
     RECT  56.4 28.451 57.528 32.293 ;
     RECT  58.8 28.165 58.824 32.341 ;
     RECT  45.12 30.325 46.44 32.483 ;
     RECT  26.64 32.101 32.088 32.531 ;
     RECT  74.352 30.805 75.528 32.531 ;
     RECT  20.4 32.053 25.56 32.627 ;
     RECT  17.184 31.283 19.272 32.723 ;
     RECT  54.24 32.293 57.528 32.915 ;
     RECT  12.144 30.419 13.512 32.965 ;
     RECT  20.4 32.627 21.48 32.965 ;
     RECT  18.192 32.723 19.272 33.011 ;
     RECT  23.04 32.627 25.56 33.011 ;
     RECT  81.36 30.707 81.384 33.013 ;
     RECT  7.392 32.293 8.856 33.107 ;
     RECT  67.2 32.053 68.376 33.107 ;
     RECT  11.424 32.965 13.512 33.109 ;
     RECT  26.64 32.531 30.744 33.203 ;
     RECT  45.6 32.483 46.44 33.205 ;
     RECT  11.232 33.109 13.512 33.251 ;
     RECT  43.872 32.437 43.896 33.251 ;
     RECT  2.4 31.861 4.152 33.253 ;
     RECT  28.368 33.203 30.744 33.347 ;
     RECT  45.6 33.205 46.872 33.347 ;
     RECT  69.792 29.461 69.816 33.349 ;
     RECT  38.592 32.291 38.616 33.397 ;
     RECT  9.888 33.061 9.912 33.491 ;
     RECT  65.472 31.957 66.024 33.541 ;
     RECT  67.2 33.107 67.848 33.541 ;
     RECT  75.504 32.531 75.528 33.587 ;
     RECT  71.376 32.965 71.4 33.589 ;
     RECT  54.336 32.915 57.528 33.731 ;
     RECT  69.408 33.349 69.816 33.731 ;
     RECT  79.584 29.123 79.608 33.781 ;
     RECT  83.4 27.395 83.712 33.781 ;
     RECT  2.4 33.253 4.248 33.827 ;
     RECT  81.264 33.013 81.384 33.827 ;
     RECT  11.424 33.251 13.512 33.829 ;
     RECT  36.384 32.197 37.032 33.875 ;
     RECT  65.472 33.541 67.848 33.875 ;
     RECT  81.36 33.827 81.384 33.923 ;
     RECT  11.424 33.829 13.656 33.971 ;
     RECT  47.904 31.909 48.408 34.211 ;
     RECT  18.192 33.011 19.176 34.213 ;
     RECT  20.304 32.965 21.48 34.213 ;
     RECT  17.184 32.723 17.208 34.259 ;
     RECT  34.704 32.293 35.112 34.259 ;
     RECT  38.4 33.397 38.616 34.259 ;
     RECT  58.656 32.341 58.824 34.259 ;
     RECT  71.376 33.589 71.544 34.259 ;
     RECT  79.584 33.781 80.04 34.355 ;
     RECT  11.424 33.971 13.512 34.403 ;
     RECT  69.744 33.731 69.816 34.403 ;
     RECT  15.936 30.563 16.2 34.451 ;
     RECT  74.352 32.531 74.376 34.453 ;
     RECT  39.792 32.291 40.512 34.501 ;
     RECT  18.192 34.213 21.48 34.549 ;
     RECT  47.952 34.211 48.408 34.741 ;
     RECT  54.336 33.731 54.888 34.741 ;
     RECT  79.584 34.355 79.608 34.741 ;
     RECT  60.192 33.925 60.216 34.787 ;
     RECT  65.52 33.875 67.848 34.835 ;
     RECT  14.784 29.267 14.808 34.885 ;
     RECT  15.936 34.451 15.96 34.885 ;
     RECT  14.784 34.885 15.96 34.931 ;
     RECT  50.112 28.403 52.344 34.979 ;
     RECT  33.072 33.109 33.096 35.173 ;
     RECT  74.064 34.453 74.376 35.219 ;
     RECT  12.144 34.403 13.512 35.317 ;
     RECT  14.784 34.931 15.672 35.317 ;
     RECT  74.064 35.219 74.088 35.363 ;
     RECT  79.44 34.741 79.608 35.363 ;
     RECT  47.952 34.741 48.648 35.411 ;
     RECT  69.792 34.403 69.816 35.509 ;
     RECT  65.568 34.835 67.848 35.555 ;
     RECT  39.792 34.501 41.112 35.699 ;
     RECT  23.04 33.011 24.552 35.749 ;
     RECT  25.536 33.011 25.56 35.749 ;
     RECT  31.824 32.531 32.088 35.749 ;
     RECT  33.072 35.173 33.336 35.749 ;
     RECT  36.384 33.875 36.456 35.797 ;
     RECT  37.584 35.317 37.608 35.797 ;
     RECT  47.952 35.411 48.408 35.843 ;
     RECT  7.8 33.107 8.856 35.845 ;
     RECT  53.664 34.741 54.888 35.891 ;
     RECT  31.824 35.749 33.336 35.987 ;
     RECT  28.368 33.347 28.392 36.037 ;
     RECT  4.224 33.827 4.248 36.131 ;
     RECT  12.144 35.317 15.672 36.131 ;
     RECT  58.8 34.259 58.824 36.131 ;
     RECT  23.04 35.749 25.56 36.515 ;
     RECT  39.792 35.699 40.68 36.515 ;
     RECT  34.8 34.259 35.112 36.517 ;
     RECT  65.568 35.555 67.512 36.563 ;
     RECT  42.768 36.133 42.792 36.565 ;
     RECT  48.336 35.843 48.408 36.853 ;
     RECT  27.84 36.037 28.392 36.901 ;
     RECT  29.4 33.347 30.744 36.901 ;
     RECT  27.84 36.901 30.744 36.997 ;
     RECT  32.064 35.987 33.336 36.997 ;
     RECT  48.336 36.853 48.456 36.997 ;
     RECT  34.368 36.517 35.112 37.043 ;
     RECT  17.28 34.549 21.48 37.091 ;
     RECT  42.768 36.565 42.936 37.093 ;
     RECT  61.296 30.083 62.808 37.283 ;
     RECT  38.592 34.259 38.616 37.333 ;
     RECT  39.792 36.515 40.512 37.333 ;
     RECT  61.296 37.283 62.568 37.379 ;
     RECT  47.904 36.997 48.456 37.429 ;
     RECT  69.648 35.509 69.816 37.429 ;
     RECT  18.192 37.091 21.48 37.475 ;
     RECT  38.592 37.333 40.512 37.475 ;
     RECT  56.4 33.731 57.528 37.477 ;
     RECT  38.64 37.475 40.512 37.571 ;
     RECT  79.584 35.363 79.608 37.573 ;
     RECT  42.768 37.093 43.368 37.619 ;
     RECT  61.296 37.379 62.52 37.619 ;
     RECT  7.392 35.845 8.856 37.667 ;
     RECT  12.144 36.131 14.808 37.667 ;
     RECT  23.04 36.515 24.936 37.667 ;
     RECT  61.632 37.619 62.52 37.667 ;
     RECT  69.6 37.429 69.816 37.907 ;
     RECT  71.52 34.259 71.544 38.003 ;
     RECT  43.344 37.619 43.368 38.005 ;
     RECT  36.384 35.797 37.608 38.147 ;
     RECT  45.6 33.347 46.44 38.149 ;
     RECT  50.64 34.979 52.344 38.149 ;
     RECT  72.6 32.099 72.912 38.149 ;
     RECT  82.416 33.781 83.712 38.149 ;
     RECT  14.784 37.667 14.808 38.195 ;
     RECT  26.64 33.203 26.664 38.243 ;
     RECT  27.84 36.997 33.336 38.243 ;
     RECT  49.872 38.149 52.344 38.243 ;
     RECT  79.584 37.573 79.752 38.243 ;
     RECT  43.344 38.005 43.464 38.435 ;
     RECT  56.304 37.477 57.528 38.485 ;
     RECT  27.84 38.243 28.392 38.771 ;
     RECT  82.32 38.149 83.712 38.773 ;
     RECT  59.76 38.677 59.784 38.819 ;
     RECT  61.632 37.667 62.424 38.821 ;
     RECT  38.64 37.571 38.664 38.915 ;
     RECT  16.56 37.429 16.584 39.059 ;
     RECT  12.144 37.667 13.608 39.061 ;
     RECT  34.8 37.043 35.112 39.061 ;
     RECT  71.568 38.437 71.592 39.109 ;
     RECT  72.6 38.149 73.224 39.109 ;
     RECT  61.632 38.821 62.904 39.155 ;
     RECT  45.072 38.149 46.44 39.251 ;
     RECT  12 39.061 13.608 39.299 ;
     RECT  27.936 38.771 28.392 39.301 ;
     RECT  29.4 38.243 33.336 39.301 ;
     RECT  20.256 37.475 21.48 39.395 ;
     RECT  74.832 37.429 74.856 39.539 ;
     RECT  47.904 37.429 48.504 39.589 ;
     RECT  26.832 39.061 26.856 39.877 ;
     RECT  69.6 37.907 69.624 39.971 ;
     RECT  7.44 37.667 8.856 40.019 ;
     RECT  12 39.299 13.512 40.163 ;
     RECT  65.28 39.253 65.304 40.163 ;
     RECT  7.44 40.019 8.232 40.259 ;
     RECT  36.384 38.147 36.888 40.261 ;
     RECT  56.208 38.485 57.528 40.261 ;
     RECT  82.032 38.773 83.712 40.403 ;
     RECT  17.136 39.301 17.16 40.405 ;
     RECT  18.192 37.475 19.176 40.405 ;
     RECT  36.288 40.261 36.888 40.405 ;
     RECT  60.336 39.253 60.36 40.405 ;
     RECT  74.784 39.829 74.808 40.405 ;
     RECT  60.336 40.405 60.456 40.451 ;
     RECT  36.288 40.405 37.656 40.499 ;
     RECT  17.136 40.405 19.176 40.595 ;
     RECT  34.8 39.061 35.208 40.691 ;
     RECT  52.896 39.253 52.92 40.693 ;
     RECT  54.336 35.891 54.888 40.693 ;
     RECT  41.616 39.301 41.64 40.789 ;
     RECT  36.384 40.499 37.656 40.835 ;
     RECT  41.616 40.789 42.168 40.835 ;
     RECT  77.568 24.131 78.312 40.885 ;
     RECT  79.728 38.243 79.752 40.885 ;
     RECT  47.904 39.589 48.84 40.979 ;
     RECT  39.792 37.571 40.512 40.981 ;
     RECT  45.6 39.251 46.44 40.981 ;
     RECT  77.568 40.885 79.752 40.981 ;
     RECT  12 40.163 12.168 41.027 ;
     RECT  74.688 40.405 74.808 41.075 ;
     RECT  45.6 40.981 46.776 41.123 ;
     RECT  27.936 39.301 33.336 41.125 ;
     RECT  27.888 41.125 33.336 41.267 ;
     RECT  60.432 40.451 60.456 41.363 ;
     RECT  45.6 41.123 46.44 41.413 ;
     RECT  26.688 39.877 26.856 41.461 ;
     RECT  27.888 41.267 29.712 41.461 ;
     RECT  58.704 40.597 58.728 41.557 ;
     RECT  7.8 40.259 8.232 41.651 ;
     RECT  30.72 41.267 33.336 41.651 ;
     RECT  55.872 40.261 57.528 41.651 ;
     RECT  26.688 41.461 29.712 41.939 ;
     RECT  66.384 36.563 67.512 41.941 ;
     RECT  58.704 41.557 59.256 42.037 ;
     RECT  39.792 40.981 40.872 42.131 ;
     RECT  6.336 40.213 6.36 42.133 ;
     RECT  49.872 38.243 51.768 42.133 ;
     RECT  52.896 40.693 54.888 42.133 ;
     RECT  60.528 41.749 60.552 42.133 ;
     RECT  61.632 39.155 62.424 42.133 ;
     RECT  58.704 42.037 59.448 42.179 ;
     RECT  65.808 41.941 67.512 42.181 ;
     RECT  33.264 41.651 33.336 42.227 ;
     RECT  45.024 41.413 46.44 42.323 ;
     RECT  39.792 42.131 40.512 42.469 ;
     RECT  49.872 42.133 54.888 42.565 ;
     RECT  55.872 41.651 57.336 42.565 ;
     RECT  30.72 41.651 30.744 42.709 ;
     RECT  32.064 41.651 32.088 42.709 ;
     RECT  37.632 40.835 37.656 42.709 ;
     RECT  60.528 42.133 62.424 42.709 ;
     RECT  28.368 41.939 29.712 42.803 ;
     RECT  49.872 42.565 57.336 42.803 ;
     RECT  59.232 42.179 59.448 42.853 ;
     RECT  37.632 42.709 37.992 42.995 ;
     RECT  49.872 42.803 52.92 42.995 ;
     RECT  60.528 42.709 63 42.995 ;
     RECT  5.808 42.133 6.36 43.093 ;
     RECT  7.8 41.651 8.112 43.093 ;
     RECT  34.8 40.691 35.112 43.093 ;
     RECT  5.808 43.093 8.112 43.235 ;
     RECT  75.984 42.085 76.008 43.237 ;
     RECT  77.568 40.981 80.232 43.237 ;
     RECT  5.808 43.235 6.36 43.283 ;
     RECT  34.704 43.093 35.112 43.283 ;
     RECT  75.984 43.237 80.232 43.283 ;
     RECT  30.72 42.709 32.088 43.331 ;
     RECT  42.144 40.835 42.168 43.331 ;
     RECT  39.696 42.469 40.512 43.475 ;
     RECT  43.44 38.435 43.464 43.475 ;
     RECT  29.4 42.803 29.712 43.477 ;
     RECT  30.72 43.331 30.744 43.477 ;
     RECT  39.792 43.475 40.512 43.477 ;
     RECT  64.992 42.181 67.512 43.571 ;
     RECT  60.672 42.995 63 43.715 ;
     RECT  48.432 40.979 48.84 43.765 ;
     RECT  23.184 37.667 24.312 43.813 ;
     RECT  50.64 42.995 52.92 43.861 ;
     RECT  54.336 42.803 57.336 43.861 ;
     RECT  26.688 41.939 27.24 43.907 ;
     RECT  68.928 41.557 68.952 43.955 ;
     RECT  71.568 39.109 73.224 43.955 ;
     RECT  2.4 33.827 2.712 44.053 ;
     RECT  37.968 42.995 37.992 44.053 ;
     RECT  59.232 42.853 59.544 44.147 ;
     RECT  50.64 43.861 57.336 44.195 ;
     RECT  70.368 43.861 70.392 44.197 ;
     RECT  39.792 43.477 41.208 44.291 ;
     RECT  13.2 40.163 13.512 44.341 ;
     RECT  69.504 44.197 70.392 44.341 ;
     RECT  7.8 43.235 8.112 44.437 ;
     RECT  12 41.027 12.072 44.437 ;
     RECT  48.432 43.765 49.464 44.437 ;
     RECT  50.64 44.195 52.68 44.437 ;
     RECT  45.264 42.323 46.44 44.483 ;
     RECT  76.896 43.283 80.232 44.483 ;
     RECT  72.384 43.955 73.224 44.485 ;
     RECT  29.4 43.477 30.744 44.531 ;
     RECT  74.784 41.075 74.808 44.531 ;
     RECT  2.4 44.053 3.288 44.627 ;
     RECT  45.6 44.483 46.44 44.629 ;
     RECT  82.32 40.403 83.712 44.675 ;
     RECT  33.264 42.227 33.288 44.725 ;
     RECT  11.472 44.437 12.072 44.821 ;
     RECT  13.2 44.341 14.28 44.821 ;
     RECT  45.6 44.629 47.4 44.867 ;
     RECT  17.232 40.595 19.176 44.965 ;
     RECT  69.504 44.341 70.488 44.965 ;
     RECT  60.672 43.715 62.52 45.011 ;
     RECT  7.68 44.437 8.112 45.059 ;
     RECT  9.888 39.013 9.912 45.059 ;
     RECT  42.768 43.861 42.792 45.059 ;
     RECT  77.568 44.483 80.232 45.059 ;
     RECT  27.216 43.907 27.24 45.251 ;
     RECT  60.96 45.011 62.52 45.397 ;
     RECT  48.432 44.437 52.68 45.491 ;
     RECT  59.232 44.147 59.4 45.491 ;
     RECT  53.712 44.195 57.336 45.539 ;
     RECT  65.808 43.571 67.512 45.541 ;
     RECT  37.728 44.053 37.992 45.587 ;
     RECT  45.6 44.867 47.208 45.587 ;
     RECT  11.472 44.821 14.28 45.635 ;
     RECT  31.968 43.331 32.088 45.635 ;
     RECT  65.808 45.541 67.848 45.685 ;
     RECT  68.928 44.965 70.488 45.685 ;
     RECT  33.264 44.725 33.432 45.731 ;
     RECT  48.432 45.491 49.56 45.731 ;
     RECT  23.184 43.813 24.456 45.925 ;
     RECT  2.4 44.627 2.904 45.971 ;
     RECT  60.96 45.397 63.24 45.971 ;
     RECT  36.384 40.835 36.456 46.019 ;
     RECT  82.32 44.675 82.392 46.067 ;
     RECT  42.48 45.541 42.504 46.165 ;
     RECT  65.808 45.685 70.488 46.259 ;
     RECT  6.336 43.283 6.36 46.357 ;
     RECT  48.432 45.731 49.464 46.357 ;
     RECT  6.336 46.357 6.552 46.403 ;
     RECT  67.2 46.259 70.488 46.595 ;
     RECT  7.8 45.059 8.112 46.597 ;
     RECT  23.184 45.925 25.128 46.739 ;
     RECT  61.632 45.971 63.24 46.739 ;
     RECT  50.64 45.491 52.68 46.787 ;
     RECT  69.504 46.595 70.488 46.787 ;
     RECT  80.736 46.453 80.76 46.787 ;
     RECT  45.6 45.587 46.44 46.837 ;
     RECT  65.808 46.259 66.216 46.837 ;
     RECT  6.528 46.403 6.552 46.883 ;
     RECT  70.128 46.787 70.488 46.883 ;
     RECT  45.504 46.837 46.44 46.979 ;
     RECT  70.128 46.883 70.152 47.027 ;
     RECT  37.968 45.587 37.992 47.221 ;
     RECT  37.968 47.221 38.28 47.267 ;
     RECT  28.368 42.803 28.392 47.317 ;
     RECT  41.616 46.165 42.504 47.603 ;
     RECT  11.472 45.635 13.512 47.699 ;
     RECT  17.232 44.965 19.368 47.699 ;
     RECT  59.376 45.491 59.4 47.939 ;
     RECT  33.264 45.731 33.288 48.277 ;
     RECT  33.264 48.277 33.432 48.323 ;
     RECT  28.08 47.317 28.392 48.371 ;
     RECT  4.32 41.557 4.344 48.421 ;
     RECT  45.6 46.979 46.44 48.757 ;
     RECT  48.336 46.357 49.464 48.803 ;
     RECT  12.048 47.699 13.512 48.805 ;
     RECT  58.848 48.373 58.872 48.851 ;
     RECT  67.2 46.595 68.424 48.853 ;
     RECT  69.504 47.845 69.528 48.853 ;
     RECT  20.592 39.395 21.48 48.901 ;
     RECT  67.2 48.853 69.528 48.947 ;
     RECT  16.656 47.845 16.68 48.949 ;
     RECT  16.656 48.949 17.112 48.995 ;
     RECT  4.32 48.421 5.64 48.997 ;
     RECT  3.744 48.997 5.64 49.043 ;
     RECT  67.2 48.947 69.096 49.043 ;
     RECT  64.944 46.837 66.216 49.045 ;
     RECT  5.616 49.043 5.64 49.091 ;
     RECT  17.088 48.995 17.112 49.091 ;
     RECT  41.664 47.603 42.504 49.091 ;
     RECT  36.432 46.019 36.456 49.141 ;
     RECT  33.408 48.323 33.432 49.187 ;
     RECT  67.2 49.043 68.856 49.427 ;
     RECT  11.424 48.805 13.512 49.475 ;
     RECT  23.184 46.739 24.312 49.477 ;
     RECT  7.8 46.597 8.328 49.523 ;
     RECT  72.384 44.485 73.8 49.523 ;
     RECT  50.64 46.787 51.768 49.525 ;
     RECT  77.568 45.059 79.704 49.525 ;
     RECT  82.32 46.067 82.344 49.525 ;
     RECT  83.4 44.675 83.712 49.525 ;
     RECT  36.432 49.141 37.032 49.571 ;
     RECT  36.432 49.571 36.456 49.667 ;
     RECT  76.032 47.749 76.056 49.715 ;
     RECT  64.848 49.045 66.216 49.813 ;
     RECT  67.2 49.427 67.512 49.813 ;
     RECT  12.048 49.475 13.512 49.861 ;
     RECT  14.832 47.653 14.856 49.861 ;
     RECT  32.064 45.635 32.088 50.005 ;
     RECT  33.072 49.477 33.096 50.005 ;
     RECT  3.744 49.043 4.344 50.051 ;
     RECT  7.8 49.523 8.232 50.051 ;
     RECT  18.144 47.699 19.368 50.051 ;
     RECT  30.72 44.531 30.744 50.051 ;
     RECT  72.384 49.523 72.912 50.053 ;
     RECT  82.32 49.525 83.712 50.053 ;
     RECT  61.632 46.739 62.52 50.099 ;
     RECT  64.848 49.813 67.512 50.099 ;
     RECT  38.256 47.267 38.28 50.101 ;
     RECT  58.752 49.765 58.776 50.101 ;
     RECT  61.632 50.099 62.112 50.101 ;
     RECT  64.848 50.099 66.216 50.149 ;
     RECT  44.88 48.757 46.44 50.195 ;
     RECT  7.8 50.051 8.112 50.245 ;
     RECT  38.256 50.101 38.328 50.293 ;
     RECT  70.176 49.285 70.2 50.293 ;
     RECT  64.56 50.149 66.216 50.339 ;
     RECT  70.176 50.293 70.872 50.339 ;
     RECT  72.336 50.053 72.912 50.389 ;
     RECT  58.704 50.101 59.256 50.435 ;
     RECT  70.608 50.339 70.872 50.483 ;
     RECT  67.2 50.099 67.512 50.533 ;
     RECT  20.592 48.901 21.672 50.579 ;
     RECT  23.184 49.477 24.504 50.579 ;
     RECT  38.256 50.293 38.472 50.677 ;
     RECT  39.792 44.291 40.512 50.677 ;
     RECT  45.072 50.195 46.44 50.677 ;
     RECT  12.048 49.861 14.856 50.723 ;
     RECT  3.84 50.051 4.344 50.771 ;
     RECT  81.408 50.053 83.712 50.771 ;
     RECT  48.48 48.803 49.464 50.819 ;
     RECT  60.768 50.101 62.112 50.819 ;
     RECT  38.256 50.677 40.512 50.821 ;
     RECT  41.52 49.765 41.544 50.821 ;
     RECT  38.256 50.821 41.544 50.867 ;
     RECT  34.8 43.283 35.112 51.109 ;
     RECT  45.072 50.677 46.728 51.109 ;
     RECT  38.256 50.867 41.208 51.253 ;
     RECT  54.336 45.539 57.336 51.253 ;
     RECT  32.064 50.005 33.096 51.301 ;
     RECT  37.872 51.253 41.208 51.347 ;
     RECT  58.752 50.435 59.256 51.347 ;
     RECT  6.912 50.245 8.112 51.443 ;
     RECT  77.184 49.525 79.704 51.443 ;
     RECT  31.968 51.301 33.096 51.445 ;
     RECT  18.144 50.051 19.176 51.491 ;
     RECT  12.048 50.723 13.704 51.541 ;
     RECT  40.2 51.347 41.208 51.683 ;
     RECT  81.408 50.771 81.432 51.781 ;
     RECT  82.608 50.771 83.712 51.781 ;
     RECT  79.68 51.443 79.704 51.877 ;
     RECT  20.592 50.579 21.48 51.923 ;
     RECT  31.344 51.445 33.096 51.923 ;
     RECT  45.072 51.109 47.448 51.923 ;
     RECT  64.56 50.339 65.832 51.923 ;
     RECT  81.408 51.781 83.712 51.923 ;
     RECT  45.072 51.923 46.728 51.925 ;
     RECT  18.192 51.491 19.176 52.021 ;
     RECT  54.336 51.253 57.72 52.211 ;
     RECT  77.184 51.443 78.696 52.307 ;
     RECT  81.744 51.923 83.712 52.403 ;
     RECT  31.344 51.923 33.048 52.451 ;
     RECT  14.784 50.723 14.856 52.499 ;
     RECT  31.344 52.451 32.472 52.499 ;
     RECT  61.248 50.819 62.112 52.499 ;
     RECT  77.472 52.307 78.696 52.499 ;
     RECT  17.088 52.405 17.112 52.547 ;
     RECT  23.472 50.579 24.504 52.547 ;
     RECT  34.8 51.109 35.256 52.741 ;
     RECT  28.368 48.371 28.392 52.837 ;
     RECT  54.336 52.211 57.336 52.837 ;
     RECT  53.712 52.837 57.336 52.931 ;
     RECT  58.752 51.347 58.776 53.027 ;
     RECT  18.192 52.021 19.32 53.029 ;
     RECT  34.8 52.741 35.88 53.029 ;
     RECT  37.872 51.347 38.472 53.029 ;
     RECT  34.416 53.029 35.88 53.075 ;
     RECT  34.416 53.075 35.208 53.267 ;
     RECT  50.64 49.525 52.488 53.267 ;
     RECT  27.408 52.837 28.392 53.315 ;
     RECT  50.64 53.267 51.816 53.507 ;
     RECT  11.28 51.541 13.704 53.555 ;
     RECT  7.8 51.443 8.112 53.557 ;
     RECT  23.472 52.547 24.456 53.557 ;
     RECT  49.44 50.819 49.464 53.557 ;
     RECT  82.608 52.403 83.712 53.557 ;
     RECT  21.456 51.923 21.48 53.651 ;
     RECT  64.944 51.923 65.832 53.699 ;
     RECT  37.872 53.029 39.048 53.795 ;
     RECT  36.864 53.365 36.888 53.939 ;
     RECT  50.64 53.507 51.528 53.939 ;
     RECT  4.32 50.771 4.344 54.037 ;
     RECT  63.408 53.557 63.432 54.085 ;
     RECT  72.192 50.389 72.912 54.085 ;
     RECT  29.4 44.531 29.712 54.133 ;
     RECT  67.2 50.533 67.656 54.133 ;
     RECT  34.416 53.267 35.112 54.179 ;
     RECT  77.472 52.499 78.312 54.179 ;
     RECT  79.68 51.877 80.04 54.179 ;
     RECT  82.368 53.557 83.712 54.179 ;
     RECT  23.232 53.557 24.456 54.229 ;
     RECT  25.824 54.133 25.848 54.229 ;
     RECT  23.232 54.229 25.848 54.275 ;
     RECT  31.344 52.499 31.368 54.275 ;
     RECT  66.816 54.133 67.656 54.275 ;
     RECT  79.968 54.179 80.04 54.323 ;
     RECT  4.32 54.037 4.584 54.371 ;
     RECT  14.832 52.499 14.856 54.371 ;
     RECT  23.232 54.275 24.888 54.371 ;
     RECT  67.2 54.275 67.656 54.421 ;
     RECT  28.272 53.315 28.392 54.517 ;
     RECT  29.4 54.133 30.264 54.517 ;
     RECT  53.712 52.931 54.888 54.517 ;
     RECT  50.64 53.939 51.432 54.611 ;
     RECT  56.4 52.931 57.336 54.611 ;
     RECT  12.24 53.555 13.704 54.659 ;
     RECT  28.272 54.517 30.264 54.661 ;
     RECT  63.216 54.085 63.432 54.661 ;
     RECT  10.848 54.517 10.872 54.707 ;
     RECT  28.176 54.661 30.264 54.707 ;
     RECT  70.848 50.483 70.872 54.755 ;
     RECT  63.216 54.661 63.864 54.803 ;
     RECT  4.56 54.371 4.584 54.851 ;
     RECT  65.232 53.699 65.832 54.851 ;
     RECT  7.8 53.557 8.232 54.853 ;
     RECT  36.336 54.373 36.36 54.949 ;
     RECT  37.872 53.795 38.472 54.949 ;
     RECT  36.336 54.949 38.472 54.995 ;
     RECT  82.608 54.179 83.712 55.189 ;
     RECT  44.688 51.925 46.728 55.237 ;
     RECT  67.2 54.421 67.8 55.237 ;
     RECT  68.832 49.427 68.856 55.237 ;
     RECT  18.096 53.029 19.32 55.283 ;
     RECT  48.912 53.557 49.464 55.283 ;
     RECT  53.712 54.517 55.032 55.283 ;
     RECT  21.12 54.085 21.144 55.331 ;
     RECT  44.64 55.237 46.728 55.331 ;
     RECT  63.216 54.803 63.432 55.331 ;
     RECT  15.984 54.613 16.008 55.475 ;
     RECT  79.968 54.323 79.992 55.525 ;
     RECT  36.912 54.995 38.472 55.571 ;
     RECT  49.152 55.283 49.464 55.571 ;
     RECT  72.192 54.085 73.56 55.813 ;
     RECT  44.64 55.331 45.912 55.859 ;
     RECT  18.6 55.283 19.32 55.907 ;
     RECT  49.152 55.571 49.176 55.907 ;
     RECT  7.8 54.853 8.568 55.955 ;
     RECT  72.192 55.813 74.472 55.955 ;
     RECT  28.176 54.707 28.2 56.099 ;
     RECT  67.2 55.237 68.856 56.101 ;
     RECT  77.568 54.179 78.312 56.197 ;
     RECT  10.944 55.285 10.968 56.243 ;
     RECT  63.216 55.331 63.384 56.387 ;
     RECT  23.232 54.371 24.792 56.435 ;
     RECT  37.872 55.571 38.472 56.483 ;
     RECT  47.616 55.429 47.64 56.483 ;
     RECT  79.968 55.525 80.376 56.483 ;
     RECT  75.936 56.485 75.96 56.627 ;
     RECT  34.8 54.179 35.112 56.725 ;
     RECT  57.696 54.901 57.72 56.773 ;
     RECT  59.616 55.813 59.64 56.773 ;
     RECT  57.696 56.773 59.64 56.819 ;
     RECT  74.448 55.955 74.472 56.821 ;
     RECT  2.4 45.971 2.712 56.869 ;
     RECT  72.192 55.955 72.912 56.917 ;
     RECT  50.64 54.611 51.312 56.965 ;
     RECT  67.008 56.101 68.856 57.011 ;
     RECT  40.2 51.683 41.016 57.013 ;
     RECT  43.92 56.389 43.944 57.059 ;
     RECT  52.656 54.469 52.68 57.059 ;
     RECT  58.656 56.819 59.64 57.061 ;
     RECT  34.8 56.725 35.976 57.107 ;
     RECT  39.504 57.013 41.016 57.299 ;
     RECT  67.2 57.011 68.856 57.299 ;
     RECT  39.648 57.299 41.016 57.347 ;
     RECT  61.632 52.499 62.112 57.347 ;
     RECT  15.024 56.005 15.048 57.349 ;
     RECT  29.4 54.707 30.264 57.349 ;
     RECT  81.648 55.189 83.712 57.349 ;
     RECT  81.456 57.349 83.712 57.395 ;
     RECT  13.2 54.659 13.704 57.397 ;
     RECT  67.2 57.299 68.664 57.443 ;
     RECT  71.952 56.917 72.912 57.445 ;
     RECT  77.568 56.197 78.456 57.445 ;
     RECT  79.968 56.483 79.992 57.445 ;
     RECT  29.088 57.349 30.264 57.491 ;
     RECT  32.448 52.499 32.472 57.589 ;
     RECT  65.808 54.851 65.832 57.589 ;
     RECT  21.168 56.965 21.192 57.635 ;
     RECT  77.568 57.445 79.992 57.635 ;
     RECT  23.328 56.435 24.792 57.685 ;
     RECT  31.584 57.589 32.472 57.731 ;
     RECT  49.68 56.965 51.312 57.731 ;
     RECT  23.136 57.685 24.792 57.827 ;
     RECT  13.104 57.397 13.704 57.875 ;
     RECT  71.04 57.445 72.912 57.875 ;
     RECT  58.656 57.061 60.072 57.971 ;
     RECT  39.696 57.347 41.016 58.019 ;
     RECT  81.456 57.395 81.48 58.069 ;
     RECT  14.832 57.349 15.048 58.115 ;
     RECT  7.8 55.955 8.112 58.117 ;
     RECT  33.456 57.877 33.48 58.117 ;
     RECT  56.4 54.611 56.712 58.117 ;
     RECT  74.448 56.821 75 58.117 ;
     RECT  4.992 57.445 5.016 58.163 ;
     RECT  71.04 57.875 71.064 58.259 ;
     RECT  23.328 57.827 24.792 58.451 ;
     RECT  29.4 57.491 30.264 58.453 ;
     RECT  32.448 57.731 32.472 58.453 ;
     RECT  33.456 58.117 33.672 58.453 ;
     RECT  79.392 57.635 79.992 58.547 ;
     RECT  82.512 57.395 83.712 58.547 ;
     RECT  27.648 57.205 27.672 58.549 ;
     RECT  27.648 58.549 27.96 58.645 ;
     RECT  29.088 58.453 30.264 58.645 ;
     RECT  67.2 57.443 68.472 58.645 ;
     RECT  79.392 58.547 79.416 58.691 ;
     RECT  50.64 57.731 51.312 58.693 ;
     RECT  56.4 58.117 57 58.739 ;
     RECT  37.872 56.483 37.896 58.741 ;
     RECT  27.648 58.645 30.696 58.787 ;
     RECT  19.92 57.637 19.944 59.029 ;
     RECT  61.8 57.347 62.112 59.029 ;
     RECT  77.568 57.635 78.312 59.029 ;
     RECT  19.92 59.029 20.424 59.171 ;
     RECT  32.448 58.453 33.672 59.221 ;
     RECT  52.32 58.693 52.344 59.221 ;
     RECT  59.616 57.971 60.072 59.221 ;
     RECT  67.2 58.645 69.384 59.221 ;
     RECT  49.68 58.693 51.312 59.267 ;
     RECT  52.32 59.221 52.872 59.267 ;
     RECT  74.448 58.117 75.048 59.267 ;
     RECT  12 58.645 12.024 59.315 ;
     RECT  23.472 58.451 24.792 59.315 ;
     RECT  39.696 58.019 40.512 59.315 ;
     RECT  65.376 57.589 65.832 59.315 ;
     RECT  32.16 59.221 33.672 59.411 ;
     RECT  67.2 59.221 70.296 59.507 ;
     RECT  15.024 58.115 15.048 59.557 ;
     RECT  61.584 59.029 62.112 59.605 ;
     RECT  63.216 56.387 63.24 59.605 ;
     RECT  27.648 58.787 27.96 59.795 ;
     RECT  3.936 57.541 3.96 59.797 ;
     RECT  81.024 58.069 81.48 59.797 ;
     RECT  34.8 57.107 35.112 59.845 ;
     RECT  43.872 57.445 43.896 59.891 ;
     RECT  34.704 59.845 35.112 59.987 ;
     RECT  3.936 59.797 4.344 60.035 ;
     RECT  37.872 58.741 38.472 60.035 ;
     RECT  83.136 58.547 83.712 60.277 ;
     RECT  13.2 57.875 13.704 60.373 ;
     RECT  29.4 58.787 30.696 60.373 ;
     RECT  56.4 58.739 56.712 60.373 ;
     RECT  67.2 59.507 67.512 60.373 ;
     RECT  32.448 59.411 33.672 60.467 ;
     RECT  12.528 60.373 13.704 60.469 ;
     RECT  15.024 59.557 15.576 60.469 ;
     RECT  20.4 59.171 20.424 60.515 ;
     RECT  69.36 59.507 70.296 60.515 ;
     RECT  39.888 59.315 40.512 60.611 ;
     RECT  29.088 60.373 30.696 60.659 ;
     RECT  58.128 59.125 58.152 60.659 ;
     RECT  59.616 59.221 60.216 60.659 ;
     RECT  7.2 58.117 8.112 60.661 ;
     RECT  54.336 55.283 54.888 60.707 ;
     RECT  32.448 60.467 33.48 60.803 ;
     RECT  17.184 59.605 17.208 60.805 ;
     RECT  40.032 60.611 40.512 60.805 ;
     RECT  17.088 60.805 17.208 60.851 ;
     RECT  42.624 57.541 42.648 60.851 ;
     RECT  50.64 59.267 51.312 60.851 ;
     RECT  74.448 59.267 74.472 60.949 ;
     RECT  17.088 60.851 17.112 61.043 ;
     RECT  54.72 60.707 54.888 61.043 ;
     RECT  12.528 60.469 15.576 61.141 ;
     RECT  74.448 60.949 75.288 61.141 ;
     RECT  11.904 61.141 15.576 61.187 ;
     RECT  74.112 61.141 75.288 61.187 ;
     RECT  4.32 60.035 4.344 61.189 ;
     RECT  56.4 60.373 57.096 61.235 ;
     RECT  77.376 59.029 78.312 61.237 ;
     RECT  2.4 56.869 2.808 61.333 ;
     RECT  4.32 61.189 4.824 61.333 ;
     RECT  54.864 61.043 54.888 61.333 ;
     RECT  36.528 59.605 36.552 61.427 ;
     RECT  52.848 59.267 52.872 61.427 ;
     RECT  49.296 61.333 49.32 61.525 ;
     RECT  59.616 60.659 59.64 61.525 ;
     RECT  10.608 60.133 10.632 61.571 ;
     RECT  15.024 61.187 15.576 61.619 ;
     RECT  40.032 60.805 41.496 61.619 ;
     RECT  75.264 61.187 75.288 61.763 ;
     RECT  2.4 61.333 4.824 61.813 ;
     RECT  6.288 60.661 8.112 61.813 ;
     RECT  23.472 59.315 24.312 61.861 ;
     RECT  56.4 61.235 56.712 61.909 ;
     RECT  2.4 61.813 8.112 61.955 ;
     RECT  65.376 59.315 65.4 61.957 ;
     RECT  2.4 61.955 4.824 62.003 ;
     RECT  34.8 59.987 35.112 62.053 ;
     RECT  45.6 55.859 45.912 62.149 ;
     RECT  58.656 61.525 59.64 62.195 ;
     RECT  72.192 57.875 72.912 62.195 ;
     RECT  20.208 62.053 20.232 62.245 ;
     RECT  61.584 59.605 63.24 62.245 ;
     RECT  48.96 61.525 49.32 62.435 ;
     RECT  53.52 61.717 53.544 62.437 ;
     RECT  34.272 62.053 35.112 62.531 ;
     RECT  38.448 60.035 38.472 62.533 ;
     RECT  38.448 62.533 38.76 62.579 ;
     RECT  13.2 61.187 13.704 62.629 ;
     RECT  32.448 60.803 32.808 62.629 ;
     RECT  54.864 61.333 55.128 62.629 ;
     RECT  26.496 61.381 26.52 62.677 ;
     RECT  25.632 62.677 26.52 62.723 ;
     RECT  32.448 62.629 32.904 62.725 ;
     RECT  23.328 61.861 24.312 62.771 ;
     RECT  77.232 61.237 78.312 62.771 ;
     RECT  65.376 61.957 65.784 62.773 ;
     RECT  66.816 60.373 67.512 62.773 ;
     RECT  6.288 61.955 8.112 62.867 ;
     RECT  56.304 61.909 56.712 62.867 ;
     RECT  45.6 62.149 46.344 63.011 ;
     RECT  40.032 61.619 40.512 63.013 ;
     RECT  50.736 60.851 51.312 63.107 ;
     RECT  65.376 62.773 67.512 63.155 ;
     RECT  11.904 61.187 11.928 63.205 ;
     RECT  72.384 62.195 72.912 63.205 ;
     RECT  74.112 61.187 74.136 63.205 ;
     RECT  13.2 62.629 14.28 63.251 ;
     RECT  53.376 62.437 53.544 63.251 ;
     RECT  54.864 62.629 55.176 63.251 ;
     RECT  2.4 62.003 4.344 63.299 ;
     RECT  25.632 62.723 25.656 63.299 ;
     RECT  32.448 62.725 33.048 63.299 ;
     RECT  72.384 63.205 74.136 63.395 ;
     RECT  20.208 62.245 20.808 63.443 ;
     RECT  0.144 63.349 0.168 63.539 ;
     RECT  50.88 63.107 51.312 63.539 ;
     RECT  2.4 63.299 3.432 63.635 ;
     RECT  44.448 62.149 44.472 63.779 ;
     RECT  61.008 62.245 63.24 63.781 ;
     RECT  69.36 60.515 69.384 63.781 ;
     RECT  27.648 59.795 27.672 63.829 ;
     RECT  34.8 62.531 35.112 63.877 ;
     RECT  80.112 59.797 81.48 63.973 ;
     RECT  11.904 63.205 12.168 64.019 ;
     RECT  80.016 63.973 81.48 64.019 ;
     RECT  58.656 62.195 58.68 64.067 ;
     RECT  60.96 63.781 63.24 64.307 ;
     RECT  75.36 62.677 75.384 64.307 ;
     RECT  10.368 64.165 10.392 64.355 ;
     RECT  34.8 63.877 35.832 64.355 ;
     RECT  12.144 64.019 12.168 64.357 ;
     RECT  13.2 63.251 13.704 64.357 ;
     RECT  38.736 62.579 38.76 64.357 ;
     RECT  49.296 62.435 49.32 64.357 ;
     RECT  72.6 63.395 74.136 64.357 ;
     RECT  34.8 64.355 35.352 64.405 ;
     RECT  56.4 62.867 56.712 64.405 ;
     RECT  12.144 64.357 13.704 64.451 ;
     RECT  53.376 63.251 53.4 64.451 ;
     RECT  32.688 63.299 33.048 64.549 ;
     RECT  47.088 63.781 47.112 64.595 ;
     RECT  69.36 63.781 70.152 64.595 ;
     RECT  66.24 63.155 67.512 64.645 ;
     RECT  65.52 64.645 67.512 64.691 ;
     RECT  27.648 63.829 27.864 64.693 ;
     RECT  5.136 64.549 5.16 64.739 ;
     RECT  56.4 64.405 56.904 64.883 ;
     RECT  71.232 63.061 71.256 64.883 ;
     RECT  45.6 63.011 45.912 64.885 ;
     RECT  48.864 64.357 49.32 64.979 ;
     RECT  81.024 64.019 81.48 64.979 ;
     RECT  7.008 62.867 8.112 64.981 ;
     RECT  27.312 64.693 27.864 64.981 ;
     RECT  34.704 64.405 35.352 64.981 ;
     RECT  55.152 63.251 55.176 64.981 ;
     RECT  17.088 64.357 17.112 65.027 ;
     RECT  38.448 64.357 38.76 65.027 ;
     RECT  55.152 64.981 55.272 65.027 ;
     RECT  26.88 64.981 27.864 65.029 ;
     RECT  26.88 65.029 28.296 65.077 ;
     RECT  29.4 60.659 30.696 65.077 ;
     RECT  15.552 61.619 15.576 65.123 ;
     RECT  6.384 64.981 8.112 65.171 ;
     RECT  20.208 63.443 20.616 65.171 ;
     RECT  45.6 64.885 46.776 65.171 ;
     RECT  7.008 65.171 8.112 65.221 ;
     RECT  32.496 64.549 33.048 65.221 ;
     RECT  34.608 64.981 35.352 65.221 ;
     RECT  81.168 64.979 81.48 65.221 ;
     RECT  12.144 64.451 13.512 65.267 ;
     RECT  7.008 65.221 8.856 65.315 ;
     RECT  26.88 65.077 31.032 65.315 ;
     RECT  69.36 64.595 69.576 65.411 ;
     RECT  32.496 65.221 35.352 65.507 ;
     RECT  7.152 65.315 8.856 65.509 ;
     RECT  25.392 65.125 25.416 65.555 ;
     RECT  32.496 65.507 33.624 65.651 ;
     RECT  34.704 65.507 35.352 65.653 ;
     RECT  77.568 62.771 78.312 65.653 ;
     RECT  72.6 64.357 74.52 65.699 ;
     RECT  18.6 55.907 18.912 65.701 ;
     RECT  34.704 65.653 35.928 65.795 ;
     RECT  32.688 65.651 33.624 65.843 ;
     RECT  77.568 65.653 78.504 65.891 ;
     RECT  65.52 64.691 65.544 65.893 ;
     RECT  13.104 65.267 13.512 65.939 ;
     RECT  49.152 64.979 49.32 65.939 ;
     RECT  63.216 64.307 63.24 65.939 ;
     RECT  24 62.771 24.312 65.941 ;
     RECT  24 65.941 24.504 66.083 ;
     RECT  13.2 65.939 13.512 66.085 ;
     RECT  29.4 65.315 31.032 66.085 ;
     RECT  27.312 65.315 28.296 66.131 ;
     RECT  32.688 65.843 32.808 66.131 ;
     RECT  49.296 65.939 49.32 66.323 ;
     RECT  45.6 65.171 45.912 66.373 ;
     RECT  13.2 66.085 13.608 66.469 ;
     RECT  15.456 66.229 15.48 66.469 ;
     RECT  20.208 65.171 20.232 66.517 ;
     RECT  13.2 66.469 13.8 66.611 ;
     RECT  15.12 66.469 15.48 66.611 ;
     RECT  32.688 66.131 32.76 66.659 ;
     RECT  2.4 63.635 2.712 66.661 ;
     RECT  20.208 66.517 21.192 66.661 ;
     RECT  76.272 66.325 76.296 66.661 ;
     RECT  13.2 66.611 13.656 66.707 ;
     RECT  20.208 66.661 21.768 66.707 ;
     RECT  34.704 65.795 35.112 66.755 ;
     RECT  65.136 65.893 65.544 66.755 ;
     RECT  74.928 66.661 76.296 66.755 ;
     RECT  2.4 66.661 3.48 66.803 ;
     RECT  66.72 64.691 67.512 66.853 ;
     RECT  80.016 64.019 80.04 66.853 ;
     RECT  81.168 65.221 81.672 66.853 ;
     RECT  74.928 66.755 76.248 66.995 ;
     RECT  72.6 65.699 73.752 67.141 ;
     RECT  38.736 65.027 38.76 67.189 ;
     RECT  40.032 63.013 40.632 67.189 ;
     RECT  77.568 65.891 78.312 67.189 ;
     RECT  27.84 66.131 28.296 67.237 ;
     RECT  29.4 66.085 31.272 67.283 ;
     RECT  60.96 64.307 62.112 67.283 ;
     RECT  34.8 66.755 35.112 67.285 ;
     RECT  13.2 66.707 13.608 67.331 ;
     RECT  27.792 67.237 28.296 67.331 ;
     RECT  26.208 66.661 26.232 67.333 ;
     RECT  29.4 67.283 30.696 67.379 ;
     RECT  26.208 67.333 26.616 67.381 ;
     RECT  61.584 67.283 62.112 67.427 ;
     RECT  7.152 65.509 9.336 67.477 ;
     RECT  38.736 67.189 40.632 67.477 ;
     RECT  38.448 67.477 40.632 67.523 ;
     RECT  65.136 66.755 65.16 67.573 ;
     RECT  0.192 67.477 0.216 67.667 ;
     RECT  15.456 66.611 15.48 67.667 ;
     RECT  72.6 67.141 73.8 67.669 ;
     RECT  74.928 66.995 74.952 67.669 ;
     RECT  29.4 67.379 29.976 67.717 ;
     RECT  55.248 65.027 55.272 67.765 ;
     RECT  61.632 67.427 62.112 67.811 ;
     RECT  80.016 66.853 81.672 67.811 ;
     RECT  69.552 65.411 69.576 67.813 ;
     RECT  66.72 66.853 68.136 67.859 ;
     RECT  29.28 67.717 29.976 68.099 ;
     RECT  43.248 67.237 43.272 68.099 ;
     RECT  45.6 66.373 46.728 68.099 ;
     RECT  25.776 67.381 26.616 68.195 ;
     RECT  18.6 65.701 19.032 68.243 ;
     RECT  59.088 67.189 59.112 68.245 ;
     RECT  72.6 67.669 74.952 68.245 ;
     RECT  58.368 68.245 59.112 68.291 ;
     RECT  24 66.083 24.312 68.293 ;
     RECT  72.336 68.245 74.952 68.341 ;
     RECT  77.472 67.189 78.312 68.341 ;
     RECT  80.016 67.811 81.24 68.341 ;
     RECT  20.208 66.707 20.232 68.435 ;
     RECT  53.04 67.237 53.064 68.435 ;
     RECT  72.336 68.341 75.24 68.483 ;
     RECT  21.744 66.707 21.768 68.627 ;
     RECT  7.152 67.477 9.384 68.771 ;
     RECT  34.8 67.285 35.208 68.771 ;
     RECT  39.6 67.523 40.632 68.819 ;
     RECT  64.848 67.573 65.16 68.819 ;
     RECT  51 63.539 51.312 68.821 ;
     RECT  7.152 68.771 9.192 68.917 ;
     RECT  13.2 67.331 13.512 68.917 ;
     RECT  61.68 67.811 62.112 68.917 ;
     RECT  66.816 67.859 68.136 68.917 ;
     RECT  76.224 66.995 76.248 68.917 ;
     RECT  41.616 68.101 41.64 68.963 ;
     RECT  55.2 67.765 55.272 68.963 ;
     RECT  69.552 67.813 70.344 68.963 ;
     RECT  75.984 68.917 76.248 68.963 ;
     RECT  77.472 68.341 81.24 68.963 ;
     RECT  29.4 68.099 29.976 69.011 ;
     RECT  69.648 68.963 70.344 69.011 ;
     RECT  77.472 68.963 80.04 69.011 ;
     RECT  72.336 68.483 73.752 69.013 ;
     RECT  6.336 68.917 9.192 69.107 ;
     RECT  27.792 67.331 27.96 69.251 ;
     RECT  34.8 68.771 35.112 69.301 ;
     RECT  83.04 60.277 83.712 69.349 ;
     RECT  23.76 68.293 24.312 69.443 ;
     RECT  25.776 68.195 26.088 69.445 ;
     RECT  13.2 68.917 14.088 69.491 ;
     RECT  27.792 69.251 27.816 69.491 ;
     RECT  74.928 68.483 74.952 69.493 ;
     RECT  75.984 68.963 76.008 69.493 ;
     RECT  58.368 68.291 58.392 69.539 ;
     RECT  74.928 69.493 76.008 69.539 ;
     RECT  31.152 68.341 31.176 69.587 ;
     RECT  69.648 69.011 69.72 69.587 ;
     RECT  61.584 68.917 62.112 69.685 ;
     RECT  10.8 68.773 10.824 69.731 ;
     RECT  77.472 69.011 78.744 69.731 ;
     RECT  77.52 69.731 78.744 69.971 ;
     RECT  71.808 69.013 73.752 70.019 ;
     RECT  51 68.821 51.864 70.021 ;
     RECT  53.424 68.917 53.448 70.067 ;
     RECT  56.4 64.883 56.712 70.069 ;
     RECT  81.12 68.963 81.24 70.069 ;
     RECT  3.936 68.917 3.96 70.115 ;
     RECT  34.224 69.301 35.112 70.163 ;
     RECT  71.952 70.019 73.752 70.163 ;
     RECT  51 70.021 52.44 70.259 ;
     RECT  6.336 69.107 8.952 70.357 ;
     RECT  32.688 66.659 32.712 70.357 ;
     RECT  32.688 70.357 33.048 70.403 ;
     RECT  45.6 68.099 45.912 70.405 ;
     RECT  12.048 67.669 12.072 70.499 ;
     RECT  34.8 70.163 35.112 70.645 ;
     RECT  64.896 68.819 65.16 70.645 ;
     RECT  36.624 69.829 36.648 70.691 ;
     RECT  66.528 68.917 68.136 70.691 ;
     RECT  52.416 70.259 52.44 70.739 ;
     RECT  64.896 70.645 65.544 70.739 ;
     RECT  82.608 69.349 83.712 70.739 ;
     RECT  25.344 69.445 26.088 70.835 ;
     RECT  31.2 69.877 31.224 70.835 ;
     RECT  77.52 69.971 78.312 70.835 ;
     RECT  80.016 69.011 80.04 70.837 ;
     RECT  81.072 70.069 81.24 70.837 ;
     RECT  75.024 69.539 76.008 70.931 ;
     RECT  0.144 69.301 0.168 70.979 ;
     RECT  24 69.443 24.312 71.077 ;
     RECT  65.088 70.739 65.544 71.123 ;
     RECT  77.904 70.835 78.312 71.125 ;
     RECT  17.328 69.493 17.352 71.267 ;
     RECT  21.504 70.117 21.528 71.315 ;
     RECT  75.024 70.931 75.048 71.363 ;
     RECT  83.04 70.739 83.712 71.411 ;
     RECT  34.8 70.645 35.352 71.459 ;
     RECT  33.024 70.403 33.048 71.509 ;
     RECT  13.2 69.491 13.512 71.605 ;
     RECT  56.4 70.069 56.808 71.747 ;
     RECT  80.016 70.837 81.24 71.749 ;
     RECT  66.528 70.691 67.512 71.843 ;
     RECT  80.016 71.749 82.056 71.843 ;
     RECT  33.024 71.509 33.528 71.891 ;
     RECT  60.768 69.685 62.112 71.939 ;
     RECT  29.4 69.011 29.712 71.989 ;
     RECT  69.696 69.587 69.72 72.229 ;
     RECT  18.6 68.243 18.912 72.325 ;
     RECT  65.088 71.123 65.112 72.325 ;
     RECT  5.808 70.357 8.952 72.373 ;
     RECT  5.808 72.373 9.096 72.419 ;
     RECT  82.032 71.843 82.056 72.419 ;
     RECT  66.816 71.843 67.512 72.467 ;
     RECT  71.952 70.163 73.416 72.467 ;
     RECT  36.768 71.989 36.792 72.517 ;
     RECT  33.504 71.891 33.528 72.563 ;
     RECT  11.568 71.557 11.592 72.707 ;
     RECT  61.488 71.939 62.112 72.707 ;
     RECT  23.28 71.077 24.312 72.709 ;
     RECT  25.344 70.835 25.8 72.709 ;
     RECT  23.28 72.709 25.8 72.755 ;
     RECT  29.4 71.989 30.696 72.755 ;
     RECT  38.448 67.523 38.472 72.803 ;
     RECT  69.216 72.229 69.72 72.805 ;
     RECT  77.904 71.125 78.648 72.901 ;
     RECT  80.016 71.843 80.904 72.901 ;
     RECT  65.088 72.325 65.16 72.947 ;
     RECT  6.912 72.419 9.096 72.995 ;
     RECT  23.28 72.755 25.368 72.995 ;
     RECT  36.768 72.517 37.32 72.995 ;
     RECT  77.904 72.901 80.904 72.995 ;
     RECT  76.416 72.901 76.44 72.997 ;
     RECT  77.904 72.995 79.224 72.997 ;
     RECT  7.8 72.995 9.096 73.043 ;
     RECT  76.416 72.997 79.224 73.139 ;
     RECT  44.544 72.133 44.568 73.235 ;
     RECT  7.8 73.043 8.856 73.379 ;
     RECT  71.952 72.467 73.32 73.379 ;
     RECT  42.24 73.045 42.264 73.381 ;
     RECT  65.088 72.947 65.112 73.475 ;
     RECT  42.24 73.381 42.936 73.477 ;
     RECT  42.144 73.477 42.936 73.523 ;
     RECT  36.768 72.995 36.792 73.571 ;
     RECT  45.6 70.405 46.44 73.811 ;
     RECT  80.88 72.995 80.904 73.859 ;
     RECT  58.752 71.653 58.776 74.005 ;
     RECT  18.288 72.325 18.912 74.053 ;
     RECT  23.28 72.995 24.504 74.053 ;
     RECT  45.6 73.811 45.912 74.101 ;
     RECT  55.248 68.963 55.272 74.147 ;
     RECT  72.6 73.379 73.32 74.147 ;
     RECT  58.752 74.005 58.92 74.149 ;
     RECT  39.6 68.819 40.512 74.195 ;
     RECT  58.704 74.149 58.92 74.195 ;
     RECT  42.144 73.523 42.168 74.291 ;
     RECT  54.384 74.149 54.408 74.291 ;
     RECT  58.704 74.195 58.824 74.291 ;
     RECT  21.648 72.661 21.672 74.293 ;
     RECT  20.784 74.293 21.672 74.339 ;
     RECT  67.2 72.467 67.512 74.341 ;
     RECT  16.56 73.621 16.584 74.579 ;
     RECT  18.288 74.053 19.656 74.579 ;
     RECT  61.8 72.707 62.112 74.581 ;
     RECT  13.2 71.605 13.608 74.627 ;
     RECT  18.6 74.579 19.656 74.675 ;
     RECT  7.8 73.379 8.568 74.723 ;
     RECT  58.8 74.291 58.824 74.723 ;
     RECT  66.72 74.341 67.512 75.109 ;
     RECT  68.88 72.805 69.72 75.109 ;
     RECT  76.416 73.139 76.44 75.251 ;
     RECT  5.808 72.419 5.832 75.299 ;
     RECT  14.784 73.621 14.808 75.299 ;
     RECT  20.784 74.339 20.808 75.299 ;
     RECT  61.488 74.581 62.112 75.395 ;
     RECT  66.72 75.109 69.72 75.395 ;
     RECT  23.232 74.053 24.504 75.443 ;
     RECT  44.832 74.101 45.912 75.443 ;
     RECT  24 75.443 24.504 75.491 ;
     RECT  67.2 75.395 69.72 75.541 ;
     RECT  78 73.139 79.224 75.541 ;
     RECT  67.2 75.541 70.056 75.589 ;
     RECT  2.4 66.803 2.712 75.609 ;
     RECT  7.8 74.723 8.112 75.609 ;
     RECT  13.2 74.627 13.512 75.609 ;
     RECT  18.6 74.675 18.912 75.609 ;
     RECT  24 75.491 24.312 75.609 ;
     RECT  29.4 72.755 29.712 75.609 ;
     RECT  34.8 71.459 35.112 75.609 ;
     RECT  40.2 74.195 40.512 75.609 ;
     RECT  45.6 75.443 45.912 75.609 ;
     RECT  51 70.259 51.312 75.609 ;
     RECT  56.4 71.747 56.712 75.609 ;
     RECT  61.8 75.395 62.112 75.609 ;
     RECT  72.6 74.147 72.912 75.609 ;
     RECT  83.4 71.411 83.712 75.609 ;
     RECT  2.4 75.609 2.52 75.623 ;
     RECT  7.8 75.609 7.92 75.623 ;
     RECT  13.2 75.609 13.32 75.623 ;
     RECT  18.6 75.609 18.72 75.623 ;
     RECT  24 75.609 24.12 75.623 ;
     RECT  29.4 75.609 29.52 75.623 ;
     RECT  34.8 75.609 34.92 75.623 ;
     RECT  40.2 75.609 40.32 75.623 ;
     RECT  45.6 75.609 45.72 75.623 ;
     RECT  51 75.609 51.12 75.623 ;
     RECT  56.4 75.609 56.52 75.623 ;
     RECT  61.8 75.609 61.92 75.623 ;
     RECT  67.2 75.589 70.152 75.623 ;
     RECT  72.6 75.609 72.72 75.623 ;
     RECT  83.4 75.609 83.52 75.623 ;
     RECT  76.464 75.541 76.488 75.781 ;
     RECT  76.464 75.781 76.872 75.829 ;
     RECT  78 75.541 79.464 75.829 ;
     RECT  67.92 75.623 70.152 77.509 ;
     RECT  67.92 77.509 70.248 77.712 ;
     RECT  76.464 75.829 79.464 77.712 ;
     RECT  14.472 1.859 15.696 3.925 ;
     RECT  38.808 2.485 40.2 3.731 ;
     RECT  76.824 2.485 78 3.443 ;
     RECT  10.824 2.677 12.048 3.299 ;
     RECT  33.528 2.773 34.8 4.501 ;
     RECT  64.44 2.821 65.568 3.875 ;
     RECT  65.592 2.821 67.104 3.875 ;
     RECT  62.808 3.013 63.84 4.069 ;
     RECT  27.96 3.157 29.4 4.837 ;
     RECT  11.376 3.299 12.048 3.397 ;
     RECT  72.912 3.301 74.304 3.973 ;
     RECT  38.184 3.731 40.2 4.885 ;
     RECT  29.88 3.925 31.296 4.261 ;
     RECT  31.32 3.925 32.784 6.899 ;
     RECT  73.08 3.973 74.304 5.171 ;
     RECT  17.256 4.019 18.24 5.605 ;
     RECT  63.096 4.115 64.416 4.643 ;
     RECT  30.264 4.261 31.296 4.933 ;
     RECT  67.608 4.453 69.072 5.603 ;
     RECT  33.624 4.501 34.8 7.381 ;
     RECT  48.744 4.501 49.776 5.125 ;
     RECT  13.008 4.595 13.2 5.605 ;
     RECT  57.336 4.595 57.384 5.605 ;
     RECT  63.096 4.643 63.624 6.037 ;
     RECT  51.624 4.691 52.656 4.739 ;
     RECT  51.576 4.739 52.656 5.171 ;
     RECT  28.344 4.837 29.4 6.565 ;
     RECT  38.664 4.885 40.2 4.981 ;
     RECT  38.808 4.981 40.2 5.123 ;
     RECT  44.424 5.077 45.6 5.891 ;
     RECT  38.664 5.123 40.2 6.277 ;
     RECT  51.576 5.171 52.752 6.371 ;
     RECT  72.912 5.171 74.304 6.229 ;
     RECT  19.8 5.221 21.072 5.365 ;
     RECT  21.144 5.507 21.672 6.133 ;
     RECT  67.512 5.603 69.072 6.709 ;
     RECT  57.864 5.605 59.328 5.893 ;
     RECT  48.744 5.747 49.776 6.805 ;
     RECT  44.4 5.891 45.6 6.661 ;
     RECT  72.384 5.987 72.48 7.237 ;
     RECT  11.784 5.989 12.912 6.085 ;
     RECT  24.456 5.989 25.632 6.421 ;
     RECT  21.144 6.133 22.464 7.189 ;
     RECT  22.488 6.133 23.472 7.957 ;
     RECT  38.76 6.277 40.2 8.485 ;
     RECT  51.576 6.371 53.184 6.661 ;
     RECT  24.408 6.659 25.632 7.379 ;
     RECT  43.944 6.661 45.6 7.333 ;
     RECT  51.624 6.661 53.184 7.333 ;
     RECT  65.592 6.661 67.104 8.003 ;
     RECT  67.608 6.709 69.072 7.381 ;
     RECT  28.344 6.803 29.4 8.003 ;
     RECT  69.24 6.899 70.56 9.779 ;
     RECT  21.24 7.189 22.464 8.675 ;
     RECT  44.472 7.333 45.6 8.003 ;
     RECT  51.624 7.333 52.752 7.669 ;
     RECT  24.312 7.379 25.632 7.907 ;
     RECT  24.312 7.907 24.792 9.253 ;
     RECT  6.6 7.957 7.8 9.011 ;
     RECT  27.96 8.003 29.4 9.637 ;
     RECT  65.568 8.003 67.104 8.245 ;
     RECT  65.568 8.245 66.912 8.533 ;
     RECT  40.512 8.533 41.808 11.603 ;
     RECT  65.568 8.533 66.72 8.917 ;
     RECT  8.808 8.723 9.096 10.021 ;
     RECT  30.744 8.867 31.32 9.829 ;
     RECT  67.512 8.867 68.544 9.107 ;
     RECT  65.568 8.917 66.432 9.301 ;
     RECT  26.424 8.965 27.936 9.061 ;
     RECT  35.112 8.965 36.096 9.779 ;
     RECT  26.664 9.061 27.936 10.405 ;
     RECT  59.352 9.107 60.336 10.501 ;
     RECT  65.4 9.301 66.432 9.731 ;
     RECT  70.728 9.493 72 10.163 ;
     RECT  22.488 9.635 23.472 9.731 ;
     RECT  72.912 9.635 74.16 9.731 ;
     RECT  27.96 9.637 29.28 11.171 ;
     RECT  81.192 9.685 82.56 9.731 ;
     RECT  65.4 9.731 66.72 10.259 ;
     RECT  35.112 9.779 36.864 10.069 ;
     RECT  69.192 9.779 70.56 11.941 ;
     RECT  49.08 10.067 50.112 12.805 ;
     RECT  35.352 10.069 36.864 10.789 ;
     RECT  70.584 10.163 72 10.307 ;
     RECT  8.112 10.451 9.096 11.941 ;
     RECT  57.864 10.451 58.944 12.517 ;
     RECT  26.664 10.643 27.936 17.795 ;
     RECT  48.96 10.787 49.056 11.941 ;
     RECT  35.352 10.789 36.432 12.035 ;
     RECT  63.768 10.789 64.992 10.883 ;
     RECT  42.216 10.883 42.792 11.845 ;
     RECT  76.104 10.883 77.232 13.331 ;
     RECT  27.96 11.171 29.4 13.093 ;
     RECT  67.848 11.365 69.168 11.941 ;
     RECT  59.352 11.459 60.768 12.517 ;
     RECT  64.992 11.507 65.016 12.517 ;
     RECT  40.512 11.603 42.192 12.853 ;
     RECT  42.6 11.845 42.792 12.373 ;
     RECT  78.696 11.845 79.92 12.563 ;
     RECT  8.112 11.941 9.504 12.181 ;
     RECT  20.424 11.941 21.456 22.069 ;
     RECT  36.888 11.941 38.256 13.379 ;
     RECT  67.848 11.941 69.12 13.093 ;
     RECT  69.192 11.941 70.32 12.227 ;
     RECT  35.352 12.035 36.864 12.083 ;
     RECT  8.28 12.181 9.504 16.453 ;
     RECT  69.144 12.227 70.32 13.477 ;
     RECT  66.72 12.515 66.96 12.517 ;
     RECT  64.152 12.517 65.328 13.621 ;
     RECT  65.352 12.517 66.96 13.045 ;
     RECT  30.792 12.803 31.776 13.187 ;
     RECT  40.512 12.853 41.568 13.139 ;
     RECT  65.544 13.045 66.96 14.771 ;
     RECT  28.296 13.093 29.4 14.867 ;
     RECT  67.848 13.093 69.072 14.725 ;
     RECT  40.512 13.139 41.616 16.595 ;
     RECT  58.968 13.139 60.768 13.427 ;
     RECT  30.792 13.187 31.824 14.051 ;
     RECT  76.104 13.331 77.472 14.723 ;
     RECT  10.392 13.333 11.76 13.571 ;
     RECT  58.536 13.427 60.768 14.245 ;
     RECT  71.496 13.523 72.48 15.445 ;
     RECT  64.152 13.621 65.184 14.099 ;
     RECT  41.64 13.715 42.96 16.595 ;
     RECT  30.744 14.051 31.824 16.309 ;
     RECT  63.288 14.099 65.184 14.197 ;
     RECT  63.288 14.197 64.512 15.491 ;
     RECT  14.856 14.243 16.08 15.731 ;
     RECT  58.536 14.245 59.808 14.867 ;
     RECT  76.104 14.723 77.568 17.891 ;
     RECT  67.848 14.725 68.928 16.501 ;
     RECT  57.336 14.771 58.464 15.251 ;
     RECT  27.96 14.867 29.4 15.445 ;
     RECT  52.824 14.867 54.048 14.963 ;
     RECT  58.536 14.867 60.048 15.251 ;
     RECT  52.776 14.963 54.048 15.925 ;
     RECT  35.112 15.011 35.304 15.637 ;
     RECT  36.888 15.205 38.064 15.589 ;
     RECT  57.336 15.251 60.048 15.589 ;
     RECT  5.736 15.253 7.152 15.923 ;
     RECT  72.912 15.349 74.064 16.019 ;
     RECT  75.792 15.443 76.08 15.541 ;
     RECT  27.96 15.445 29.088 16.021 ;
     RECT  62.808 15.491 64.512 15.829 ;
     RECT  74.616 15.541 76.08 15.779 ;
     RECT  57.336 15.589 58.8 18.515 ;
     RECT  58.824 15.589 60.048 16.163 ;
     RECT  35.112 15.637 36.48 16.597 ;
     RECT  14.808 15.731 16.08 17.173 ;
     RECT  25.08 15.829 26.4 16.115 ;
     RECT  62.808 15.829 63.888 16.981 ;
     RECT  70.44 15.971 71.472 18.275 ;
     RECT  9.528 15.973 10.944 16.547 ;
     RECT  16.2 16.019 17.184 19.525 ;
     RECT  27.96 16.021 29.04 16.069 ;
     RECT  24.312 16.115 24.456 17.173 ;
     RECT  26.352 16.115 26.4 16.789 ;
     RECT  58.824 16.163 60.432 17.125 ;
     RECT  71.496 16.259 72.48 17.461 ;
     RECT  30.744 16.309 31.728 16.501 ;
     RECT  8.472 16.453 9.504 17.077 ;
     RECT  67.944 16.501 68.928 17.459 ;
     RECT  9.528 16.547 11.76 17.077 ;
     RECT  35.256 16.597 36.48 17.315 ;
     RECT  5.496 16.835 5.736 18.133 ;
     RECT  10.728 17.077 11.76 17.363 ;
     RECT  26.4 17.171 26.448 18.565 ;
     RECT  27.96 17.219 29.4 17.795 ;
     RECT  35.208 17.315 36.48 17.411 ;
     RECT  10.584 17.363 11.76 19.955 ;
     RECT  35.112 17.411 36.48 18.131 ;
     RECT  14.808 17.459 16.176 20.245 ;
     RECT  67.944 17.459 68.976 17.699 ;
     RECT  66.12 17.509 67.2 18.275 ;
     RECT  48.648 17.699 50.112 19.141 ;
     RECT  67.512 17.699 68.976 18.275 ;
     RECT  28.656 17.795 29.4 18.181 ;
     RECT  22.008 17.845 23.04 18.133 ;
     RECT  76.944 17.891 77.568 17.989 ;
     RECT  35.112 18.131 37.584 18.565 ;
     RECT  6.312 18.133 7.8 19.811 ;
     RECT  65.736 18.275 67.2 19.427 ;
     RECT  70.44 18.275 72.48 18.613 ;
     RECT  52.824 18.419 54.048 20.293 ;
     RECT  35.112 18.565 36.384 19.381 ;
     RECT  36.408 18.565 37.584 21.205 ;
     RECT  71.256 18.613 72.48 18.803 ;
     RECT  38.088 18.803 39.264 24.421 ;
     RECT  2.856 18.947 3 19.669 ;
     RECT  60.672 19.043 60.768 20.485 ;
     RECT  40.512 19.093 41.712 20.099 ;
     RECT  41.736 19.093 42.96 19.427 ;
     RECT  35.208 19.381 36.384 21.925 ;
     RECT  43.776 19.427 43.92 20.003 ;
     RECT  65.16 19.427 67.2 19.811 ;
     RECT  9.528 19.667 10.56 19.955 ;
     RECT  2.856 19.669 4.224 19.811 ;
     RECT  2.712 19.811 4.224 20.195 ;
     RECT  7.056 19.811 7.8 20.725 ;
     RECT  66.48 19.811 67.2 19.861 ;
     RECT  67.512 19.909 68.976 20.195 ;
     RECT  9.528 19.955 11.76 21.397 ;
     RECT  43.776 20.003 43.8 20.773 ;
     RECT  78.312 20.003 78.936 21.301 ;
     RECT  28.656 20.099 29.4 21.109 ;
     RECT  22.008 20.195 23.04 20.339 ;
     RECT  53.016 20.293 54.048 20.435 ;
     RECT  22.008 20.339 23.472 21.299 ;
     RECT  48.624 20.339 49.2 20.965 ;
     RECT  52.44 20.435 54.048 20.437 ;
     RECT  52.44 20.437 53.856 21.445 ;
     RECT  32.088 20.581 33.168 20.963 ;
     RECT  63.048 20.723 64.224 22.453 ;
     RECT  7.056 20.725 7.68 20.965 ;
     RECT  24.504 20.869 25.536 21.107 ;
     RECT  32.088 20.963 32.904 21.205 ;
     RECT  47.88 20.965 49.2 22.741 ;
     RECT  7.488 21.107 7.68 22.165 ;
     RECT  28.656 21.109 29.04 21.445 ;
     RECT  42.6 21.109 43.776 21.827 ;
     RECT  21.624 21.299 23.472 21.493 ;
     RECT  78.312 21.301 79.776 22.741 ;
     RECT  14.808 21.395 16.176 29.221 ;
     RECT  9.528 21.397 10.944 22.259 ;
     RECT  24.456 21.443 24.504 22.741 ;
     RECT  52.44 21.445 53.52 21.637 ;
     RECT  21.624 21.493 22.8 21.731 ;
     RECT  81.528 21.493 82.848 22.165 ;
     RECT  32.52 21.539 32.904 22.741 ;
     RECT  21.624 21.731 23.04 22.837 ;
     RECT  35.256 21.925 36.384 23.317 ;
     RECT  46.824 22.069 47.856 22.787 ;
     RECT  81.504 22.451 82.032 22.741 ;
     RECT  32.52 22.741 33.6 24.323 ;
     RECT  33.624 22.741 34.8 24.323 ;
     RECT  47.88 22.741 49.056 22.787 ;
     RECT  80.52 22.741 82.032 23.411 ;
     RECT  46.824 22.787 49.056 23.125 ;
     RECT  53.064 22.835 54.192 23.267 ;
     RECT  21.624 22.837 22.752 23.557 ;
     RECT  47.592 23.125 49.056 26.917 ;
     RECT  67.512 23.269 68.976 24.659 ;
     RECT  49.08 23.315 50.112 29.459 ;
     RECT  55.272 23.315 56.4 26.483 ;
     RECT  26.664 23.365 27.744 23.893 ;
     RECT  80.52 23.411 82.32 23.605 ;
     RECT  60.672 23.603 60.816 24.805 ;
     RECT  81.192 23.605 82.32 25.573 ;
     RECT  36.408 23.795 37.68 24.853 ;
     RECT  26.76 23.893 27.744 24.659 ;
     RECT  21.624 23.939 22.752 24.323 ;
     RECT  26.448 23.939 26.64 24.997 ;
     RECT  62.952 23.987 64.032 24.707 ;
     RECT  78.312 24.131 79.776 26.677 ;
     RECT  21.624 24.323 22.8 25.477 ;
     RECT  32.52 24.323 33.096 24.901 ;
     RECT  10.248 24.325 11.232 26.003 ;
     RECT  79.8 24.371 80.928 25.187 ;
     RECT  16.2 24.467 17.184 27.013 ;
     RECT  36.456 24.853 37.68 25.091 ;
     RECT  35.256 24.899 36.384 27.347 ;
     RECT  24.312 24.997 25.344 25.141 ;
     RECT  25.368 24.997 26.64 29.077 ;
     RECT  36.456 25.091 38.592 25.141 ;
     RECT  37.368 25.141 38.592 25.283 ;
     RECT  79.8 25.187 81.168 26.771 ;
     RECT  21.624 25.619 22.8 27.347 ;
     RECT  62.904 25.715 62.952 26.725 ;
     RECT  81.48 25.715 82.848 26.723 ;
     RECT  74.712 26.149 75.792 26.533 ;
     RECT  55.224 26.483 56.4 26.819 ;
     RECT  72.912 26.581 74.208 27.587 ;
     RECT  78.312 26.677 79.488 29.123 ;
     RECT  81.192 26.723 82.848 26.917 ;
     RECT  62.904 26.725 64.08 27.587 ;
     RECT  54.936 26.819 56.4 28.211 ;
     RECT  47.976 26.917 49.056 29.413 ;
     RECT  81.192 26.917 82.224 27.923 ;
     RECT  47.568 26.963 47.952 27.877 ;
     RECT  53.256 27.061 54.336 28.403 ;
     RECT  26.664 27.107 26.856 27.877 ;
     RECT  21.48 27.347 22.8 27.589 ;
     RECT  35.208 27.347 36.384 27.923 ;
     RECT  82.248 27.395 83.4 27.923 ;
     RECT  62.904 27.587 64.056 27.877 ;
     RECT  21.48 27.589 22.752 30.275 ;
     RECT  44.568 27.731 45.6 29.411 ;
     RECT  16.2 27.779 17.184 29.653 ;
     RECT  2.712 27.877 4.128 30.709 ;
     RECT  26.664 27.877 27.888 28.933 ;
     RECT  46.44 27.877 47.952 29.075 ;
     RECT  62.904 27.877 64.032 29.219 ;
     RECT  35.112 27.923 36.384 39.061 ;
     RECT  57.768 28.067 57.864 28.165 ;
     RECT  57.768 28.165 58.8 28.451 ;
     RECT  54.888 28.211 56.4 29.893 ;
     RECT  9.144 28.403 9.528 29.365 ;
     RECT  54.24 28.403 54.336 29.797 ;
     RECT  57.528 28.451 58.8 32.341 ;
     RECT  19.176 28.547 20.208 29.075 ;
     RECT  13.512 28.739 14.544 29.267 ;
     RECT  36.84 28.933 38.064 29.123 ;
     RECT  19.176 29.075 20.4 30.037 ;
     RECT  45.912 29.075 47.952 30.325 ;
     RECT  25.464 29.077 26.64 29.701 ;
     RECT  78.312 29.123 79.584 34.741 ;
     RECT  14.808 29.221 15.936 34.885 ;
     RECT  13.512 29.267 14.784 33.829 ;
     RECT  26.664 29.363 27.888 29.555 ;
     RECT  9.144 29.365 10.368 29.653 ;
     RECT  10.392 29.365 11.808 29.699 ;
     RECT  45.12 29.411 45.6 30.229 ;
     RECT  11.088 29.699 11.808 29.749 ;
     RECT  25.56 29.701 26.64 36.515 ;
     RECT  54.984 29.893 56.4 32.293 ;
     RECT  24.504 30.227 25.536 31.861 ;
     RECT  46.44 30.325 47.952 30.565 ;
     RECT  11.112 30.419 12.144 31.571 ;
     RECT  33.72 30.469 34.8 31.955 ;
     RECT  16.2 30.563 17.184 34.259 ;
     RECT  46.44 30.565 47.904 30.851 ;
     RECT  72.912 30.805 74.352 34.453 ;
     RECT  46.44 30.851 47.952 31.909 ;
     RECT  2.712 30.899 4.128 31.861 ;
     RECT  19.272 31.283 20.4 32.965 ;
     RECT  11.088 31.571 12.144 32.965 ;
     RECT  66.024 31.669 67.2 33.541 ;
     RECT  46.44 31.909 47.904 33.205 ;
     RECT  34.704 31.955 34.8 32.293 ;
     RECT  8.856 32.051 9.528 33.061 ;
     RECT  68.376 32.053 69.792 33.107 ;
     RECT  72.24 32.099 72.6 32.965 ;
     RECT  38.616 32.291 39.792 37.333 ;
     RECT  57.528 32.341 58.656 34.259 ;
     RECT  43.896 32.437 45.12 32.483 ;
     RECT  30.744 32.531 31.824 35.987 ;
     RECT  74.376 32.531 75.504 33.587 ;
     RECT  17.208 32.723 18.192 34.259 ;
     RECT  11.088 32.965 11.424 33.061 ;
     RECT  19.272 32.965 20.304 33.011 ;
     RECT  71.4 32.965 72.6 33.589 ;
     RECT  19.176 33.011 20.304 34.213 ;
     RECT  24.552 33.011 25.536 35.749 ;
     RECT  8.856 33.061 9.888 33.491 ;
     RECT  9.912 33.061 11.424 33.109 ;
     RECT  69.408 33.107 69.792 33.349 ;
     RECT  9.912 33.109 11.232 33.251 ;
     RECT  32.088 33.109 33.072 35.749 ;
     RECT  46.872 33.205 47.904 33.347 ;
     RECT  9.912 33.251 11.424 33.491 ;
     RECT  28.392 33.347 29.4 36.901 ;
     RECT  46.44 33.347 47.904 34.211 ;
     RECT  37.032 33.397 38.4 33.875 ;
     RECT  71.544 33.589 72.6 38.003 ;
     RECT  54.888 33.731 56.4 37.477 ;
     RECT  80.04 33.781 81.264 33.827 ;
     RECT  81.384 33.781 82.416 33.923 ;
     RECT  2.712 33.827 4.224 36.131 ;
     RECT  80.04 33.827 81.36 33.923 ;
     RECT  13.656 33.829 14.784 33.971 ;
     RECT  36.456 33.875 38.4 34.259 ;
     RECT  58.824 33.925 60.192 34.787 ;
     RECT  60.216 33.925 61.296 34.787 ;
     RECT  13.512 33.971 14.784 35.317 ;
     RECT  46.44 34.211 47.952 35.843 ;
     RECT  16.2 34.259 18.192 34.451 ;
     RECT  34.704 34.259 34.8 35.173 ;
     RECT  36.456 34.259 38.592 35.317 ;
     RECT  57.528 34.259 58.8 36.131 ;
     RECT  69.744 34.403 69.792 35.509 ;
     RECT  15.96 34.451 18.192 34.549 ;
     RECT  72.912 34.453 74.064 35.363 ;
     RECT  15.96 34.549 17.28 34.931 ;
     RECT  48.648 34.741 50.112 34.979 ;
     RECT  52.344 34.741 53.664 35.891 ;
     RECT  78.312 34.741 79.44 35.363 ;
     RECT  33.336 35.173 34.8 36.517 ;
     RECT  36.456 35.317 37.584 35.797 ;
     RECT  37.608 35.317 38.592 37.475 ;
     RECT  78.312 35.363 79.584 38.243 ;
     RECT  48.408 35.411 48.456 36.853 ;
     RECT  46.44 35.843 48.336 36.997 ;
     RECT  30.744 35.987 32.064 36.997 ;
     RECT  26.664 36.037 27.84 38.243 ;
     RECT  33.336 36.517 34.368 37.043 ;
     RECT  46.44 36.997 47.904 40.979 ;
     RECT  33.336 37.043 34.8 42.227 ;
     RECT  62.52 37.379 62.568 37.667 ;
     RECT  19.176 37.475 20.256 39.395 ;
     RECT  37.608 37.475 38.64 38.147 ;
     RECT  54.888 37.477 56.304 38.485 ;
     RECT  38.664 37.571 39.792 38.915 ;
     RECT  13.608 37.667 14.784 38.195 ;
     RECT  62.424 37.667 62.568 38.821 ;
     RECT  71.568 38.003 72.6 38.437 ;
     RECT  48.504 38.149 49.872 39.589 ;
     RECT  26.832 38.243 27.84 38.771 ;
     RECT  28.392 38.243 29.4 39.301 ;
     RECT  51.768 38.243 52.344 39.253 ;
     RECT  78.312 38.243 79.728 40.885 ;
     RECT  71.592 38.437 72.6 39.109 ;
     RECT  54.888 38.485 56.208 40.261 ;
     RECT  26.832 38.771 27.936 39.061 ;
     RECT  8.856 39.013 9.888 40.019 ;
     RECT  26.856 39.061 27.936 41.125 ;
     RECT  35.208 39.061 36.384 40.261 ;
     RECT  51.768 39.253 52.896 42.133 ;
     RECT  52.92 39.253 54.336 40.693 ;
     RECT  60.36 39.253 61.632 40.405 ;
     RECT  65.304 39.253 66.384 40.163 ;
     RECT  17.16 39.301 18.192 40.405 ;
     RECT  40.512 39.301 41.616 40.835 ;
     RECT  19.176 39.395 20.592 44.965 ;
     RECT  48.84 39.589 49.872 42.995 ;
     RECT  12.168 40.163 13.2 41.027 ;
     RECT  6.36 40.213 7.44 40.259 ;
     RECT  6.36 40.259 7.8 43.093 ;
     RECT  35.208 40.261 36.288 40.499 ;
     RECT  54.888 40.261 55.872 42.565 ;
     RECT  60.456 40.405 61.632 41.363 ;
     RECT  73.224 40.405 74.688 41.075 ;
     RECT  60.336 40.451 60.432 41.363 ;
     RECT  35.208 40.499 36.384 40.691 ;
     RECT  57.528 40.597 58.704 41.651 ;
     RECT  35.112 40.691 36.384 46.019 ;
     RECT  42.168 40.789 43.44 43.331 ;
     RECT  36.456 40.835 37.632 42.995 ;
     RECT  40.512 40.835 42.144 40.981 ;
     RECT  46.44 40.979 46.776 40.981 ;
     RECT  40.872 40.981 42.144 42.131 ;
     RECT  12.072 41.027 13.2 44.821 ;
     RECT  26.856 41.125 27.888 41.461 ;
     RECT  29.712 41.267 30.72 43.477 ;
     RECT  60.336 41.363 61.632 41.557 ;
     RECT  59.256 41.557 61.632 41.749 ;
     RECT  67.512 41.557 68.928 43.955 ;
     RECT  30.744 41.651 32.064 42.709 ;
     RECT  32.088 41.651 33.264 48.323 ;
     RECT  57.336 41.651 58.704 42.179 ;
     RECT  59.256 41.749 60.528 42.037 ;
     RECT  60.552 41.749 61.632 42.133 ;
     RECT  27.24 41.939 28.368 45.251 ;
     RECT  59.448 42.037 60.528 42.853 ;
     RECT  74.808 42.085 75.984 43.283 ;
     RECT  40.512 42.131 42.144 43.331 ;
     RECT  4.344 42.133 5.808 43.283 ;
     RECT  33.288 42.227 34.8 43.093 ;
     RECT  28.392 42.803 29.4 54.517 ;
     RECT  52.92 42.803 54.336 43.861 ;
     RECT  59.544 42.853 60.528 42.995 ;
     RECT  36.456 42.995 37.968 44.053 ;
     RECT  48.84 42.995 50.64 43.765 ;
     RECT  59.544 42.995 60.672 44.147 ;
     RECT  33.288 43.093 34.704 43.283 ;
     RECT  6.36 43.235 7.8 44.437 ;
     RECT  33.288 43.283 34.8 44.725 ;
     RECT  30.744 43.331 31.968 45.635 ;
     RECT  40.512 43.331 41.208 43.477 ;
     RECT  42.768 43.331 43.44 43.475 ;
     RECT  42.768 43.475 42.792 43.861 ;
     RECT  49.464 43.765 50.64 44.437 ;
     RECT  68.952 43.861 70.368 43.955 ;
     RECT  70.392 43.861 71.568 43.955 ;
     RECT  67.512 43.955 70.368 44.197 ;
     RECT  70.392 43.955 70.488 44.341 ;
     RECT  3.288 44.053 4.32 44.627 ;
     RECT  36.456 44.053 37.728 45.587 ;
     RECT  59.4 44.147 60.672 45.011 ;
     RECT  52.68 44.195 53.712 45.539 ;
     RECT  67.512 44.197 69.504 44.965 ;
     RECT  6.36 44.437 7.68 45.059 ;
     RECT  73.8 44.485 74.784 44.531 ;
     RECT  29.712 44.531 30.72 50.051 ;
     RECT  2.904 44.627 4.32 45.971 ;
     RECT  47.4 44.629 48.432 44.867 ;
     RECT  82.392 44.675 83.4 46.067 ;
     RECT  33.432 44.725 34.8 45.731 ;
     RECT  47.208 44.867 48.432 45.587 ;
     RECT  19.368 44.965 20.592 50.051 ;
     RECT  67.512 44.965 68.928 45.541 ;
     RECT  6.36 45.059 7.8 46.357 ;
     RECT  79.704 45.059 80.232 46.453 ;
     RECT  49.56 45.491 50.64 45.731 ;
     RECT  67.848 45.541 68.928 45.685 ;
     RECT  36.456 45.587 37.968 47.267 ;
     RECT  48.336 45.587 48.432 46.357 ;
     RECT  30.744 45.635 32.064 50.051 ;
     RECT  33.288 45.731 34.8 48.277 ;
     RECT  49.464 45.731 50.64 55.571 ;
     RECT  35.112 46.019 36.432 49.667 ;
     RECT  82.344 46.067 83.4 49.525 ;
     RECT  40.512 46.165 41.616 47.603 ;
     RECT  66.216 46.259 67.2 49.813 ;
     RECT  6.552 46.357 7.8 46.883 ;
     RECT  79.704 46.453 80.736 46.787 ;
     RECT  68.424 46.595 69.504 46.787 ;
     RECT  68.424 46.787 70.128 47.027 ;
     RECT  68.424 47.027 69.528 47.845 ;
     RECT  38.28 47.221 39.792 50.101 ;
     RECT  40.512 47.603 41.664 49.091 ;
     RECT  13.512 47.653 14.832 49.861 ;
     RECT  11.472 47.699 12.048 48.805 ;
     RECT  17.232 47.699 18.144 47.845 ;
     RECT  76.056 47.749 77.568 49.525 ;
     RECT  16.68 47.845 18.144 48.949 ;
     RECT  68.424 47.845 69.504 48.853 ;
     RECT  33.432 48.277 34.8 49.187 ;
     RECT  32.088 48.323 33.408 49.187 ;
     RECT  57.336 48.373 58.848 48.851 ;
     RECT  57.336 48.851 58.872 49.765 ;
     RECT  21.672 48.901 23.184 50.579 ;
     RECT  69.096 48.947 69.528 49.043 ;
     RECT  17.112 48.949 18.144 49.091 ;
     RECT  2.712 48.997 3.744 50.051 ;
     RECT  4.344 49.043 5.616 49.091 ;
     RECT  68.856 49.043 69.528 49.285 ;
     RECT  40.512 49.091 41.544 49.765 ;
     RECT  37.032 49.141 38.256 49.571 ;
     RECT  32.088 49.187 33.096 49.477 ;
     RECT  68.856 49.285 70.176 50.339 ;
     RECT  67.512 49.427 68.832 50.533 ;
     RECT  32.088 49.477 33.072 50.005 ;
     RECT  76.056 49.525 77.184 49.715 ;
     RECT  35.112 49.667 35.256 51.109 ;
     RECT  40.512 49.765 41.52 50.821 ;
     RECT  57.336 49.765 58.752 50.101 ;
     RECT  58.776 49.765 58.872 50.101 ;
     RECT  2.712 50.051 3.84 50.771 ;
     RECT  19.176 50.051 20.592 51.923 ;
     RECT  31.344 50.051 32.064 51.301 ;
     RECT  66.216 50.099 67.2 50.339 ;
     RECT  38.328 50.101 39.792 50.293 ;
     RECT  57.336 50.101 58.704 50.435 ;
     RECT  59.256 50.101 60.768 50.819 ;
     RECT  38.472 50.293 39.792 50.677 ;
     RECT  70.872 50.293 72.336 50.389 ;
     RECT  65.832 50.339 67.2 54.133 ;
     RECT  70.872 50.389 72.192 54.755 ;
     RECT  57.336 50.435 58.752 51.253 ;
     RECT  67.656 50.533 68.832 54.421 ;
     RECT  13.704 50.723 14.784 52.499 ;
     RECT  81.432 50.771 82.608 51.781 ;
     RECT  57.72 51.253 58.752 52.211 ;
     RECT  31.344 51.301 31.968 51.445 ;
     RECT  78.696 51.443 79.68 52.499 ;
     RECT  18.144 51.491 18.192 52.405 ;
     RECT  80.04 51.877 81.408 51.923 ;
     RECT  19.176 51.923 19.32 52.021 ;
     RECT  57.336 52.211 58.752 53.027 ;
     RECT  82.368 52.403 82.608 53.557 ;
     RECT  17.112 52.405 18.192 52.547 ;
     RECT  13.704 52.499 14.832 54.371 ;
     RECT  31.368 52.499 32.448 54.275 ;
     RECT  78.312 52.499 79.68 54.179 ;
     RECT  18.096 52.547 18.192 53.029 ;
     RECT  52.488 52.837 53.712 53.267 ;
     RECT  54.888 52.931 56.4 54.517 ;
     RECT  39.048 53.029 40.2 53.795 ;
     RECT  35.208 53.075 35.88 53.267 ;
     RECT  35.112 53.267 35.88 53.365 ;
     RECT  51.816 53.267 53.712 53.507 ;
     RECT  28.176 53.315 28.272 54.661 ;
     RECT  35.112 53.365 36.864 53.939 ;
     RECT  36.888 53.365 37.872 53.939 ;
     RECT  51.528 53.507 53.712 53.939 ;
     RECT  11.28 53.555 12.24 54.517 ;
     RECT  62.112 53.557 63.408 54.085 ;
     RECT  63.432 53.557 64.944 53.699 ;
     RECT  63.432 53.699 65.232 54.661 ;
     RECT  35.112 53.939 37.872 54.373 ;
     RECT  51.432 53.939 53.712 54.469 ;
     RECT  62.112 54.085 63.216 59.605 ;
     RECT  24.456 54.133 25.824 54.229 ;
     RECT  30.264 54.133 31.344 54.275 ;
     RECT  65.832 54.133 66.816 54.275 ;
     RECT  82.368 54.179 82.608 55.189 ;
     RECT  65.832 54.275 67.2 56.101 ;
     RECT  79.992 54.323 80.04 55.525 ;
     RECT  35.112 54.373 36.336 54.995 ;
     RECT  36.36 54.373 37.872 54.949 ;
     RECT  67.8 54.421 68.832 55.237 ;
     RECT  51.432 54.469 52.656 54.611 ;
     RECT  52.68 54.469 53.712 55.283 ;
     RECT  10.872 54.517 12.24 54.659 ;
     RECT  55.032 54.517 56.4 55.283 ;
     RECT  51.312 54.611 52.656 57.059 ;
     RECT  56.712 54.611 57.336 54.901 ;
     RECT  10.872 54.659 10.968 54.707 ;
     RECT  63.864 54.661 65.232 54.803 ;
     RECT  10.944 54.707 10.968 55.285 ;
     RECT  28.2 54.707 29.4 56.099 ;
     RECT  56.712 54.901 57.696 56.819 ;
     RECT  48.912 55.283 49.152 55.429 ;
     RECT  54.888 55.283 56.4 61.333 ;
     RECT  47.64 55.429 49.152 55.907 ;
     RECT  80.376 55.525 81.648 56.483 ;
     RECT  49.176 55.571 50.64 55.907 ;
     RECT  49.68 55.907 50.64 56.965 ;
     RECT  13.704 56.005 15.024 57.349 ;
     RECT  28.176 56.099 29.4 57.205 ;
     RECT  65.832 56.101 67.008 57.011 ;
     RECT  78.456 56.197 79.968 57.445 ;
     RECT  23.232 56.435 23.328 57.685 ;
     RECT  79.992 56.483 81.648 57.349 ;
     RECT  74.472 56.485 75.936 56.627 ;
     RECT  74.472 56.627 75.048 56.821 ;
     RECT  56.712 56.819 57 58.117 ;
     RECT  75 56.821 75.048 58.117 ;
     RECT  65.832 57.011 67.2 59.315 ;
     RECT  27.672 57.205 29.4 57.349 ;
     RECT  39.504 57.299 39.648 57.347 ;
     RECT  68.664 57.299 68.856 57.443 ;
     RECT  39.504 57.347 39.696 58.741 ;
     RECT  13.704 57.349 14.832 58.115 ;
     RECT  27.672 57.349 29.088 57.491 ;
     RECT  79.992 57.349 81.456 58.069 ;
     RECT  81.48 57.395 82.512 58.547 ;
     RECT  68.472 57.443 68.856 58.645 ;
     RECT  27.672 57.491 29.4 58.453 ;
     RECT  2.808 57.541 3.936 60.035 ;
     RECT  3.96 57.541 4.992 58.163 ;
     RECT  42.648 57.541 43.872 59.891 ;
     RECT  30.264 57.589 31.584 57.731 ;
     RECT  78.312 57.635 79.392 58.691 ;
     RECT  18.912 57.637 19.92 59.171 ;
     RECT  30.264 57.731 32.448 58.645 ;
     RECT  49.68 57.731 50.64 58.693 ;
     RECT  13.104 57.875 13.2 58.645 ;
     RECT  71.064 57.875 72.192 58.259 ;
     RECT  32.472 57.877 33.456 58.453 ;
     RECT  33.48 57.877 34.8 58.117 ;
     RECT  58.656 57.971 59.616 59.125 ;
     RECT  79.992 58.069 81.024 58.547 ;
     RECT  13.704 58.115 15.024 60.469 ;
     RECT  33.672 58.117 34.8 59.845 ;
     RECT  27.672 58.453 29.088 58.549 ;
     RECT  79.416 58.547 81.024 58.691 ;
     RECT  27.96 58.549 29.088 58.645 ;
     RECT  12.024 58.645 13.2 59.315 ;
     RECT  30.696 58.645 32.448 59.221 ;
     RECT  80.112 58.691 81.024 59.797 ;
     RECT  51.312 58.693 52.32 59.267 ;
     RECT  56.712 58.739 57 59.125 ;
     RECT  38.472 58.741 39.696 59.315 ;
     RECT  27.96 58.787 29.4 59.795 ;
     RECT  60.072 59.029 61.584 59.221 ;
     RECT  56.712 59.125 58.128 60.373 ;
     RECT  58.152 59.125 59.616 60.659 ;
     RECT  18.912 59.171 20.4 60.515 ;
     RECT  30.696 59.221 32.16 59.411 ;
     RECT  52.872 59.221 54.336 60.707 ;
     RECT  60.216 59.221 61.584 60.659 ;
     RECT  12.528 59.315 13.2 60.373 ;
     RECT  38.472 59.315 39.888 60.611 ;
     RECT  65.4 59.315 67.2 60.373 ;
     RECT  17.208 59.605 18.6 60.851 ;
     RECT  35.112 59.605 36.528 61.427 ;
     RECT  36.552 59.605 37.872 60.035 ;
     RECT  27.672 59.795 29.4 60.373 ;
     RECT  33.672 59.845 34.704 59.987 ;
     RECT  33.672 59.987 34.8 60.467 ;
     RECT  2.808 60.035 4.32 61.333 ;
     RECT  27.672 60.373 29.088 60.659 ;
     RECT  57.096 60.373 58.128 60.659 ;
     RECT  65.4 60.373 66.816 61.957 ;
     RECT  33.48 60.467 34.8 60.803 ;
     RECT  58.656 60.659 59.616 61.525 ;
     RECT  52.872 60.707 54.72 61.043 ;
     RECT  32.808 60.803 34.8 62.053 ;
     RECT  15.576 60.805 17.088 61.043 ;
     RECT  41.496 60.805 42.624 60.851 ;
     RECT  17.112 60.851 18.6 61.043 ;
     RECT  50.64 60.851 50.736 61.333 ;
     RECT  52.872 61.043 54.864 61.427 ;
     RECT  10.632 61.141 11.904 61.571 ;
     RECT  72.912 61.141 74.112 63.205 ;
     RECT  11.928 61.187 13.2 63.205 ;
     RECT  13.704 61.187 15.024 61.619 ;
     RECT  74.136 61.187 75.264 61.763 ;
     RECT  4.824 61.189 6.288 61.813 ;
     RECT  49.32 61.333 50.736 63.107 ;
     RECT  55.128 61.333 56.4 61.909 ;
     RECT  26.52 61.381 27.648 62.723 ;
     RECT  53.376 61.427 54.864 61.717 ;
     RECT  13.704 61.619 15.552 62.629 ;
     RECT  40.512 61.619 40.632 63.013 ;
     RECT  53.376 61.717 53.52 62.437 ;
     RECT  53.544 61.717 54.864 63.251 ;
     RECT  74.136 61.763 75.288 62.677 ;
     RECT  55.128 61.909 56.304 62.629 ;
     RECT  4.824 61.955 6.288 62.003 ;
     RECT  65.784 61.957 66.816 62.773 ;
     RECT  18.912 62.053 20.208 65.701 ;
     RECT  32.808 62.053 34.272 62.531 ;
     RECT  44.472 62.149 45.6 63.779 ;
     RECT  72.192 62.195 72.384 63.061 ;
     RECT  32.808 62.531 33.048 62.629 ;
     RECT  38.76 62.533 40.032 67.189 ;
     RECT  14.28 62.629 15.552 63.251 ;
     RECT  32.904 62.629 33.048 62.725 ;
     RECT  55.176 62.629 56.304 62.867 ;
     RECT  24.312 62.677 25.632 63.299 ;
     RECT  74.136 62.677 75.36 64.307 ;
     RECT  55.176 62.867 56.4 64.981 ;
     RECT  45.912 63.011 46.344 63.781 ;
     RECT  71.256 63.061 72.384 63.395 ;
     RECT  65.52 63.155 66.24 64.645 ;
     RECT  12.168 63.205 13.2 64.357 ;
     RECT  32.496 63.299 32.688 64.549 ;
     RECT  71.256 63.395 72.6 64.883 ;
     RECT  45.912 63.781 47.088 64.595 ;
     RECT  70.152 63.781 71.232 64.595 ;
     RECT  80.04 64.019 81.024 64.979 ;
     RECT  62.112 64.307 63.216 65.939 ;
     RECT  74.136 64.307 74.52 64.357 ;
     RECT  35.352 64.355 35.832 65.653 ;
     RECT  15.576 64.357 17.088 65.027 ;
     RECT  17.112 64.357 18.6 65.027 ;
     RECT  45.912 64.595 46.776 64.885 ;
     RECT  65.544 64.691 66.72 66.755 ;
     RECT  80.04 64.979 81.168 66.853 ;
     RECT  55.272 64.981 56.4 74.147 ;
     RECT  28.296 65.029 29.4 65.077 ;
     RECT  31.032 65.077 32.496 65.651 ;
     RECT  24.312 65.125 25.392 65.555 ;
     RECT  25.416 65.125 26.88 65.315 ;
     RECT  20.232 65.171 20.616 66.517 ;
     RECT  45.912 65.171 46.728 66.373 ;
     RECT  81.672 65.221 83.04 67.811 ;
     RECT  25.416 65.315 27.312 65.555 ;
     RECT  28.296 65.315 29.4 67.331 ;
     RECT  69.36 65.411 69.552 66.853 ;
     RECT  33.624 65.507 34.704 65.843 ;
     RECT  24.312 65.555 24.504 65.941 ;
     RECT  26.208 65.555 27.312 66.131 ;
     RECT  31.032 65.651 32.688 66.085 ;
     RECT  78.504 65.653 80.016 65.891 ;
     RECT  73.752 65.699 74.52 66.661 ;
     RECT  19.032 65.701 20.208 68.243 ;
     RECT  35.112 65.795 35.208 67.285 ;
     RECT  24.312 66.083 24.504 67.381 ;
     RECT  31.272 66.085 32.688 67.283 ;
     RECT  26.208 66.131 27.84 66.661 ;
     RECT  76.296 66.325 77.568 66.755 ;
     RECT  13.8 66.469 15.12 66.611 ;
     RECT  26.232 66.661 27.84 67.237 ;
     RECT  73.752 66.661 74.928 67.141 ;
     RECT  20.232 66.707 21.744 68.435 ;
     RECT  76.248 66.755 77.568 67.189 ;
     RECT  68.136 66.853 69.552 68.963 ;
     RECT  74.952 66.995 76.224 68.341 ;
     RECT  73.8 67.141 74.928 67.669 ;
     RECT  76.248 67.189 77.472 68.963 ;
     RECT  26.232 67.237 27.792 67.333 ;
     RECT  30.696 67.283 32.688 67.379 ;
     RECT  27.96 67.331 29.4 67.717 ;
     RECT  26.616 67.333 27.792 68.195 ;
     RECT  29.976 67.379 32.688 68.341 ;
     RECT  24.312 67.381 25.776 69.445 ;
     RECT  61.584 67.427 61.632 67.811 ;
     RECT  38.472 67.523 39.6 72.803 ;
     RECT  12.072 67.669 13.2 70.499 ;
     RECT  27.96 67.717 29.28 68.099 ;
     RECT  61.584 67.811 61.68 68.917 ;
     RECT  66.72 67.859 66.816 68.917 ;
     RECT  27.96 68.099 29.4 69.251 ;
     RECT  40.632 68.101 41.616 68.819 ;
     RECT  18.912 68.243 20.208 68.435 ;
     RECT  29.976 68.341 31.152 69.011 ;
     RECT  31.176 68.341 32.688 69.587 ;
     RECT  75.24 68.341 76.224 68.483 ;
     RECT  73.752 68.483 74.928 69.539 ;
     RECT  74.952 68.483 76.224 68.917 ;
     RECT  35.112 68.771 35.208 69.829 ;
     RECT  10.824 68.773 12.048 69.731 ;
     RECT  40.512 68.819 41.616 68.963 ;
     RECT  2.712 68.917 3.936 70.115 ;
     RECT  65.16 68.917 66.528 70.645 ;
     RECT  74.952 68.917 75.984 69.493 ;
     RECT  68.136 68.963 69.648 69.587 ;
     RECT  76.008 68.963 77.472 69.731 ;
     RECT  80.04 68.963 81.12 70.069 ;
     RECT  29.712 69.011 31.152 69.587 ;
     RECT  78.744 69.011 80.016 69.971 ;
     RECT  32.712 69.301 34.224 70.163 ;
     RECT  81.24 69.349 82.608 70.739 ;
     RECT  24.312 69.445 25.344 72.709 ;
     RECT  17.352 69.493 18.6 71.267 ;
     RECT  73.752 69.539 75.024 70.163 ;
     RECT  29.712 69.587 32.688 69.877 ;
     RECT  76.008 69.731 77.52 70.835 ;
     RECT  35.112 69.829 36.624 70.645 ;
     RECT  29.712 69.877 31.2 70.835 ;
     RECT  31.224 69.877 32.688 70.403 ;
     RECT  78.312 69.971 80.016 71.125 ;
     RECT  52.44 70.021 53.424 70.067 ;
     RECT  80.04 70.069 81.072 70.837 ;
     RECT  32.712 70.163 34.8 70.357 ;
     RECT  51.312 70.259 52.416 70.739 ;
     RECT  33.048 70.357 34.8 71.509 ;
     RECT  35.352 70.645 36.624 70.691 ;
     RECT  65.544 70.645 66.528 71.123 ;
     RECT  81.24 70.739 83.04 71.411 ;
     RECT  29.712 70.835 30.696 71.989 ;
     RECT  65.112 71.123 66.528 71.843 ;
     RECT  78.648 71.125 80.016 72.901 ;
     RECT  18.288 71.267 18.6 72.325 ;
     RECT  81.24 71.411 83.4 71.749 ;
     RECT  33.528 71.509 34.8 72.563 ;
     RECT  82.056 71.749 83.4 72.419 ;
     RECT  65.112 71.843 65.16 72.325 ;
     RECT  80.904 71.843 82.032 72.419 ;
     RECT  44.568 72.133 45.6 73.235 ;
     RECT  5.832 72.419 6.912 72.995 ;
     RECT  37.32 72.517 38.448 72.803 ;
     RECT  67.512 72.805 68.88 75.109 ;
     RECT  76.44 72.901 77.904 72.997 ;
     RECT  44.832 73.235 45.6 74.101 ;
     RECT  13.608 73.621 14.784 74.627 ;
     RECT  19.656 74.293 20.784 74.675 ;
     RECT  13.512 74.627 14.784 75.299 ;
     RECT  76.488 75.541 78 75.781 ;
     RECT  76.872 75.781 78 75.829 ;
  END
END ot_hgi_qdq_core
END LIBRARY
